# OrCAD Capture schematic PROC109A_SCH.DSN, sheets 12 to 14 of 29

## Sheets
12 12. SOC2: size C; title: SOC2
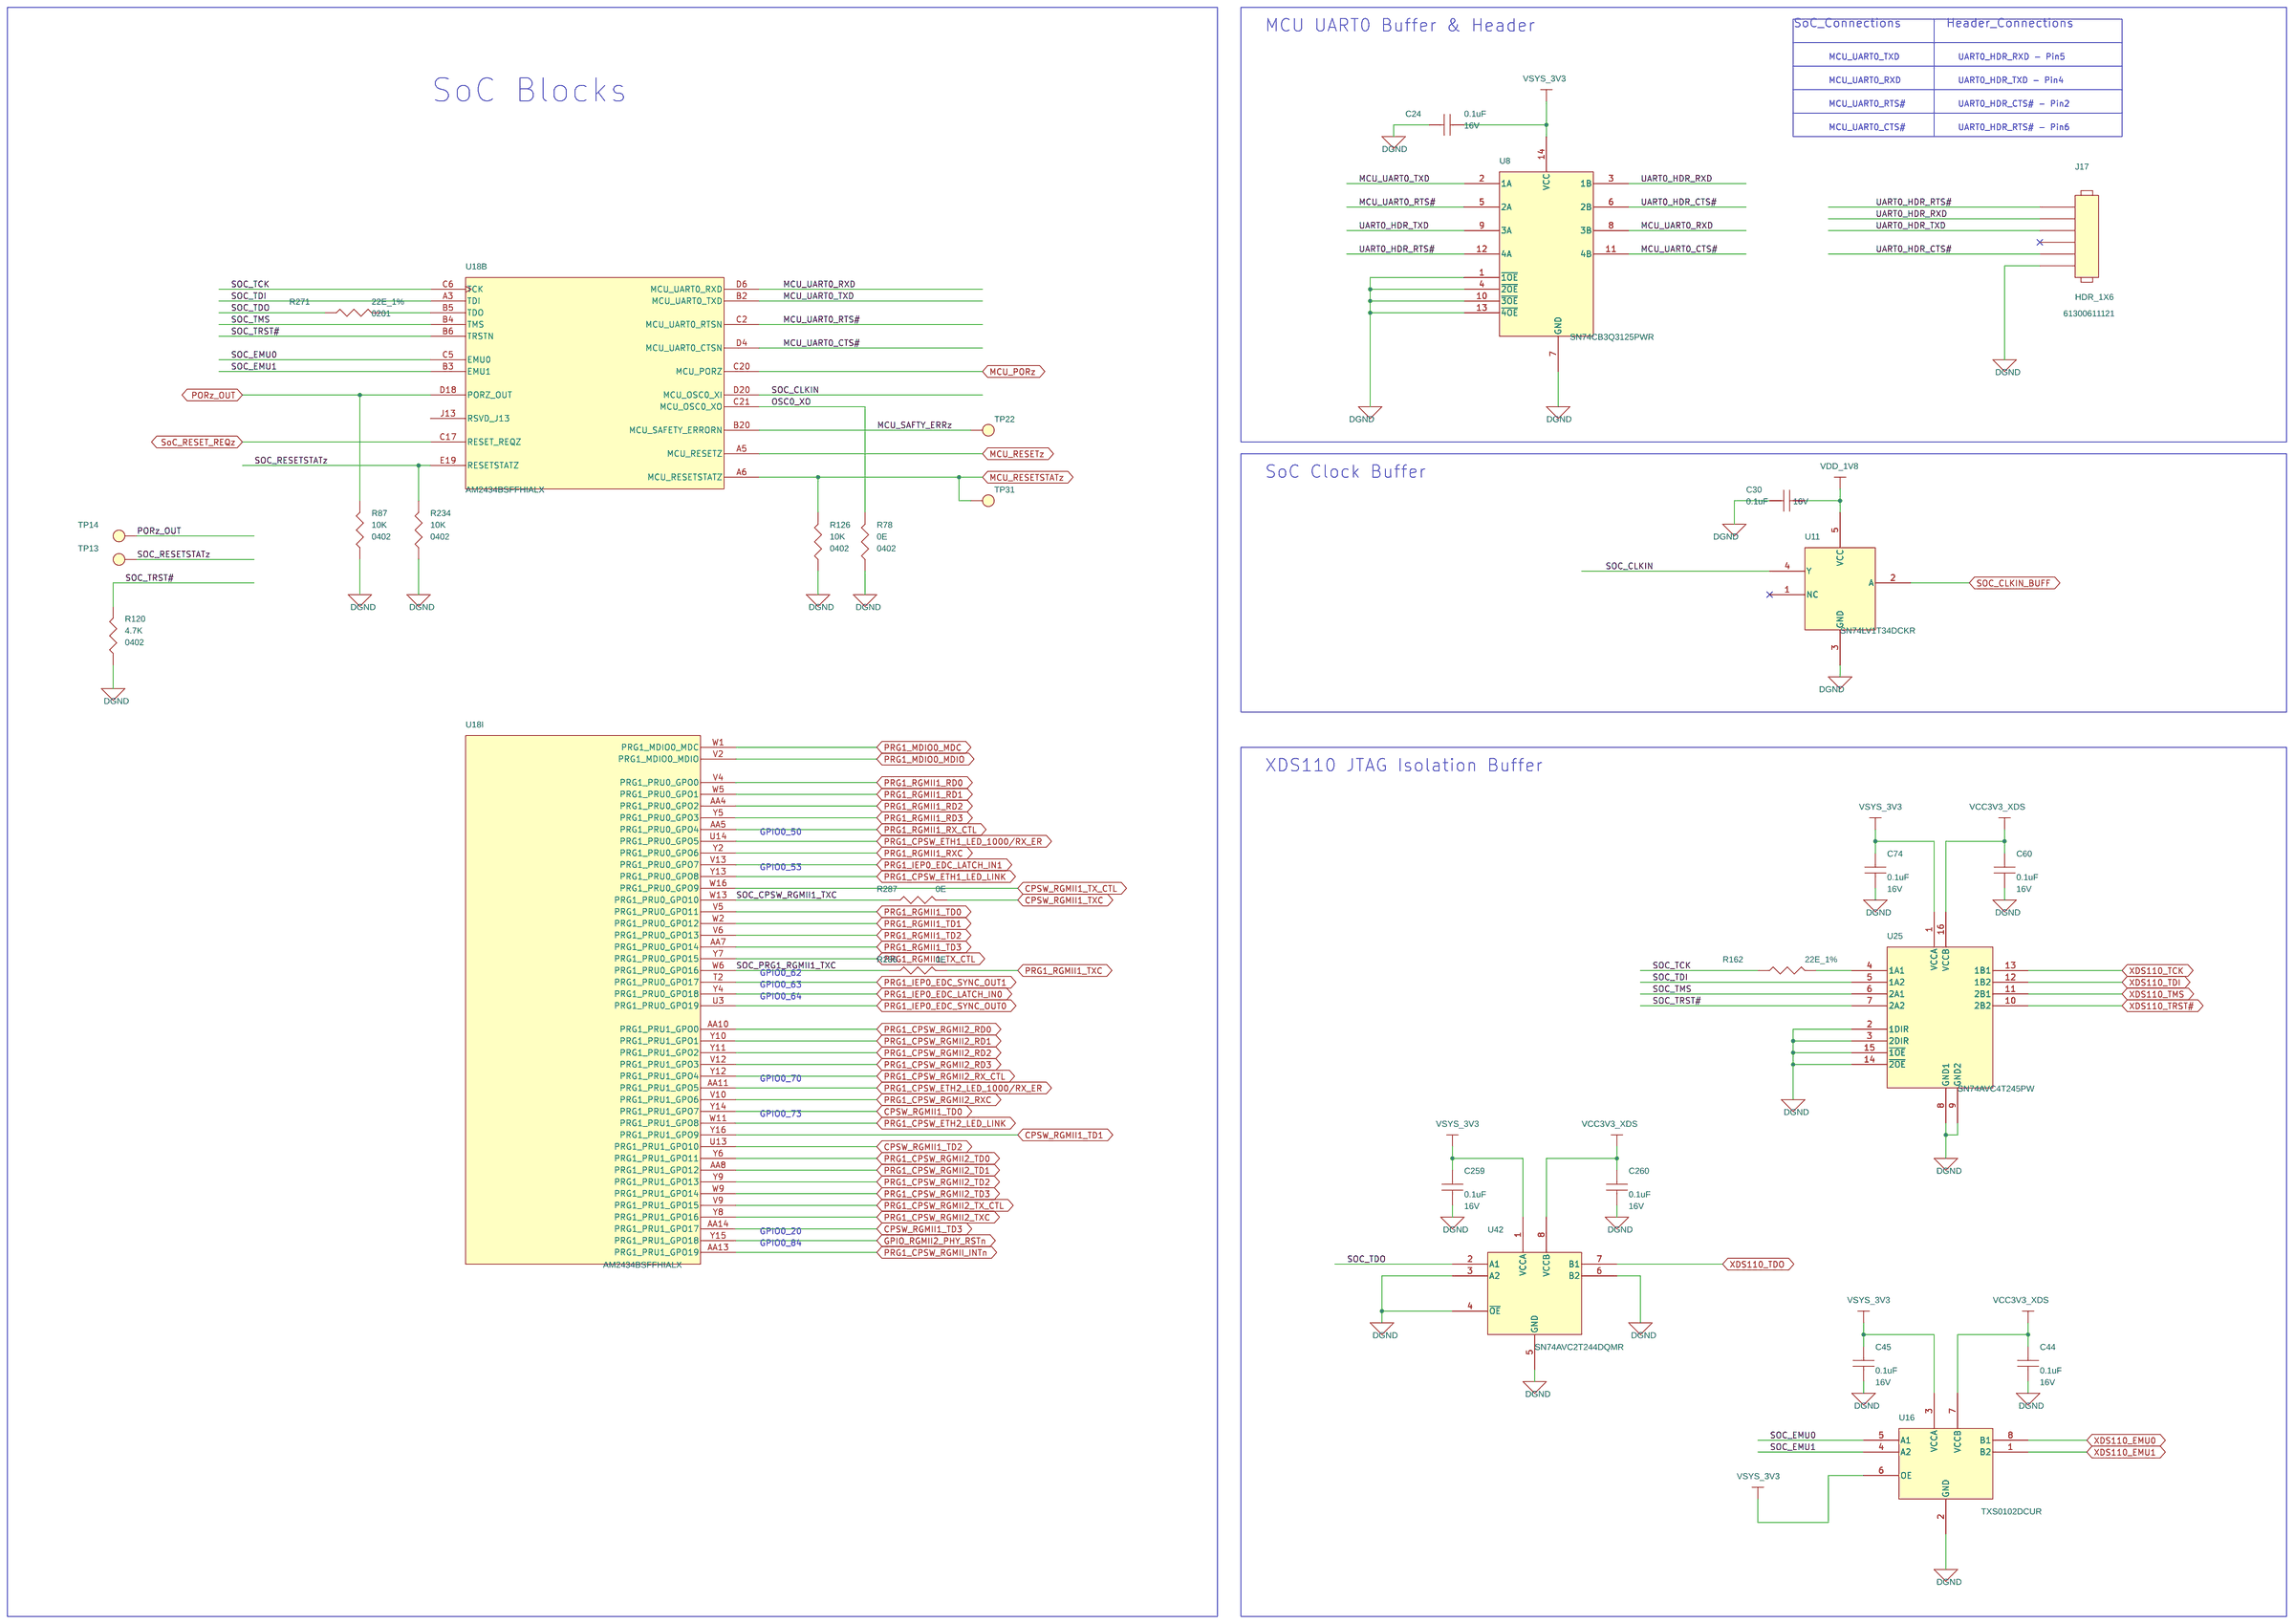
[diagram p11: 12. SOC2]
13 13. MCAN_eQEP_FSI_MUX_USR_LEDs: size C; title: MCAN_eQEP_FSI_MUX
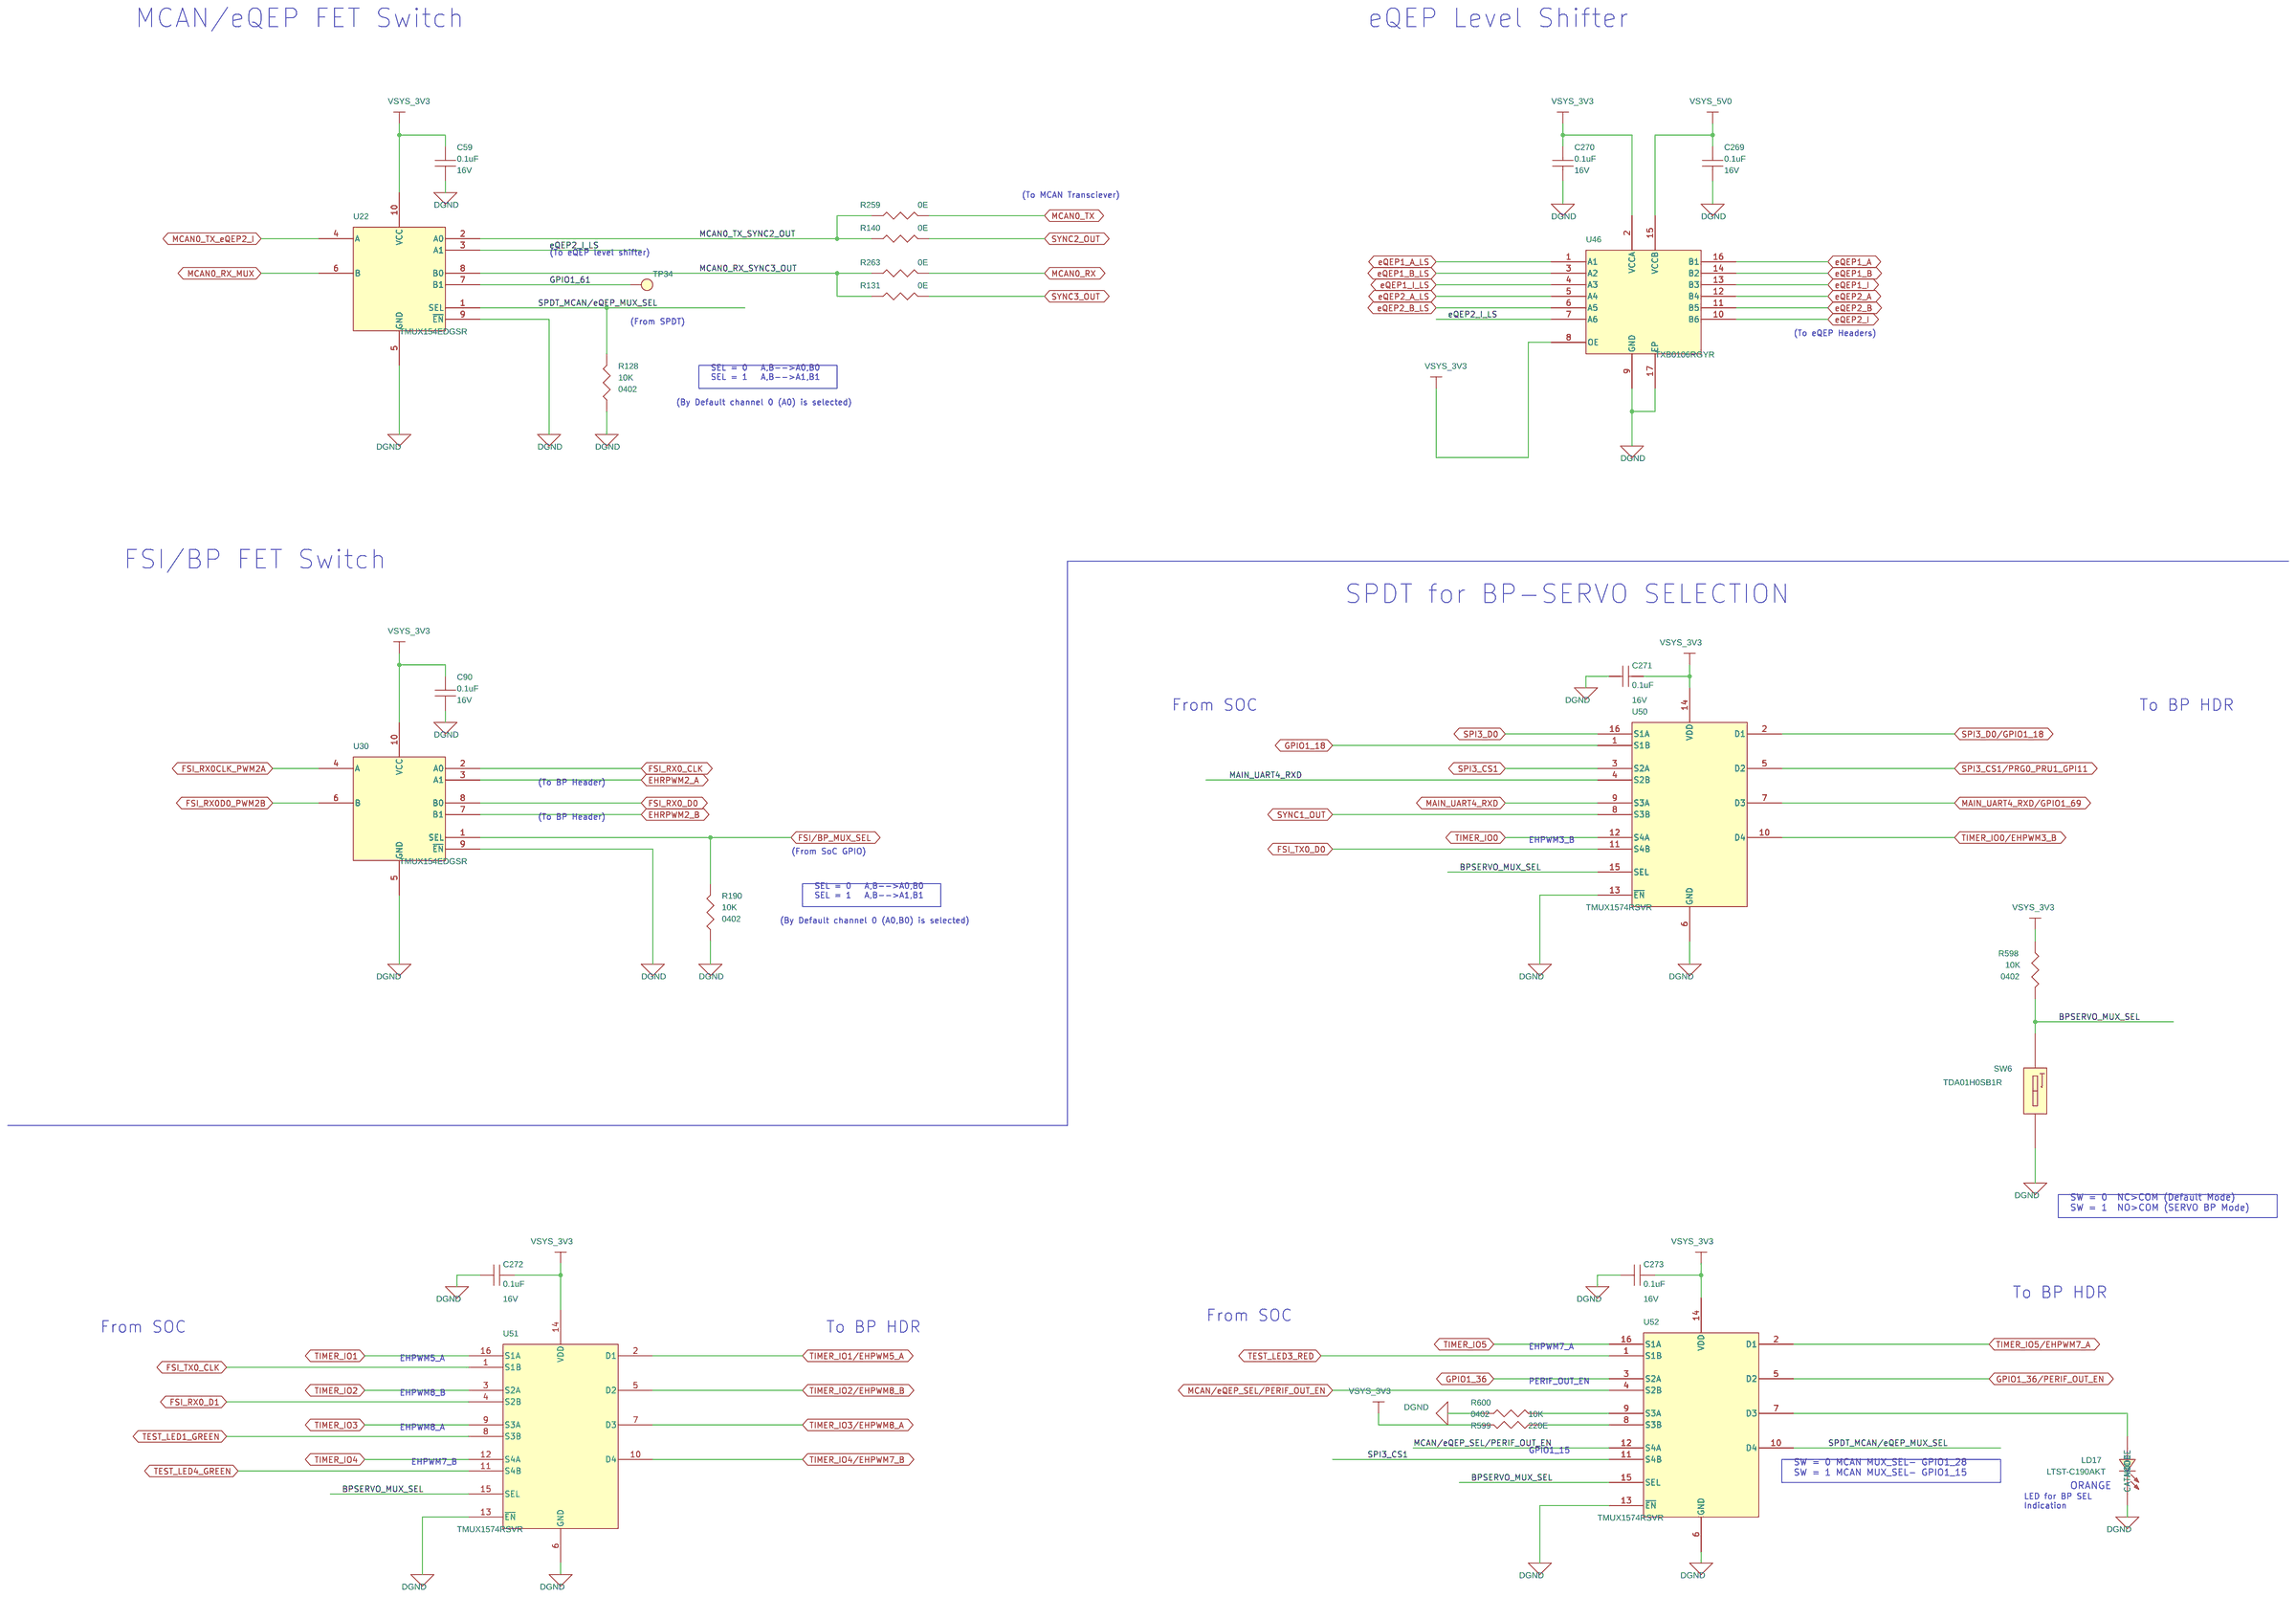
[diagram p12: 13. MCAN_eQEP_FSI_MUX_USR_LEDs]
14 14. CAN_eQEP_FSI_HDR_CLK_BUFFER: size C; title: CAN_eQEP_FSI_HEADERs & CLOCK BUFFER

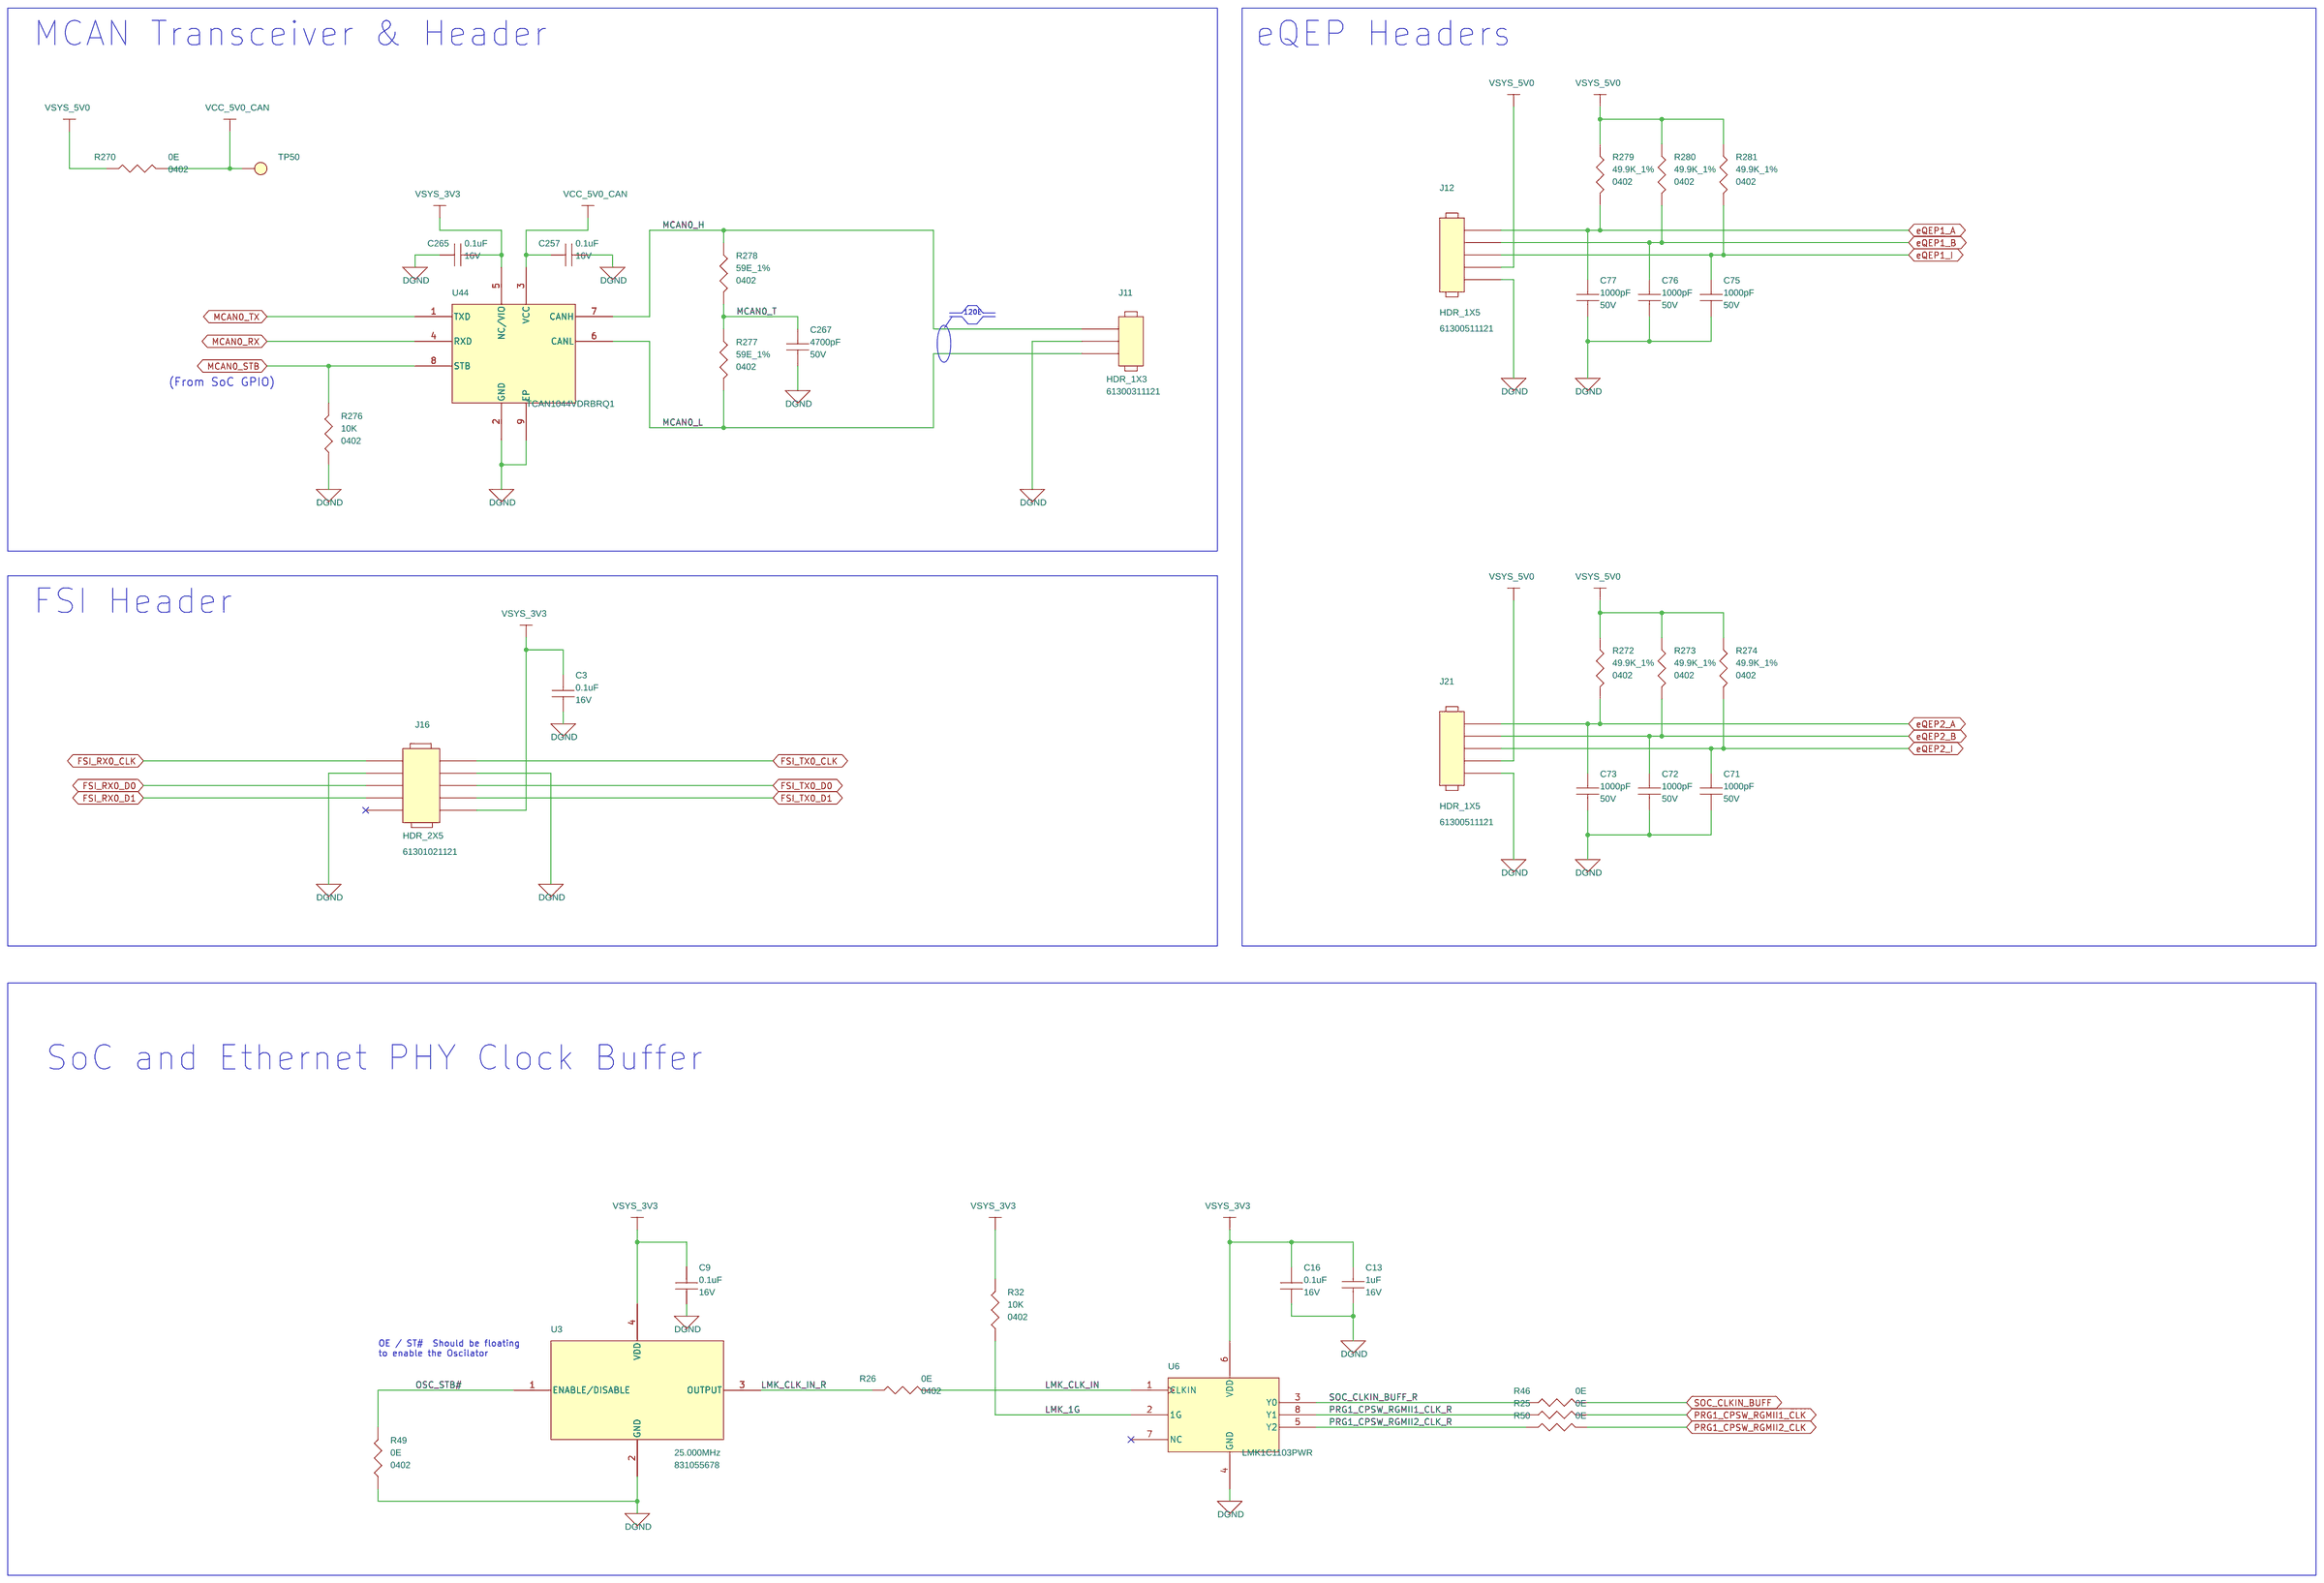
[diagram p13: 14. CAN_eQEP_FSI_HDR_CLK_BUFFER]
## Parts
sheet 12. SOC2
C24  0.1uF  [CAP0201_0-5]
C30  0.1uF  [CAP0201_0-5]
C44  0.1uF  [CAP0201_0-5]
C45  0.1uF  [CAP0201_0-5]
C60  0.1uF  [CAP0201_0-5]
C74  0.1uF  [CAP0201_0-5]
C259  0.1uF  [CAP0201_0-5]
C260  0.1uF  [CAP0201_0-5]
J17  HDR_1X6  [HDR_1X6_61300611121_S_T_8-6]
R78  0E  [RES0402_0-5]
R87  10K  [RES0402_0-5]
R120  4.7K  [RES0402_0-5]
R126  10K  [RES0402_0-5]
R162  22E_1%  [RES0201_0-5]
R234  10K  [RES0402_0-5]
R271  22E_1%  [RES0201_0-5]
R286  0E  [RES0402_0-5]
R287  0E  [RES0402_0-5]
TP13  TP20_SMD  [TP20_SMD]
TP14  TP20_SMD  [TP20_SMD]
TP22  TP20_SMD  [TP20_SMD]
TP31  TP20_SMD  [TP20_SMD]
U8  SN74CB3Q3125PWR  [TSSOP14_25-59_205X180_1-2]
U11  SN74LV1T34DCKR  [SC70-5_1-1]
U16  TXS0102DCUR  [VSSOP8_19-68_85X95_0-9]
U25  SN74AVC4T245PW  [TSSOP16_25-59_205X180]
U42  SN74AVC2T244DQMR  [X2SON8_15-74_70X50]
sheet 13. MCAN_eQEP_FSI_MUX_USR_LEDs
C59  0.1uF  [CAP0201_0-5]
C90  0.1uF  [CAP0201_0-5]
C269  0.1uF  [CAP0201_0-5]
C270  0.1uF  [CAP0201_0-5]
C271  0.1uF  [CAP0201_0-5]
C272  0.1uF  [CAP0201_0-5]
C273  0.1uF  [CAP0201_0-5]
LD17  LTST-C190AKT  [LED_0603]
R128  10K  [RES0402_0-5]
R131  0E  [RES0402_0-5]
R140  0E  [RES0402_0-5]
R190  10K  [RES0402_0-5]
R259  0E  [RES0402_0-5]
R263  0E  [RES0402_0-5]
R598  10K  [RES0402_0-5]
R599  220E  [RES0402_0-5]
R600  10K  [RES0402_0-5]
SW6  TDA01H0SB1R  [SW_TDA01H0S_240X90_SMD_2-3]
TP34  TP20_SMD  [TP20_SMD]
U22  TMUX154EDGSR  [MSOP10_19-68_120X120_1-1]
U30  TMUX154EDGSR  [MSOP10_19-68_120X120_1-1]
U46  TXB0106RGYR  [QFN16_19-68_160X140_1]
U50  TMUX1574RSVR  [UQFN16_TMUX1574_70X100_0-6]
U51  TMUX1574RSVR  [UQFN16_TMUX1574_70X100_0-6]
U52  TMUX1574RSVR  [UQFN16_TMUX1574_70X100_0-6]
sheet 14. CAN_eQEP_FSI_HDR_CLK_BUFFER
C3  0.1uF  [CAP0201_0-5]
C9  0.1uF  [CAP0201_0-5]
C13  1uF  [CAP0201_0-5]
C16  0.1uF  [CAP0201_0-5]
C71  1000pF  [CAP0402_0-75]
C72  1000pF  [CAP0402_0-75]
C73  1000pF  [CAP0402_0-75]
C75  1000pF  [CAP0402_0-75]
C76  1000pF  [CAP0402_0-75]
C77  1000pF  [CAP0402_0-75]
C257  0.1uF  [CAP0201_0-5]
C265  0.1uF  [CAP0201_0-5]
C267  4700pF  [CAP0402_0-75]
J11  HDR_1X3  [HDR_1X3_100_S_T]
J12  HDR_1X5  [HDR_1X5_61300511121_S_T_8-6]
J16  HDR_2X5  [HDR_2X5_61301021121_S_T_8-6]
J21  HDR_1X5  [HDR_1X5_61300511121_S_T_8-6]
R25  0E  [RES0402_0-5]
R26  0E  [RES0402_0-5]
R32  10K  [RES0402_0-5]
R46  0E  [RES0402_0-5]
R49  0E  [RES0402_0-5]
R50  0E  [RES0402_0-5]
R270  0E  [RES0402_0-5]
R272  49.9K_1%  [RES0402_0-5]
R273  49.9K_1%  [RES0402_0-5]
R274  49.9K_1%  [RES0402_0-5]
R276  10K  [RES0402_0-5]
R277  59E_1%  [RES0402_0-5]
R278  59E_1%  [RES0402_0-5]
R279  49.9K_1%  [RES0402_0-5]
R280  49.9K_1%  [RES0402_0-5]
R281  49.9K_1%  [RES0402_0-5]
TP50  TP20_SMD  [TP20_SMD]
U3  25.000MHz  [OSC4_ASEK_130X100_SMD_1-2]
U6  LMK1C1103PWR  [TSSOP8_25-59_125X180_1-2]
U44  TCAN1044VDRBRQ1  [SON8_25-59_130X130_1]
sheet 24. SOC_DIGITAL_POWER_DECAPs
U18  AM2434BSFFHIALX  [BGA293_19-68_440X440_1]  (sections A,B,C,D,E,F,G,H,I,J,K,L,M)

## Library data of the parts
C3 C9 C16 C24 C30 C44 C45 C60 C74 C257 C259 C260 C265 = CAP: CAP CERAMIC 0.1uF 16V 10% X5R 0201; Chkd/date: MANIRAJA/230118; Crtd /date: MANIRAJA/230118; Custom_Duty: 15%; Customs_HS_Code: 85322990; Distributor_name: DIGIKEY; Distributor_part_number: 490-14305-1-ND; Footprint Path: Y:\MIS_DATABASE\Library\ALTIUM_TOOL\PCB_FOOTPRINTS\Altium_Footprint_Lib.PcbLib; Height: 0.33MM; Library Path: Y:\MIS_DATABASE\Library\ALTIUM_TOOL\SCHEMATICS_PARTS\MS_DISCRETE_Library.schlib; Mfr_name: MURATA; Mfr_part_number: GRM033R61C104KE14D; Mistral Part No: 120009030072-R; Package: 0201; Part_type: CAPACITORS\CERAMIC; Project: TI_MAXIE_CPB; RoHS: RoHS; Temperature: -55°C+85°C; Tolerance: 10%; Voltage: 16V; Wattage: NA; Weight: 0.33mg; Datasheet: Y:\MIS_DATABASE\DATASHEETS\CAPACITORS\GRM033R61C104KE14.PDF
J17 = HEADER_6X1: CON HDR 1X6 2.54MM PITCH ST TH; Chkd/date: MANIRAJA/161219; Crtd /date: MANIRAJA/161219; Custom_Duty: 24%; Customs_HS_Code: 85369090; Distributor_name: DIGIKEY; Distributor_part_number: 732-5319-ND; Footprint Path: Y:\MIS_DATABASE\Library\ALTIUM_TOOL\PCB_FOOTPRINTS\Altium_Footprint_Lib.PcbLib; Height: 8.54MM; Library Path: Y:\MIS_DATABASE\Library\ALTIUM_TOOL\SCHEMATICS_PARTS\MS_CONNECTOR_Library.schlib; Mfr_name: WURTH ELECTRONICS; Mfr_part_number: 61300611121; Mistral Part No: 150019120017-R; Package: THRU-HOLE; Part_type: CONNECTOR\HEADERS; Project: SD820_NANOSOM_TESTJIG; RoHS: RoHS; Temperature: -40°C+105°C; Tolerance: NA; Voltage: NA; Wattage: NA; Weight: 342.4mg; Datasheet: Y:\MIS_DATABASE\DATASHEETS\CONNECTORS\6130XXX.PDF
R25 R26 R46 R49 R50 R78 R131 R140 R259 R263 R270 = RESISTOR: RES 0E 1/16W 5% 0402; Chkd/date: VASANTHA/291216; Crtd /date: CHAITHANYA/300911; Custom_Duty: 15%; Customs_HS_Code: 85332119; Distributor_name: DIGIKEY; Distributor_part_number: 311-0.0JRCT-ND; Footprint Path: Y:\MIS_DATABASE\Library\ALTIUM_TOOL\PCB_FOOTPRINTS\Altium_Footprint_Lib.PcbLib; Height: 0.40MM; Library Path: Y:\MIS_DATABASE\Library\ALTIUM_TOOL\SCHEMATICS_PARTS\MS_DISCRETE_Library.schlib; Mfr_name: YAGEO AMERICA; Mfr_part_number: RC0402JR-070RL; Mistral Part No: 110011090036-R; Package: 0402; Part_type: RESISTORS\FIXED; Project: VP-4000-PROCESSOR; RoHS: RoHS; Temperature: -55°C+155°C; Tolerance: 5%; Voltage: NA; Wattage: 1/16W; Weight: 0.65mg; Datasheet: Y:\MIS_DATABASE\DATASHEETS\RESISTORS\RCXXXXL-SER_MAR18.PDF
R32 R87 R126 R128 R190 R234 R276 R598 R600 = RESISTOR: RES 10K 1/16W 5% 0402; Chkd/date: VASANTHA/061216; Crtd /date: MAZHAR/230805; Custom_Duty: 15%; Customs_HS_Code: 85332119; Distributor_name: DIGIKEY; Distributor_part_number: 311-10KJRCT-ND; Footprint Path: Y:\MIS_DATABASE\Library\ALTIUM_TOOL\PCB_FOOTPRINTS\Altium_Footprint_Lib.PcbLib; Height: 0.40MM; Library Path: Y:\MIS_DATABASE\Library\ALTIUM_TOOL\SCHEMATICS_PARTS\MS_DISCRETE_Library.schlib; Mfr_name: YAGEO AMERICA; Mfr_part_number: RC0402JR-0710KL; Mistral Part No: 110011060021-R; Package: 0402; Part_type: RESISTORS\FIXED; Project: HSE; RoHS: RoHS; Temperature: -55°C+155°C; Tolerance: 5%; Voltage: NA; Wattage: 1/16W; Weight: 0.65mg; Datasheet: Y:\MIS_DATABASE\DATASHEETS\RESISTORS\RCXXXXL-SER_MAR18.PDF
R120 = RESISTOR: RES 4.7K 1/16W 5% 0402; Chkd/date: VASANTHA/130516; Crtd /date: VASANTHA/130516; Custom_Duty: 15%; Customs_HS_Code: 85332119; Distributor_name: DIGIKEY; Distributor_part_number: 311-4.7KJRCT-ND; Footprint Path: Y:\MIS_DATABASE\Library\ALTIUM_TOOL\PCB_FOOTPRINTS\Altium_Footprint_Lib.PcbLib; Height: 0.40MM; Library Path: Y:\MIS_DATABASE\Library\ALTIUM_TOOL\SCHEMATICS_PARTS\MS_DISCRETE_Library.schlib; Mfr_name: YAGEO AMERICA; Mfr_part_number: RC0402JR-074K7L; Mistral Part No: 110011060001-R; Package: 0402; Part_type: RESISTORS\FIXED; Project: TMDXCSK368; RoHS: RoHS; Temperature: -55°C+155°C; Tolerance: 5%; Voltage: NA; Wattage: 1/16W; Weight: 0.65mg; Datasheet: Y:\MIS_DATABASE\DATASHEETS\RESISTORS\RCXXXXL-SER_MAR18.PDF
R162 R271 = RESISTOR: RES 22E 1/20W 1% 0201; Chkd/date: MANIRAJA/080319; Crtd /date: ALVY/080319; Custom_Duty: 15%; Customs_HS_Code: 85332119; Distributor_name: DIGIKEY; Distributor_part_number: YAG2518CT-ND; Footprint Path: Y:\MIS_DATABASE\Library\ALTIUM_TOOL\PCB_FOOTPRINTS\Altium_Footprint_Lib.PcbLib; Height: 0.26MM; Library Path: Y:\MIS_DATABASE\Library\ALTIUM_TOOL\SCHEMATICS_PARTS\MS_DISCRETE_Library.schlib; Mfr_name: YAGEO AMERICA; Mfr_part_number: RC0201FR-0722RL; Mistral Part No: 110009030522-R; Package: 0201; Part_type: RESISTORS\FIXED; Project: AM654x_SOM; RoHS: RoHS; Temperature: -55°C+125°C; Tolerance: 1%; Voltage: NA; Wattage: 1/20W; Weight: 0.17mg; Datasheet: Y:\MIS_DATABASE\DATASHEETS\RESISTORS\RCXXXXL-SER_MAR18.PDF
R286 R287 = RESISTOR: RES 0E 1/16W 5% 0402; Chkd/date: VASANTHA/291216; Crtd /date: CHAITHANYA/300911; Custom_Duty: 15%; Customs_HS_Code: 85332119; Distributor_name: DIGIKEY; Distributor_part_number: 311-0.0JRCT-ND; Footprint Path: Y:\MIS_DATABASE\Library\ALTIUM_TOOL\PCB_FOOTPRINTS\Altium_Footprint_Lib.PcbLib; Height: 0.40MM; Library Path: Y:\MIS_DATABASE\Library\ALTIUM_TOOL\SCHEMATICS_PARTS\MS_DISCRETE_Library.schlib; Mfr_name: YAGEO AMERICA; Mfr_part_number: RC0402JR-070RL; Mistral Part No: 110011090036-R; Package: 0402; Part_type: RESISTORS\FIXED; Project: VP-4000-PROCESSOR; RoHS: RoHS; SIGNAL_MODEL: RESISTOR_RES0402_0-5_0E_0E; Temperature: -55°C+155°C; Tolerance: 5%; Voltage: NA; Wattage: 1/16W; Weight: 0.65mg; Datasheet: Y:\MIS_DATABASE\DATASHEETS\RESISTORS\RCXXXXL-SER_MAR18.PDF
TP13 TP14 TP22 TP31 TP34 TP50 = TESTPOINT: TESTPOINT CIR 20 SMD; Chkd/date: SHREESHAIL/171006; Crtd /date: MAZHAR/171006; Custom_Duty: NA; Customs_HS_Code: NA; Distributor_name: NA; Distributor_part_number: NA; Footprint Path: Y:\MIS_DATABASE\Library\ALTIUM_TOOL\PCB_FOOTPRINTS\Altium_Footprint_Lib.PcbLib; Height: NA; Library Path: Y:\MIS_DATABASE\Library\ALTIUM_TOOL\SCHEMATICS_PARTS\MS_DISCRETE_Library.schlib; MECHANICAL 3D STEP FILE: NA; Mfr_name: LOCAL; Mistral Part No: NA; Package: SMD; Project: BT MODULE_CSRBC04; RoHS: NA; Temperature: NA; Tolerance: NA; Voltage: NA; Wattage: NA; Weight: NA; Datasheet: NA
U8 = SN74CBTLV3125PWR_TSSOP14: IC 2.5/3.3V QUADRUPLE HIGH-BANDWIDTH FET BUS SWITCH TSSOP14; Chkd/date: MANIRAJA/241018; Crtd /date: ALVY/241018; Custom_Duty: 15%; Customs_HS_Code: 85423100; Distributor_name: DIGIKEY; Distributor_part_number: 296-16804-1-ND; Footprint Path: Y:\MIS_DATABASE\Library\ALTIUM_TOOL\PCB_FOOTPRINTS\Altium_Footprint_Lib.PcbLib; Height: 1.20MM; Library Path: Y:\MIS_DATABASE\Library\ALTIUM_TOOL\SCHEMATICS_PARTS\MS_COMBINATIONAL_Library.schlib; Mfr_name: TEXAS INSTRUMENTS; Mistral Part No: 141018100021-R; Package: TSSOP14; Part_type: ICS\DIGITAL\COMBINATIONAL; Project: TI_J7ES_EVM_CP; RoHS: RoHS; Temperature: -40°C+85°C; Tolerance: NA; Voltage: NA; Wattage: NA; Weight: 57.2mg; Datasheet: Y:\MIS_DATABASE\DATASHEETS\ICS\DIGITAL\COMBINATIONAL\SN74CB3Q3125.PDF
U11 = SN74LVC1G07DBVR_SOT23-5: IC SINGLE BUFFER GATE CMOS LOGIC LEVEL SHIFTER SC70-5; Chkd/date: MANIRAJA/130819; Crtd /date: MANIRAJA/130819; Custom_Duty: 15%; Customs_HS_Code: 85423100; Distributor_name: DIGIKEY; Distributor_part_number: 296-37177-1-ND; Footprint Path: Y:\MIS_DATABASE\Library\ALTIUM_TOOL\PCB_FOOTPRINTS\Altium_Footprint_Lib.PcbLib; Height: 1.10MM; Library Path: Y:\MIS_DATABASE\Library\ALTIUM_TOOL\SCHEMATICS_PARTS\MS_GATE_Library.schlib; Mfr_name: TEXAS INSTRUMENTS; Mistral Part No: 141019080005-R; Package: SC70-5; Part_type: ICS\DIGITAL\GATES; Project: BRUKER_SD820_COMMONDO; RoHS: RoHS; Temperature: -40°C+125°C; Tolerance: NA; Voltage: NA; Wattage: NA; Weight: 20mg; Datasheet: Y:\MIS_DATABASE\DATASHEETS\ICS\DIGITAL\GATES\SN74LV1T34.PDF
U16 = TXS0102DCUR_VSSOP8: IC 2BIT BI-DIR VOLTAGE-LEVEL TRANSLATOR US8(VSSOP8); Chkd/date: MANIRAJA/130617; Crtd /date: SHREESHAIL/190108; Custom_Duty: 15%; Customs_HS_Code: 85423100; Distributor_name: DIGIKEY; Distributor_part_number: 296-21931-1-ND; Footprint Path: Y:\MIS_DATABASE\Library\ALTIUM_TOOL\PCB_FOOTPRINTS\Altium_Footprint_Lib.PcbLib; Height: 0.90MM; Library Path: Y:\MIS_DATABASE\Library\ALTIUM_TOOL\SCHEMATICS_PARTS\MS_MISCINTERFACE_Library.schlib; Mfr_name: TEXAS INSTRUMENTS; Mistral Part No: 141009030376-R; Package: US8; Part_type: ICS\INTERFACE\LEVEL TRANSLATOR; Project: SD_WATERLOO; RoHS: RoHS; Temperature: -40°C+85°C; Tolerance: NA; Voltage: NA; Wattage: NA; Weight: 9.6mg; Datasheet: Y:\MIS_DATABASE\DATASHEETS\ICS\INTERFACE\TXS0102.PDF
U25 = SN74AVC4T245PW_TSSOP16: IC 4-BIT DUAL SUPPLY BUS TRANSCEIVER TSSOP16; Chkd/date: SHREESHAIL/030506; Crtd /date: MAZHAR/270406; Custom_Duty: 15%; Customs_HS_Code: 85423100; Distributor_name: MOUSER; Distributor_part_number: 595-SN74AVC4T245PW; Height: 1.20MM; Mfr_name: TEXAS INSTRUMENTS; Mistral Part No: 141009030111-R; Package: TSSOP16; Part_type: ICS\DIGITAL\COMBINATIONAL; Project: VOCERA; RoHS: Sb/ Br FREE; Datasheet: Y:\MIS_DATABASE\DATASHEETS\ICS\DIGITAL\BUSTRANSCEIVER\SN74AVC4T245.PDF
U42 = SN74AVC2T244DQMR_X2SON8: IC 2-BIT UNDIRECTIONAL VOLTAGE-LEVEL TRANSLATOR X2SON8; Chkd/date: VASANTHA/060516; Crtd /date: VASANTHA/030316; Customs_HS_Code: 15%; Distributor_name: DIGIKEY; Distributor_part_number: 296-29674-1-ND; Height: 0.40MM; Mfr_name: TEXAS INSTRUMENTS; Mistral Part No: 141016030002-R; Package: X2SON8; Part_type: ICS\INTERFACE\LEVEL TRANSLATOR; Pb-Free: 85423100; Project: OCTASIC_3600; RoHS: RoHS; Temperature: -40°C+85°C; Tolerance: NA; Voltage: NA; Wattage: NA; Weight: NA; Datasheet: Y:\MIS_DATABASE\DATASHEETS\ICS\INTERFACE\SN74AVC2T244.PDF
C59 C90 C269-C273 = CAP: CAP CERAMIC 0.1uF 16V 10% X5R 0201; Alt_Mfr_name: YAGEO AMERICA; Alt_Mfr_part_number: CC0402KRX5R8BB104; Chkd/date: MANIRAJA/230118; Crtd /date: MANIRAJA/230118; Custom_Duty: 15%; Customs_HS_Code: 85322990; Distributor_name: DIGIKEY; Distributor_part_number: 490-14305-1-ND; Footprint Path: Y:\MIS_DATABASE\Library\ALTIUM_TOOL\PCB_FOOTPRINTS\Altium_Footprint_Lib.PcbLib; Height: 0.33MM; Library Path: Y:\MIS_DATABASE\Library\ALTIUM_TOOL\SCHEMATICS_PARTS\MS_DISCRETE_Library.schlib; Mfr_name: MURATA; Mfr_part_number: GRM033R61C104KE14D; Mistral Part No: 120009030072-R; Package: 0201; Part_type: CAPACITORS\CERAMIC; Project: TI_MAXIE_CPB; RoHS: RoHS; Temperature: -55°C+85°C; Tolerance: 10%; Voltage: 16V; Wattage: NA; Weight: 0.33mg; Datasheet: Y:\MIS_DATABASE\DATASHEETS\CAPACITORS\GRM033R61C104KE14.PDF
LD17 = DIODE_LED: DIODE LED ORANGE 0603; Chkd/date: MAZHAR/030608; Crtd /date: USMAN/020608; Custom_Duty: 24%; Customs_HS_Code: 85439000; Distributor_name: DIGIKEY; Distributor_part_number: 160-1180-1-ND; Height: 0.80MM; Mfr_name: LITEON; Mistral Part No: 130009031017-R; Package: 0603; Part_type: OPTO\LED; Project: KMB; RoHS: RoHS; Datasheet: Y:\MIS_DATABASE\DATASHEETS\DISCRETES\LEDS\LTST-C190AKT.PDF
R599 = RESISTOR: RES 220E 1/16W 5% 0402; Chkd/date: ALVY/091220; Crtd /date: MANIRAJA/091220; Custom_Duty: 15%; Customs_HS_Code: 85332119; Distributor_name: DIGIKEY; Distributor_part_number: 311-220JRCT-ND; Footprint Path: Y:\MIS_DATABASE\Library\ALTIUM_TOOL\PCB_FOOTPRINTS\Altium_Footprint_Lib.PcbLib; Height: 0.40MM; Library Path: Y:\MIS_DATABASE\Library\ALTIUM_TOOL\SCHEMATICS_PARTS\MS_DISCRETE_Library.schlib; Mfr_name: YAGEO AMERICA; Mfr_part_number: RC0402JR-07220RL; Mistral Part No: 110020120013-R; Package: 0402; Part_type: RESISTORS\FIXED; Project: TI_AM243x LP EVM; RoHS: RoHS; Temperature: -55°C+155°C; Tolerance: 5%; Voltage: NA; Wattage: 1/16W; Weight: 0.65mg; Datasheet: Y:\MIS_DATABASE\DATASHEETS\RESISTORS\RCXXXXL-SER_MAR18.PDF
SW6 = SW2_CHS-01TA: SWITCH SLIDE 1POS SPST SMD; Chkd/date: MANIRAJA/031018; Crtd /date: MANIRAJA/031018; Custom_Duty: 24%; Customs_HS_Code: 85369090; Distributor_name: DIGIKEY; Distributor_part_number: CKN10538CT-ND; Footprint Path: Y:\MIS_DATABASE\Library\ALTIUM_TOOL\PCB_FOOTPRINTS\Altium_Footprint_Lib.PcbLib; Height: 2.30MM; Library Path: Y:\MIS_DATABASE\Library\ALTIUM_TOOL\SCHEMATICS_PARTS\MS_SWITCH_Library.schlib; Mfr_name: CK; Mistral Part No: 130018100003-R; Package: SMD; Part_type: ELECTRO-MECHANICAL\SWITCH; Project: TI_60GHz-AOP; RoHS: RoHS; Temperature: -40°C+85°C; Tolerance: NA; Voltage: NA; Wattage: NA; Weight: NA; Datasheet: Y:\MIS_DATABASE\DATASHEETS\MISC\SWITCHES\TDAXX-SER.PDF
U22 U30 = TMUX154EDGSR_VSSOP10: IC ESD PROTECTED 2-CH 2:1 SWITCH WITH POWERED-OFF PROTECTION VSSOP10; Chkd/date: MANIRAJA/040918; Crtd /date: MANIRAJA/040918; Custom_Duty: 15%; Customs_HS_Code: 85423100; Distributor_name: DIGIKEY; Distributor_part_number: 296-48347-1-ND; Footprint Path: Y:\MIS_DATABASE\Library\ALTIUM_TOOL\PCB_FOOTPRINTS\Altium_Footprint_Lib.PcbLib; Height: 1.10MM; Library Path: Y:\MIS_DATABASE\Library\ALTIUM_TOOL\SCHEMATICS_PARTS\MS_ANALOG-APPLICATION_Library.schlib; Mfr_name: TEXAS INSTRUMENTS; Mistral Part No: 140118090001-R; Package: VSSOP10; Part_type: ICS\ANALOG\SWITCH; Project: DLRL_DFP_ATRUC CARD; RoHS: RoHS; Temperature: -40°C+85°C; Tolerance: NA; Voltage: NA; Wattage: NA; Weight: NA; Datasheet: Y:\MIS_DATABASE\DATASHEETS\ICS\ANALOG\TMUX154EXXX.PDF
U46 = TXB0106RGYR_VQFN16: IC 6-BIT BIDIRECTIONAL VOLTAGE-LEVEL TRANSLATOR VQFN16; Chkd/date: MANIRAJA/010218; Crtd /date: MANIRAJA/010218; Custom_Duty: 15%; Customs_HS_Code: 85423100; Distributor_name: DIGIKEY; Distributor_part_number: 296-23868-1-ND; Height: 1.00MM; Mfr_name: TEXAS INSTRUMENTS; Mistral Part No: 141018020001-R; Package: VQFN16; Part_type: ICS\INTERFACE\LEVEL TRANSLATOR; Project: NPOL_SAR_ADC; RoHS: RoHS; Temperature: -40°C+85°C; Tolerance: NA; Voltage: NA; Wattage: NA; Weight: 37.2mg; Datasheet: Y:\MIS_DATABASE\DATASHEETS\ICS\INTERFACE\TXB0106X.PDF
U50-U52 = TMUX1574_UQFN16: IC 1.8V 2:1 SPDT 4-CH POWERED-OFF PROTECTED SWITCH UQFN16; Chkd/date: MANIRAJA/100519; Crtd /date: ALVY/090519; Custom_Duty: 15%; Customs_HS_Code: 85423100; Distributor_name: DIGIKEY; Distributor_part_number: 296-53445-1-ND; Footprint Path: Y:\MIS_DATABASE\Library\ALTIUM_TOOL\PCB_FOOTPRINTS\Altium_Footprint_Lib.PcbLib; Height: 0.55MM; Library Path: Y:\MIS_DATABASE\Library\ALTIUM_TOOL\SCHEMATICS_PARTS\MS_MISCPOWER_Library.schlib; Mfr_name: TEXAS INSTRUMENTS; Mistral Part No: 142019050004-R; Package: UQFN16; Part_type: ICS\POWER; Project: AM654x SOM_TEST_JIG; RoHS: RoHS; Temperature: -40°C+125°C; Tolerance: NA; Voltage: NA; Wattage: NA; Weight: 2.5mg; Datasheet: Y:\MIS_DATABASE\DATASHEETS\ICS\POWER\TMUX1574XXX.PDF
C13 = CAP: CAP CERAMIC 1uF 16V 20% X5R 0201; Chkd/date: MANIRAJA/300520; Crtd /date: ALVY/260520; Custom_Duty: 15%; Customs_HS_Code: 85322990; Distributor_name: DIGIKEY; Distributor_part_number: 490-18654-1-ND; Footprint Path: Y:\MIS_DATABASE\Library\ALTIUM_TOOL\PCB_FOOTPRINTS\Altium_Footprint_Lib.PcbLib; Height: 0.39MM; Library Path: Y:\MIS_DATABASE\Library\ALTIUM_TOOL\SCHEMATICS_PARTS\MS_DISCRETE_Library.schlib; Mfr_name: MURATA; Mfr_part_number: GRM033R61C105ME15D; Mistral Part No: 120018090038-R; Package: 0201; Part_type: CAPACITORS\CERAMIC; Project: QCS610_NANOSOM; RoHS: RoHS; Temperature: -55°C+85°C; Tolerance: 20%; Voltage: 16V; Wattage: NA; Weight: 0.33mg; Datasheet: Y:\MIS_DATABASE\DATASHEETS\CAPACITORS\GRM033R61C105ME15.PDF
C71-C73 C75-C77 = CAP: CAP CERAMIC 1000pF 50V 5% C0G(NP0) 0402; Chkd/date: VASANTHA/281216; Crtd /date: MAZHAR/290806; Custom_Duty: 15%; Customs_HS_Code: 85322990; Distributor_name: DIGIKEY; Distributor_part_number: 490-3244-1-ND; Footprint Path: Y:\MIS_DATABASE\Library\ALTIUM_TOOL\PCB_FOOTPRINTS\Altium_Footprint_Lib.PcbLib; Height: 0.55MM; Library Path: Y:\MIS_DATABASE\Library\ALTIUM_TOOL\SCHEMATICS_PARTS\MS_DISCRETE_Library.schlib; Mfr_name: MURATA; Mfr_part_number: GRM1555C1H102JA01D; Mistral Part No: 120016110009-R; Package: 0402; Part_type: CAPACITORS\CERAMIC; Project: SVDO_RMB_MMA; RoHS: RoHS; Temperature: -55°C+125°C; Tolerance: 5%; Voltage: 50V; Wattage: NA; Weight: 6mg; Datasheet: Y:\MIS_DATABASE\DATASHEETS\CAPACITORS\MURATA-GXX-SER_NOV17.PDF
C267 = CAP: CAP CERAMIC 4700pF 50V 10% X7R 0402; Chkd/date: MANIRAJA/170820; Crtd /date: ALVY/170820; Custom_Duty: 15%; Customs_HS_Code: 85322990; Distributor_name: DIGIKEY; Distributor_part_number: 732-7560-1-ND; Footprint Path: Y:\MIS_DATABASE\Library\ALTIUM_TOOL\PCB_FOOTPRINTS\Altium_Footprint_Lib.PcbLib; Height: 0.55MM; Library Path: Y:\MIS_DATABASE\Library\ALTIUM_TOOL\SCHEMATICS_PARTS\MS_DISCRETE_Library.schlib; Mfr_name: WURTH ELECTRONICS; Mfr_part_number: 885012205065; Mistral Part No: 120009030440-R; Package: 0402; Part_type: CAPACITORS\CERAMIC; Project: AM64x_EVM_BRD; RoHS: RoHS; Temperature: -55°C+125°C; Tolerance: 10%; Voltage: 50V; Wattage: NA; Weight: 12mg; Datasheet: Y:\MIS_DATABASE\DATASHEETS\CAPACITORS\885012205065.PDF
J11 = HEADER_3X1: CON HDR 1X3 2.54MM PITCH ST TH; Chkd/date: VASANTHA/211015; Crtd /date: VASANTHA/211015; Custom_Duty: 24%; Customs_HS_Code: 85369090; Distributor_name: DIGIKEY; Distributor_part_number: 732-5316-ND; Height: 8.54MM; Mfr_name: WURTH ELECTRONICS INC; Mfr_part_number: 61300311121; Mistral Part No: 150015100037-R; Package: THRU-HOLE; Part_type: CONNECTOR\HEADERS; Project: CYPHY_ROADKILL; RoHS: RoHS; Temperature: NA; Tolerance: NA; Voltage: NA; Wattage: NA; Weight: NA; Datasheet: Y:\MIS_DATABASE\DATASHEETS\CONNECTORS\6130XXX.PDF
J12 J21 = HEADER_5X1: CON HDR 1X5 2.54MM PITCH ST TH; Chkd/date: MANIRAJA/121120; Crtd /date: ALVY/111120; Custom_Duty: 24%; Customs_HS_Code: 85369090; Distributor_name: DIGIKEY; Distributor_part_number: 732-5318-ND; Footprint Path: Y:\MIS_DATABASE\Library\ALTIUM_TOOL\PCB_FOOTPRINTS\Altium_Footprint_Lib.PcbLib; Height: 8.54MM; Library Path: Y:\MIS_DATABASE\Library\ALTIUM_TOOL\SCHEMATICS_PARTS\MS_CONNECTOR_Library.schlib; Mfr_name: WURTH ELEKTRONIK; Mfr_part_number: 61300511121; Mistral Part No: 150020110010-R; Package: THRU-HOLE; Part_type: CONNECTOR\HEADERS; Project: TI_AM243x LP EVM; RoHS: RoHS; Temperature: -40°C+105°C; Tolerance: NA; Voltage: NA; Wattage: NA; Weight: 280mg; Datasheet: Y:\MIS_DATABASE\DATASHEETS\CONNECTORS\6130XXX.PDF
J16 = HEADER_5X2: CON HDR 2X5 2.54MM PITCH ST TH; Chkd/date: MANIRAJA/121120; Crtd /date: ALVY/111120; Custom_Duty: 24%; Customs_HS_Code: 85369090; Distributor_name: DIGIKEY; Distributor_part_number: 732-2672-ND; Footprint Path: Y:\MIS_DATABASE\Library\ALTIUM_TOOL\PCB_FOOTPRINTS\Altium_Footprint_Lib.PcbLib; Height: 8.54MM; Library Path: Y:\MIS_DATABASE\Library\ALTIUM_TOOL\SCHEMATICS_PARTS\MS_CONNECTOR_Library.schlib; Mfr_name: WURTH ELEKTRONIK; Mfr_part_number: 61301021121; Mistral Part No: 150020110011-R; Package: THRU-HOLE; Part_type: CONNECTOR\HEADERS; Project: TI_AM243x LP EVM; RoHS: RoHS; Temperature: -40°C+105°C; Tolerance: NA; Voltage: NA; Wattage: NA; Weight: 550mg; Datasheet: Y:\MIS_DATABASE\DATASHEETS\CONNECTORS\6130XX21121.PDF
R272-R274 R279-R281 = RESISTOR: RES 49.9K 1/10W 1% 0402; Chkd/date: MANIRAJA/130617; Crtd /date: BAVISH/020611; Custom_Duty: 15%; Customs_HS_Code: 85332119; Distributor_name: DIGIKEY; Distributor_part_number: P49.9KLCT-ND; Footprint Path: Y:\MIS_DATABASE\Library\ALTIUM_TOOL\PCB_FOOTPRINTS\Altium_Footprint_Lib.PcbLib; Height: 0.40MM; Library Path: Y:\MIS_DATABASE\Library\ALTIUM_TOOL\SCHEMATICS_PARTS\MS_DISCRETE_Library.schlib; Mfr_name: PANASONIC-ECG; Mfr_part_number: ERJ-2RKF4992X; Mistral Part No: 110011060018-R; Package: 0402; Part_type: RESISTORS\FIXED; Project: AM4515_EVM_LCD; RoHS: RoHS; Temperature: -55°C+155°C; Tolerance: 1%; Voltage: NA; Wattage: 1/10W; Weight: 0.8mg; Datasheet: Y:\MIS_DATABASE\DATASHEETS\RESISTORS\PAN-ERJSER_NOV17.PDF
R277 R278 = RESISTOR: RES 59E 1/16W 1% 0402; Chkd/date: ALVY/091220; Crtd /date: MANIRAJA/091220; Custom_Duty: 15%; Customs_HS_Code: 85332119; Distributor_name: DIGIKEY; Distributor_part_number: YAG3194CT-ND; Footprint Path: Y:\MIS_DATABASE\Library\ALTIUM_TOOL\PCB_FOOTPRINTS\Altium_Footprint_Lib.PcbLib; Height: 0.40MM; Library Path: Y:\MIS_DATABASE\Library\ALTIUM_TOOL\SCHEMATICS_PARTS\MS_DISCRETE_Library.schlib; Mfr_name: YAGEO AMERICA; Mfr_part_number: RC0402FR-0759RL; Mistral Part No: 110020120010-R; Package: 0402; Part_type: RESISTORS\FIXED; Project: TI_AM243x LP EVM; RoHS: RoHS; Temperature: -55°C+155°C; Tolerance: 1%; Voltage: NA; Wattage: 1/16W; Weight: 0.65mg; Datasheet: Y:\MIS_DATABASE\DATASHEETS\RESISTORS\RCXXXXL-SER_MAR18.PDF
U3 = OSC4_EQXP-HC33: OSC 25.000MHz 3.3V CMOS SMD; Chkd/date: MANIRAJA/070121; Crtd /date: ALVY/060121; Custom_Duty: 24%; Customs_HS_Code: 85437099; Distributor_name: NA; Distributor_part_number: NA; Footprint Path: Y:\MIS_DATABASE\Library\ALTIUM_TOOL\PCB_FOOTPRINTS\Altium_Footprint_Lib.PcbLib; Height: 1.20MM; Library Path: Y:\MIS_DATABASE\Library\ALTIUM_TOOL\SCHEMATICS_PARTS\MS_DISCRETE_Library.schlib; Mfr_name: WURTH ELEKTRONIK; Mfr_part_number: 831055678; Mistral Part No: 130021010008-R; Package: SMD; Part_type: OSCILLATORS; Project: TI_AM243x LP EVM; RoHS: RoHS; Temperature: -40°C+85°C; Tolerance: NA; Voltage: 3.3V; Wattage: NA; Weight: NA; Datasheet: Y:\MIS_DATABASE\DATASHEETS\MISC\CRY_OSC\831055678.PDF
U6 = LMK1C1103_TSSOP8: IC 3-CHANNEL LVCMOS CLOCK BUFFER TSSOP8; Chkd/date: MANIRAJA/080920; Crtd /date: ALVY/070920; Custom_Duty: 15%; Customs_HS_Code: 85423100; Distributor_name: DIGIKEY; Distributor_part_number: 296-LMK1C1103PWRCT-ND; Footprint Path: Y:\MIS_DATABASE\Library\ALTIUM_TOOL\PCB_FOOTPRINTS\Altium_Footprint_Lib.PcbLib; Height: 1.20MM; Library Path: Y:\MIS_DATABASE\Library\ALTIUM_TOOL\SCHEMATICS_PARTS\MS_COMBINATIONAL_Library.schlib; Mfr_name: TEXAS INSTRUMENTS; Mistral Part No: 141020090002-R; Package: TSSOP8; Part_type: ICS\DIGITAL\COMBINATIONAL; Project: AM64X_SKEVM; RoHS: RoHS; Temperature: -40°C+125°C; Tolerance: NA; Voltage: NA; Wattage: NA; Weight: 34.1mg; Datasheet: Y:\MIS_DATABASE\DATASHEETS\ICS\DIGITAL\COMBINATIONAL\LMK1C110X.PDF
U44 = TCAN1044V-Q1_SON8: IC AUTO FAULT-PROTECTED CAN FD TRANSCEIVER SON8; Chkd/date: MANIRAJA/241220; Crtd /date: ALVY/231220; Custom_Duty: 15%; Customs_HS_Code: 85423100; Distributor_name: DIGIKEY; Distributor_part_number: 296-TCAN1044VDRBRQ1CT-ND; Footprint Path: Y:\MIS_DATABASE\Library\ALTIUM_TOOL\PCB_FOOTPRINTS\Altium_Footprint_Lib.PcbLib; Height: 1.00MM; Library Path: Y:\MIS_DATABASE\Library\ALTIUM_TOOL\SCHEMATICS_PARTS\MS_TELECOM_Library.schlib; Mfr_name: TEXAS INSTRUMENTS; Mistral Part No: 143020120003-R; Package: SON8; Part_type: ICS\TELECOM\TRANSCEIVER; Project: TI_AM243x LP EVM; RoHS: RoHS; Temperature: -40°C+125°C; Tolerance: NA; Voltage: NA; Wattage: NA; Weight: NA; Datasheet: Y:\MIS_DATABASE\DATASHEETS\ICS\TELECOM\TCAN1044-Q1.PDF
U18 = AM243X_SOC_LP_EVM_BGA293: IC QUAD CORE R5F- MCU, FCCSP-293; Chkd/date: PRADEEP/130923; Crtd /date: PRADEEP/130923; Custom_Duty: 15%; Customs_HS_Code: 85423100; Distributor_name: NA; Distributor_part_number: NA; Footprint Path: Y:\MIS_DATABASE\Library\ALTIUM_TOOL\PCB_FOOTPRINTS\Altium_Footprint_Lib.PcbLib; Height: 1.00MM; Library Path: Y:\MIS_DATABASE\Library\ALTIUM_TOOL\SCHEMATICS_PARTS\MS_MICROPROCESSOR_Library.schlib; Library Ref: AM243x SoC_LP_EVM_BGA293; Mfr_name: TEXAS INSTRUMENTS; Mistral Part No: 141223090001; Package: BGA293; Part_type: ICS\DIGITAL\MICROPROCESSOR; Project: AM243_LP; RoHS: NA; Temperature: NA; Tolerance: NA; Voltage: NA; Wattage: NA; Weight: NA; Datasheet: Y:\MIS_DATABASE\DATASHEETS\ICS\DIGITAL\MICROCONTROLLER\AM2434.PDF

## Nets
DGND: C3.1 C9.1 C13.2 C16.1 C24.2 C30.1 C44.2 C45.2 C59.2 C60.2 C71.2 C72.2 C73.2 C74.2 C75.2 C76.2 C77.2 C90.2 C257.2 C259.2 C260.2 C265.1 C267.2 C269.2 C270.2 C271.1 C272.1 C273.1 J11.2 J12.5 J16.3 J16.4 J17.1 J21.5 LD17.1(CATHODE) R49.1 R78.1 R87.1 R120.1 R126.1 R128.1 R190.1 R234.1 R276.1 R600.2 SW6.1 U3.2(GND) U6.4(GND) U8.1(~{1OE}) U8.4(~{2OE}) U8.7(GND) U8.10(~{3OE}) U8.13(~{4OE}) U11.3(GND) U16.2(GND) U22.5(GND) U22.9(~{EN}) U25.2(1DIR) U25.3(2DIR) U25.8(GND1) U25.9(GND2) U25.14(~{2OE}) U25.15(~{1OE}) U30.5(GND) U30.9(~{EN}) U42.3(A2) U42.4(~{OE}) U42.5(GND) U42.6(B2) U44.2(GND) U44.9(EP) U46.9(GND) U46.17(EP) U50.6(GND) U50.13(~{EN}) U51.6(GND) U51.13(~{EN}) U52.6(GND) U52.13(~{EN}) ; also on sheet 10 11 15 16 17 18 19 20 21 22 23 24 25 26 27 28
VCC3V3_XDS: C44.1 C60.1 C260.1 U16.7(VCCB) U25.16(VCCB) U42.8(VCCB) ; also on sheet 22
VCC_5V0_CAN: C257.1 R270.2 TP50.1(TP) U44.3(VCC)
VDD_1V8: C30.2 U11.5(VCC) ; also on sheet 10 25 28
BPSERVO_MUX_SEL: R598.1 SW6.2 U50.15(SEL) U51.15(SEL) U52.15(SEL)
CPSW_RGMII1_TD0: U18.Y14(PRG1_PRU1_GPO7) ; also on sheet 16
CPSW_RGMII1_TD1: U18.Y16(PRG1_PRU1_GPO9) ; also on sheet 16
CPSW_RGMII1_TD2: U18.U13(PRG1_PRU1_GPO10) ; also on sheet 16
CPSW_RGMII1_TD3: U18.AA14(PRG1_PRU1_GPO17) ; also on sheet 16
CPSW_RGMII1_TX_CTL: U18.W16(PRG1_PRU0_GPO9) ; also on sheet 16
CPSW_RGMII1_TXC: R287.2 ; also on sheet 16
EHRPWM2_A: U30.3(A1) ; also on sheet 19
EHRPWM2_B: U30.7(B1) ; also on sheet 19
eQEP1_A: C77.1 J12.1 R279.2 U46.16(B1)
eQEP1_A_LS: U46.1(A1) ; also on sheet 11
eQEP1_B: C76.1 J12.2 R280.2 U46.14(B2)
eQEP1_B_LS: U46.3(A2) ; also on sheet 11
eQEP1_I: C75.1 J12.3 R281.2 U46.13(B3)
eQEP1_I_LS: U46.4(A3) ; also on sheet 11
eQEP2_A: C73.1 J21.1 R272.2 U46.12(B4)
eQEP2_A_LS: U46.5(A4) ; also on sheet 11
eQEP2_B: C72.1 J21.2 R273.2 U46.11(B5)
eQEP2_B_LS: U46.6(A5) ; also on sheet 11
eQEP2_I: C71.1 J21.3 R274.2 U46.10(B6)
eQEP2_I_LS: U22.3(A1) U46.7(A6)
FSI/BP_MUX_SEL: R190.2 U30.1(SEL) ; also on sheet 11
FSI_RX0_CLK: J16.1 U30.2(A0)
FSI_RX0_D0: J16.5 U30.8(B0)
FSI_RX0_D1: J16.7 U51.4(S2B) ; also on sheet 11
FSI_RX0CLK_PWM2A: U30.4(A) ; also on sheet 11
FSI_RX0D0_PWM2B: U30.6(B) ; also on sheet 11
FSI_TX0_CLK: J16.2 U51.1(S1B) ; also on sheet 11
FSI_TX0_D0: J16.6 U50.11(S4B) ; also on sheet 11
FSI_TX0_D1: J16.8 ; also on sheet 11
GPIO1_18: U50.1(S1B) ; also on sheet 11 19
GPIO1_36: U52.3(S2A) ; also on sheet 11
GPIO1_36/PERIF_OUT_EN: U52.5(D2) ; also on sheet 19
GPIO1_61: TP34.1(TP) U22.7(B1)
GPIO_RGMII2_PHY_RSTn: U18.Y15(PRG1_PRU1_GPO18) ; also on sheet 18
LMK_1G: R32.1 U6.2(1G)
LMK_CLK_IN: R26.2 U6.1(CLKIN)
LMK_CLK_IN_R: R26.1 U3.3(OUTPUT)
MAIN_UART4_RXD: U50.4(S2B) U50.9(S3A) ; also on sheet 11
MAIN_UART4_RXD/GPIO1_69: U50.7(D3) ; also on sheet 19
MCAN0_H: J11.1 R278.1 U44.7(CANH)
MCAN0_L: J11.3 R277.2 U44.6(CANL)
MCAN0_RX: R263.2 U44.4(RXD)
MCAN0_RX_MUX: U22.6(B) ; also on sheet 11
MCAN0_RX_SYNC3_OUT: R131.1 R263.1 U22.8(B0)
MCAN0_STB: R276.2 U44.8(STB) ; also on sheet 11
MCAN0_T: C267.1 R277.1 R278.2
MCAN0_TX: R259.2 U44.1(TXD)
MCAN0_TX_eQEP2_I: U22.4(A) ; also on sheet 11
MCAN0_TX_SYNC2_OUT: R140.1 R259.1 U22.2(A0)
MCAN/eQEP_SEL/PERIF_OUT_EN: U52.4(S2B) U52.12(S4A) ; also on sheet 11
MCU_PORz: U18.C20(MCU_PORZ) ; also on sheet 10
MCU_RESETSTATz: R126.2 TP31.1(TP) U18.A6(MCU_RESETSTATZ) ; also on sheet 15
MCU_RESETz: U18.A5(MCU_RESETZ) ; also on sheet 10
MCU_SAFTY_ERRz: TP22.1(TP) U18.B20(MCU_SAFETY_ERRORN)
MCU_UART0_CTS#: U8.11(4B) U18.D4(MCU_UART0_CTSN)
MCU_UART0_RTS#: U8.5(2A) U18.C2(MCU_UART0_RTSN)
MCU_UART0_RXD: U8.8(3B) U18.D6(MCU_UART0_RXD)
MCU_UART0_TXD: U8.2(1A) U18.B2(MCU_UART0_TXD)
OSC0_XO: R78.2 U18.C21(MCU_OSC0_XO)
OSC_STB#: R49.2 U3.1(ENABLE/DISABLE)
PORZ_OUT: R87.2 TP14.1(TP) U18.D18(PORZ_OUT) ; also on sheet 11 15 17 18 21
PRG1_CPSW_ETH1_LED_1000/RX_ER: U18.U14(PRG1_PRU0_GPO5) ; also on sheet 17
PRG1_CPSW_ETH1_LED_LINK: U18.Y13(PRG1_PRU0_GPO8) ; also on sheet 17
PRG1_CPSW_ETH2_LED_1000/RX_ER: U18.AA11(PRG1_PRU1_GPO5) ; also on sheet 18
PRG1_CPSW_ETH2_LED_LINK: U18.W11(PRG1_PRU1_GPO8) ; also on sheet 18
PRG1_CPSW_RGMII1_CLK: R25.2 ; also on sheet 17
PRG1_CPSW_RGMII1_CLK_R: R25.1 U6.8(Y1)
PRG1_CPSW_RGMII2_CLK: R50.2 ; also on sheet 18
PRG1_CPSW_RGMII2_CLK_R: R50.1 U6.5(Y2)
PRG1_CPSW_RGMII2_RD0: U18.AA10(PRG1_PRU1_GPO0) ; also on sheet 18
PRG1_CPSW_RGMII2_RD1: U18.Y10(PRG1_PRU1_GPO1) ; also on sheet 18
PRG1_CPSW_RGMII2_RD2: U18.Y11(PRG1_PRU1_GPO2) ; also on sheet 18
PRG1_CPSW_RGMII2_RD3: U18.V12(PRG1_PRU1_GPO3) ; also on sheet 18
PRG1_CPSW_RGMII2_RX_CTL: U18.Y12(PRG1_PRU1_GPO4) ; also on sheet 18
PRG1_CPSW_RGMII2_RXC: U18.V10(PRG1_PRU1_GPO6) ; also on sheet 18
PRG1_CPSW_RGMII2_TD0: U18.Y6(PRG1_PRU1_GPO11) ; also on sheet 18
PRG1_CPSW_RGMII2_TD1: U18.AA8(PRG1_PRU1_GPO12) ; also on sheet 18
PRG1_CPSW_RGMII2_TD2: U18.Y9(PRG1_PRU1_GPO13) ; also on sheet 18
PRG1_CPSW_RGMII2_TD3: U18.W9(PRG1_PRU1_GPO14) ; also on sheet 18
PRG1_CPSW_RGMII2_TX_CTL: U18.V9(PRG1_PRU1_GPO15) ; also on sheet 18
PRG1_CPSW_RGMII2_TXC: U18.Y8(PRG1_PRU1_GPO16) ; also on sheet 18
PRG1_CPSW_RGMII_INTn: U18.AA13(PRG1_PRU1_GPO19) ; also on sheet 17 18
PRG1_IEP0_EDC_LATCH_IN0: U18.Y4(PRG1_PRU0_GPO18) ; also on sheet 19
PRG1_IEP0_EDC_LATCH_IN1: U18.V13(PRG1_PRU0_GPO7) ; also on sheet 19
PRG1_IEP0_EDC_SYNC_OUT0: U18.U3(PRG1_PRU0_GPO19) ; also on sheet 19
PRG1_IEP0_EDC_SYNC_OUT1: U18.T2(PRG1_PRU0_GPO17) ; also on sheet 19
PRG1_MDIO0_MDC: U18.W1(PRG1_MDIO0_MDC) ; also on sheet 17 18
PRG1_MDIO0_MDIO: U18.V2(PRG1_MDIO0_MDIO) ; also on sheet 17 18
PRG1_RGMII1_RD0: U18.V4(PRG1_PRU0_GPO0) ; also on sheet 16
PRG1_RGMII1_RD1: U18.W5(PRG1_PRU0_GPO1) ; also on sheet 16
PRG1_RGMII1_RD2: U18.AA4(PRG1_PRU0_GPO2) ; also on sheet 16
PRG1_RGMII1_RD3: U18.Y5(PRG1_PRU0_GPO3) ; also on sheet 16
PRG1_RGMII1_RX_CTL: U18.AA5(PRG1_PRU0_GPO4) ; also on sheet 16
PRG1_RGMII1_RXC: U18.Y2(PRG1_PRU0_GPO6) ; also on sheet 16
PRG1_RGMII1_TD0: U18.V5(PRG1_PRU0_GPO11) ; also on sheet 16
PRG1_RGMII1_TD1: U18.W2(PRG1_PRU0_GPO12) ; also on sheet 16
PRG1_RGMII1_TD2: U18.V6(PRG1_PRU0_GPO13) ; also on sheet 16
PRG1_RGMII1_TD3: U18.AA7(PRG1_PRU0_GPO14) ; also on sheet 16
PRG1_RGMII1_TX_CTL: U18.Y7(PRG1_PRU0_GPO15) ; also on sheet 16
PRG1_RGMII1_TXC: R286.2 ; also on sheet 16
SOC_CLKIN: U11.4(Y) U18.D20(MCU_OSC0_XI)
SOC_CLKIN_BUFF: R46.2 U11.2(A)
SOC_CLKIN_BUFF_R: R46.1 U6.3(Y0)
SOC_CPSW_RGMII1_TXC: R287.1 U18.W13(PRG1_PRU0_GPO10)
SOC_EMU0: U16.5(A1) U18.C5(EMU0)
SOC_EMU1: U16.4(A2) U18.B3(EMU1)
SOC_PRG1_RGMII1_TXC: R286.1 U18.W6(PRG1_PRU0_GPO16)
SoC_RESET_REQz: U18.C17(RESET_REQZ) ; also on sheet 10
SOC_RESETSTATz: R234.2 TP13.1(TP) U18.E19(RESETSTATZ)
SOC_TCK: R162.1 U18.C6(TCK)
SOC_TDI: U18.A3(TDI) U25.5(1A2)
SOC_TDO: R271.1 U42.2(A1)
SOC_TMS: U18.B4(TMS) U25.6(2A1)
SOC_TRST#: R120.2 U18.B6(TRSTN) U25.7(2A2)
SPDT_MCAN/eQEP_MUX_SEL: R128.2 U22.1(SEL) U52.10(D4)
SPI3_CS1: U50.3(S2A) U52.11(S4B) ; also on sheet 11
SPI3_CS1/PRG0_PRU1_GPI11: U50.5(D2) ; also on sheet 19
SPI3_D0: U50.16(S1A) ; also on sheet 11
SPI3_D0/GPIO1_18: U50.2(D1) ; also on sheet 19
SYNC1_OUT: U50.8(S3B) ; also on sheet 11 19
SYNC2_OUT: R140.2 ; also on sheet 19
SYNC3_OUT: R131.2 ; also on sheet 19
TEST_LED1_GREEN: U51.8(S3B) ; also on sheet 11 23
TEST_LED3_RED: U52.1(S1B) ; also on sheet 11 23
TEST_LED4_GREEN: U51.11(S4B) ; also on sheet 11 23
TIMER_IO0: U50.12(S4A) ; also on sheet 19
TIMER_IO0/EHPWM3_B: U50.10(D4) ; also on sheet 19
TIMER_IO1: U51.16(S1A) ; also on sheet 19
TIMER_IO1/EHPWM5_A: U51.2(D1) ; also on sheet 19
TIMER_IO2: U51.3(S2A) ; also on sheet 19
TIMER_IO2/EHPWM8_B: U51.5(D2) ; also on sheet 19
TIMER_IO3: U51.9(S3A) ; also on sheet 19
TIMER_IO3/EHPWM8_A: U51.7(D3) ; also on sheet 19
TIMER_IO4: U51.12(S4A) ; also on sheet 19
TIMER_IO4/EHPWM7_B: U51.10(D4) ; also on sheet 19
TIMER_IO5: U52.16(S1A) ; also on sheet 19
TIMER_IO5/EHPWM7_A: U52.2(D1) ; also on sheet 19
UART0_HDR_CTS#: J17.2 U8.6(2B)
UART0_HDR_RTS#: J17.6 U8.12(4A)
UART0_HDR_RXD: J17.5 U8.3(1B)
UART0_HDR_TXD: J17.4 U8.9(3A)
VSYS_3V3: C3.2 C9.2 C13.1 C16.2 C24.1 C45.1 C59.1 C74.1 C90.1 C259.1 C265.2 C270.1 C271.2 C272.2 C273.2 J16.10 R32.2 R598.2 R599.2 U3.4(VDD) U6.6(VDD) U8.14(VCC) U16.3(VCCA) U16.6(OE) U22.10(VCC) U25.1(VCCA) U30.10(VCC) U42.1(VCCA) U44.5(NC/VIO) U46.2(VCCA) U46.8(OE) U50.14(VDD) U51.14(VDD) U52.14(VDD) ; also on sheet 10 11 15 16 17 18 19 20 21 22 23 24 25 27 28
VSYS_5V0: C269.1 J12.4 J21.4 R270.1 R272.1 R273.1 R274.1 R279.1 R280.1 R281.1 U46.15(VCCB) ; also on sheet 10 19 20 25 26 27 28
XDS110_EMU0: U16.8(B1) ; also on sheet 22
XDS110_EMU1: U16.1(B2) ; also on sheet 22
XDS110_TCK: U25.13(1B1) ; also on sheet 22
XDS110_TDI: U25.12(1B2) ; also on sheet 22
XDS110_TDO: U42.7(B1) ; also on sheet 22
XDS110_TMS: U25.11(2B1) ; also on sheet 22
XDS110_TRST#: U25.10(2B2) ; also on sheet 22
N30625746: R271.2 U18.B5(TDO)
N30979572: R162.2 U25.4(1A1)
N32341452: LD17.2(ANODE) U52.7(D3)
N32341704: R599.1 U52.8(S3B)
N32341897: R600.1 U52.9(S3A)

Not connected (* = marked no-connect by the designer): J16 9*; J17 3*; U6 7(NC)*; U11 1(NC)*; U18 J13(RSVD)

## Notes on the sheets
sheet 12
- MCU UART0 Buffer & Header
- SoC_Connections
- Header_Connections
- MCU_UART0_TXD
- UART0_HDR_RXD - Pin5
- SoC Blocks
- MCU_UART0_RXD
- UART0_HDR_TXD - Pin4
- MCU_UART0_RTS#
- UART0_HDR_CTS# - Pin2
- MCU_UART0_CTS#
- UART0_HDR_RTS# - Pin6
- SoC Clock Buffer
- XDS110 JTAG Isolation Buffer
- GPIO0_50
- GPIO0_53
- GPIO0_62
- GPIO0_63
- GPIO0_64
- GPIO0_70
- GPIO0_73
- GPIO0_20
- GPIO0_84
sheet 13
- MCAN/eQEP FET Switch
- eQEP Level Shifter
- (To MCAN Transciever)
- (To eQEP level shifter)
- (From SPDT)
- (To eQEP Headers)
- SEL = 0   A,B-->A0,B0
  SEL = 1   A,B-->A1,B1
- (By Default channel 0 (A0) is selected)
- FSI/BP FET Switch
- SPDT for BP-SERVO SELECTION
- From SOC
- To BP HDR
- (To BP Header)
- (To BP Header)
- (From SoC GPIO)
- EHPWM3_B
- SEL = 0   A,B-->A0,B0
  SEL = 1   A,B-->A1,B1
- (By Default channel 0 (A0,B0) is selected)
- SW = 0  NC>COM (Default Mode)
  SW = 1  NO>COM (SERVO BP Mode)
- To BP HDR
- From SOC
- From SOC
- To BP HDR
- EHPWM7_A
- EHPWM5_A
- PERIF_OUT_EN
- EHPWM8_B
- EHPWM8_A
- GPIO1_15
- EHPWM7_B
- SW = 0 MCAN MUX_SEL- GPIO1_28
  SW = 1 MCAN MUX_SEL- GPIO1_15
- ORANGE
- LED for BP SEL
  Indication
sheet 14
- MCAN Transceiver & Header
- eQEP Headers
- 120E
- (From SoC GPIO)
- FSI Header
- SoC and Ethernet PHY Clock Buffer
- OE / ST#  Should be floating
  to enable the Oscilator
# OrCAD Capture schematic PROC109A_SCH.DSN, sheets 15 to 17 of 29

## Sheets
15 15. SOC_QSPI_BOARD_ID_EEPROM: size C; title: QSPI_BOARD_ID_EEPROM
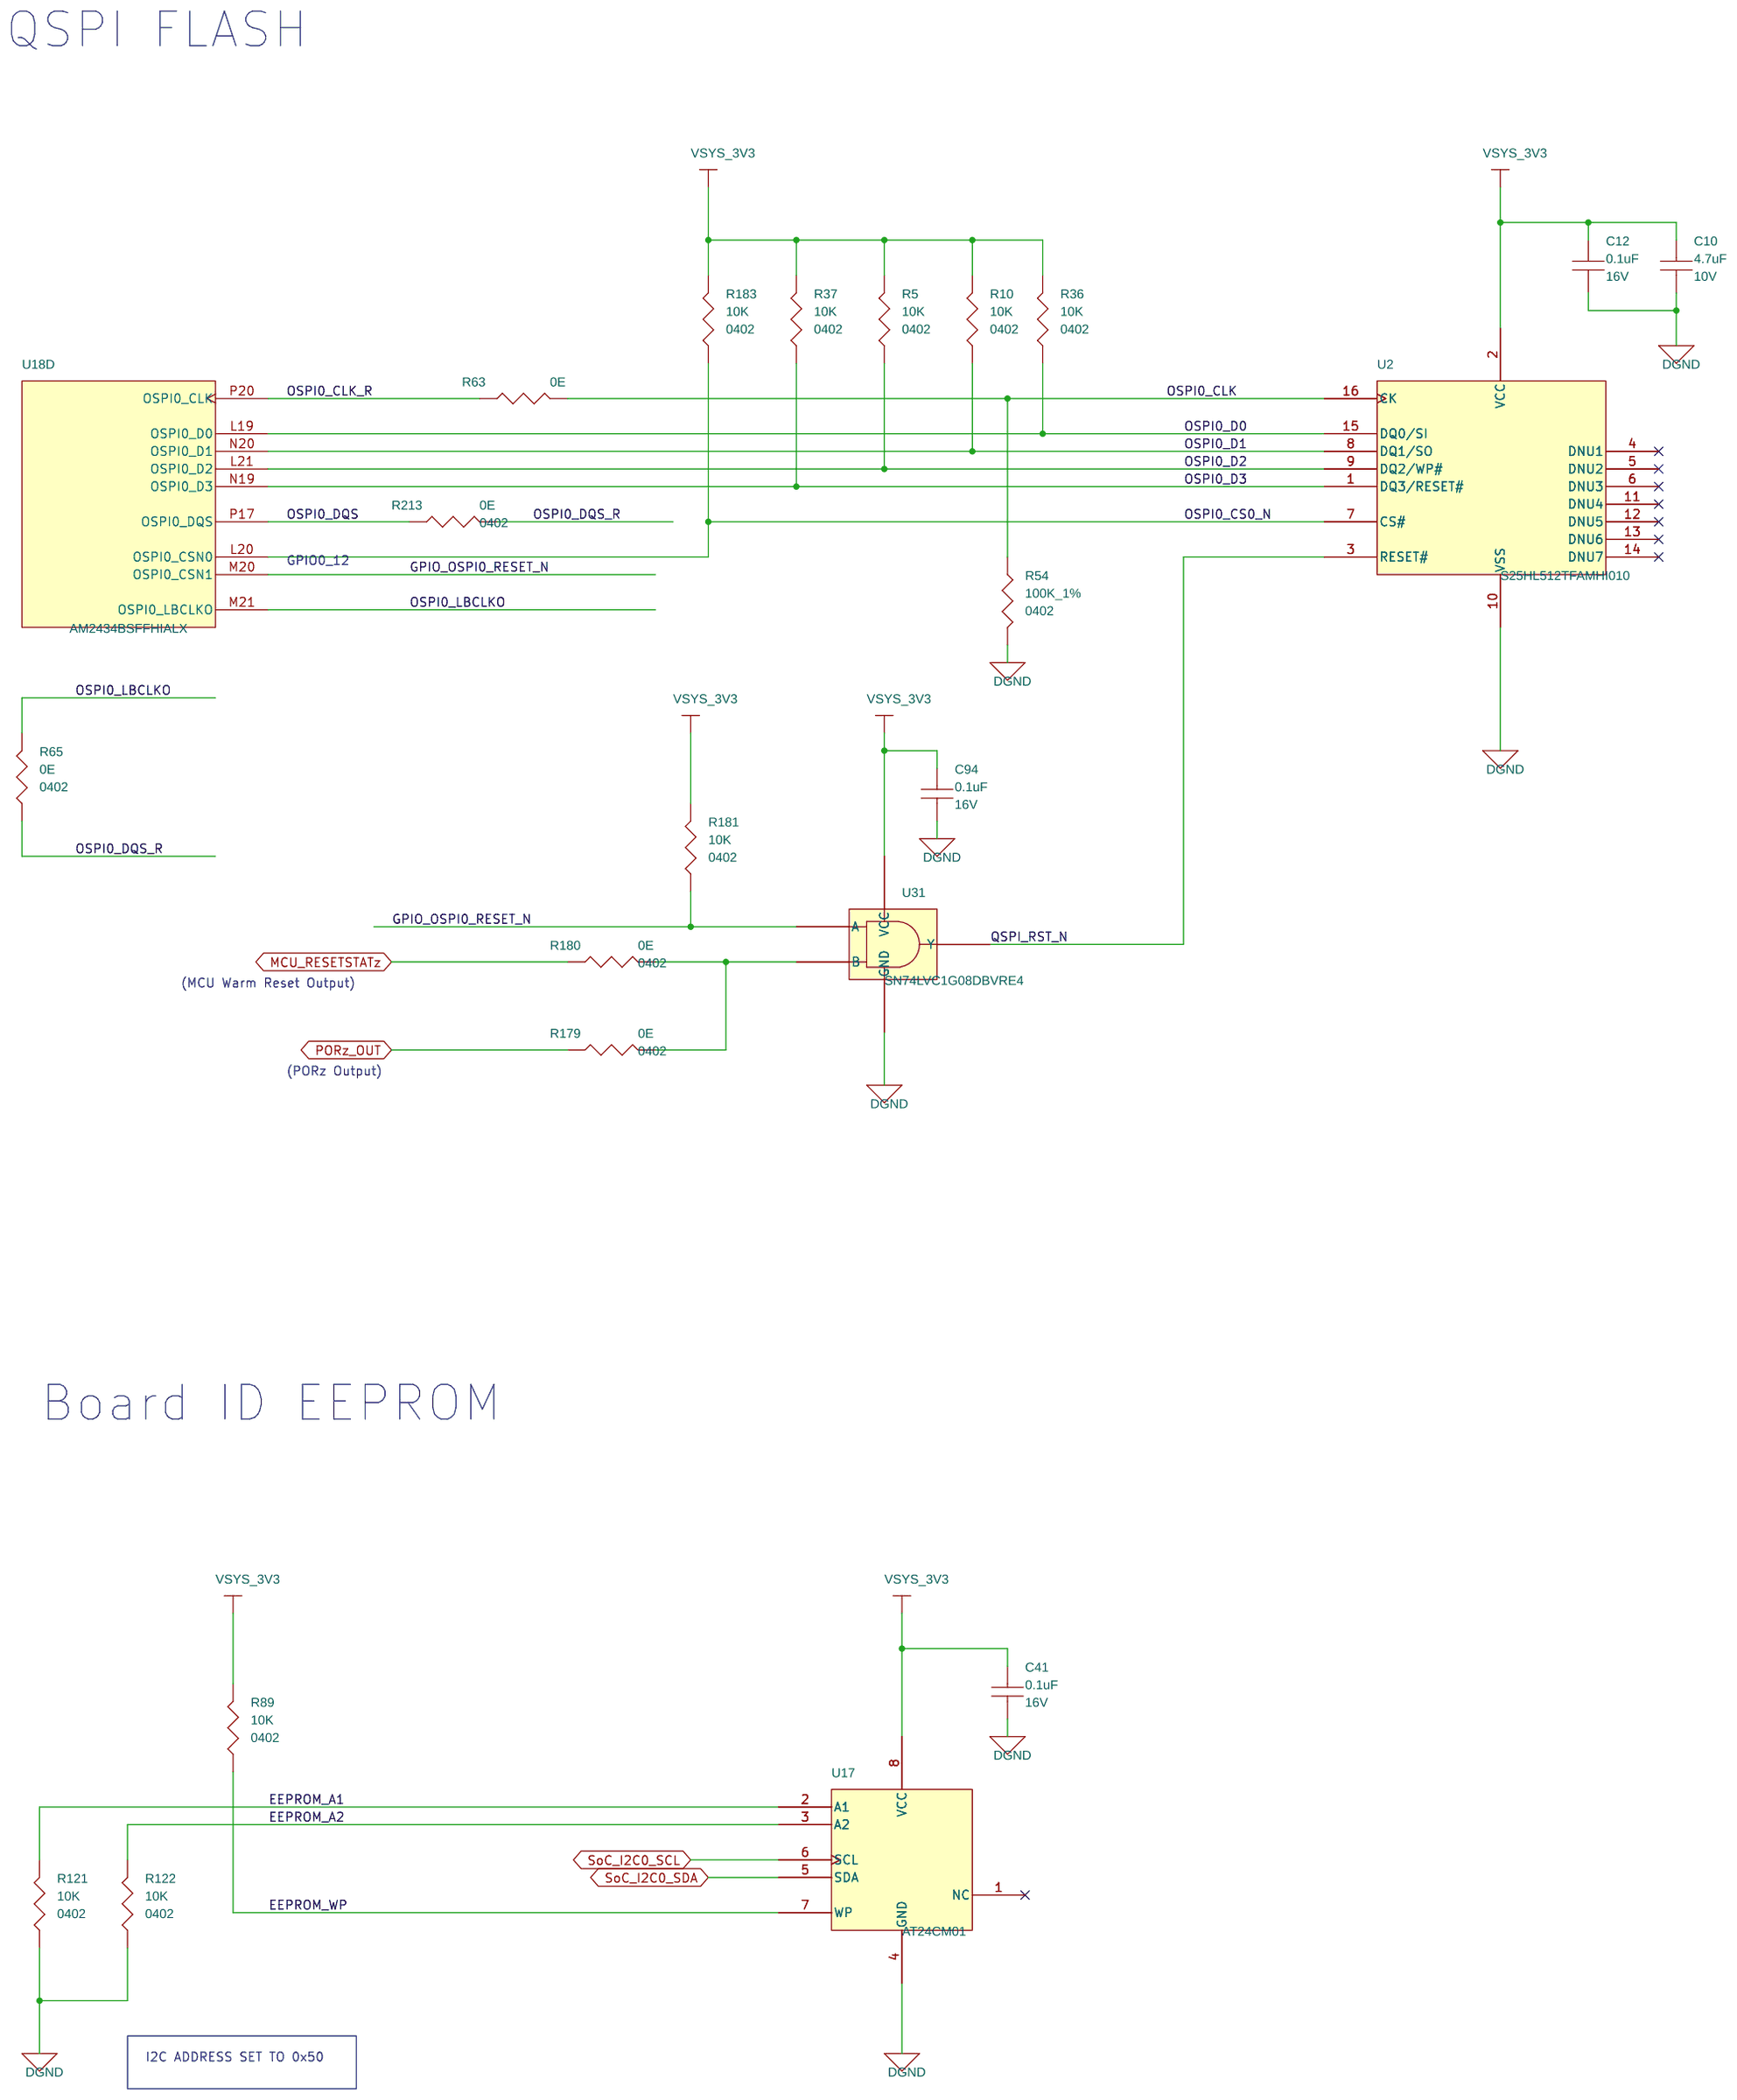
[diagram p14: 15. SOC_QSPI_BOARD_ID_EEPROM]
16 16. ETHERNET_MUX_SoC_ADC_IN: size C; title: ETHERNET DATA MUX & ADC INPUTS
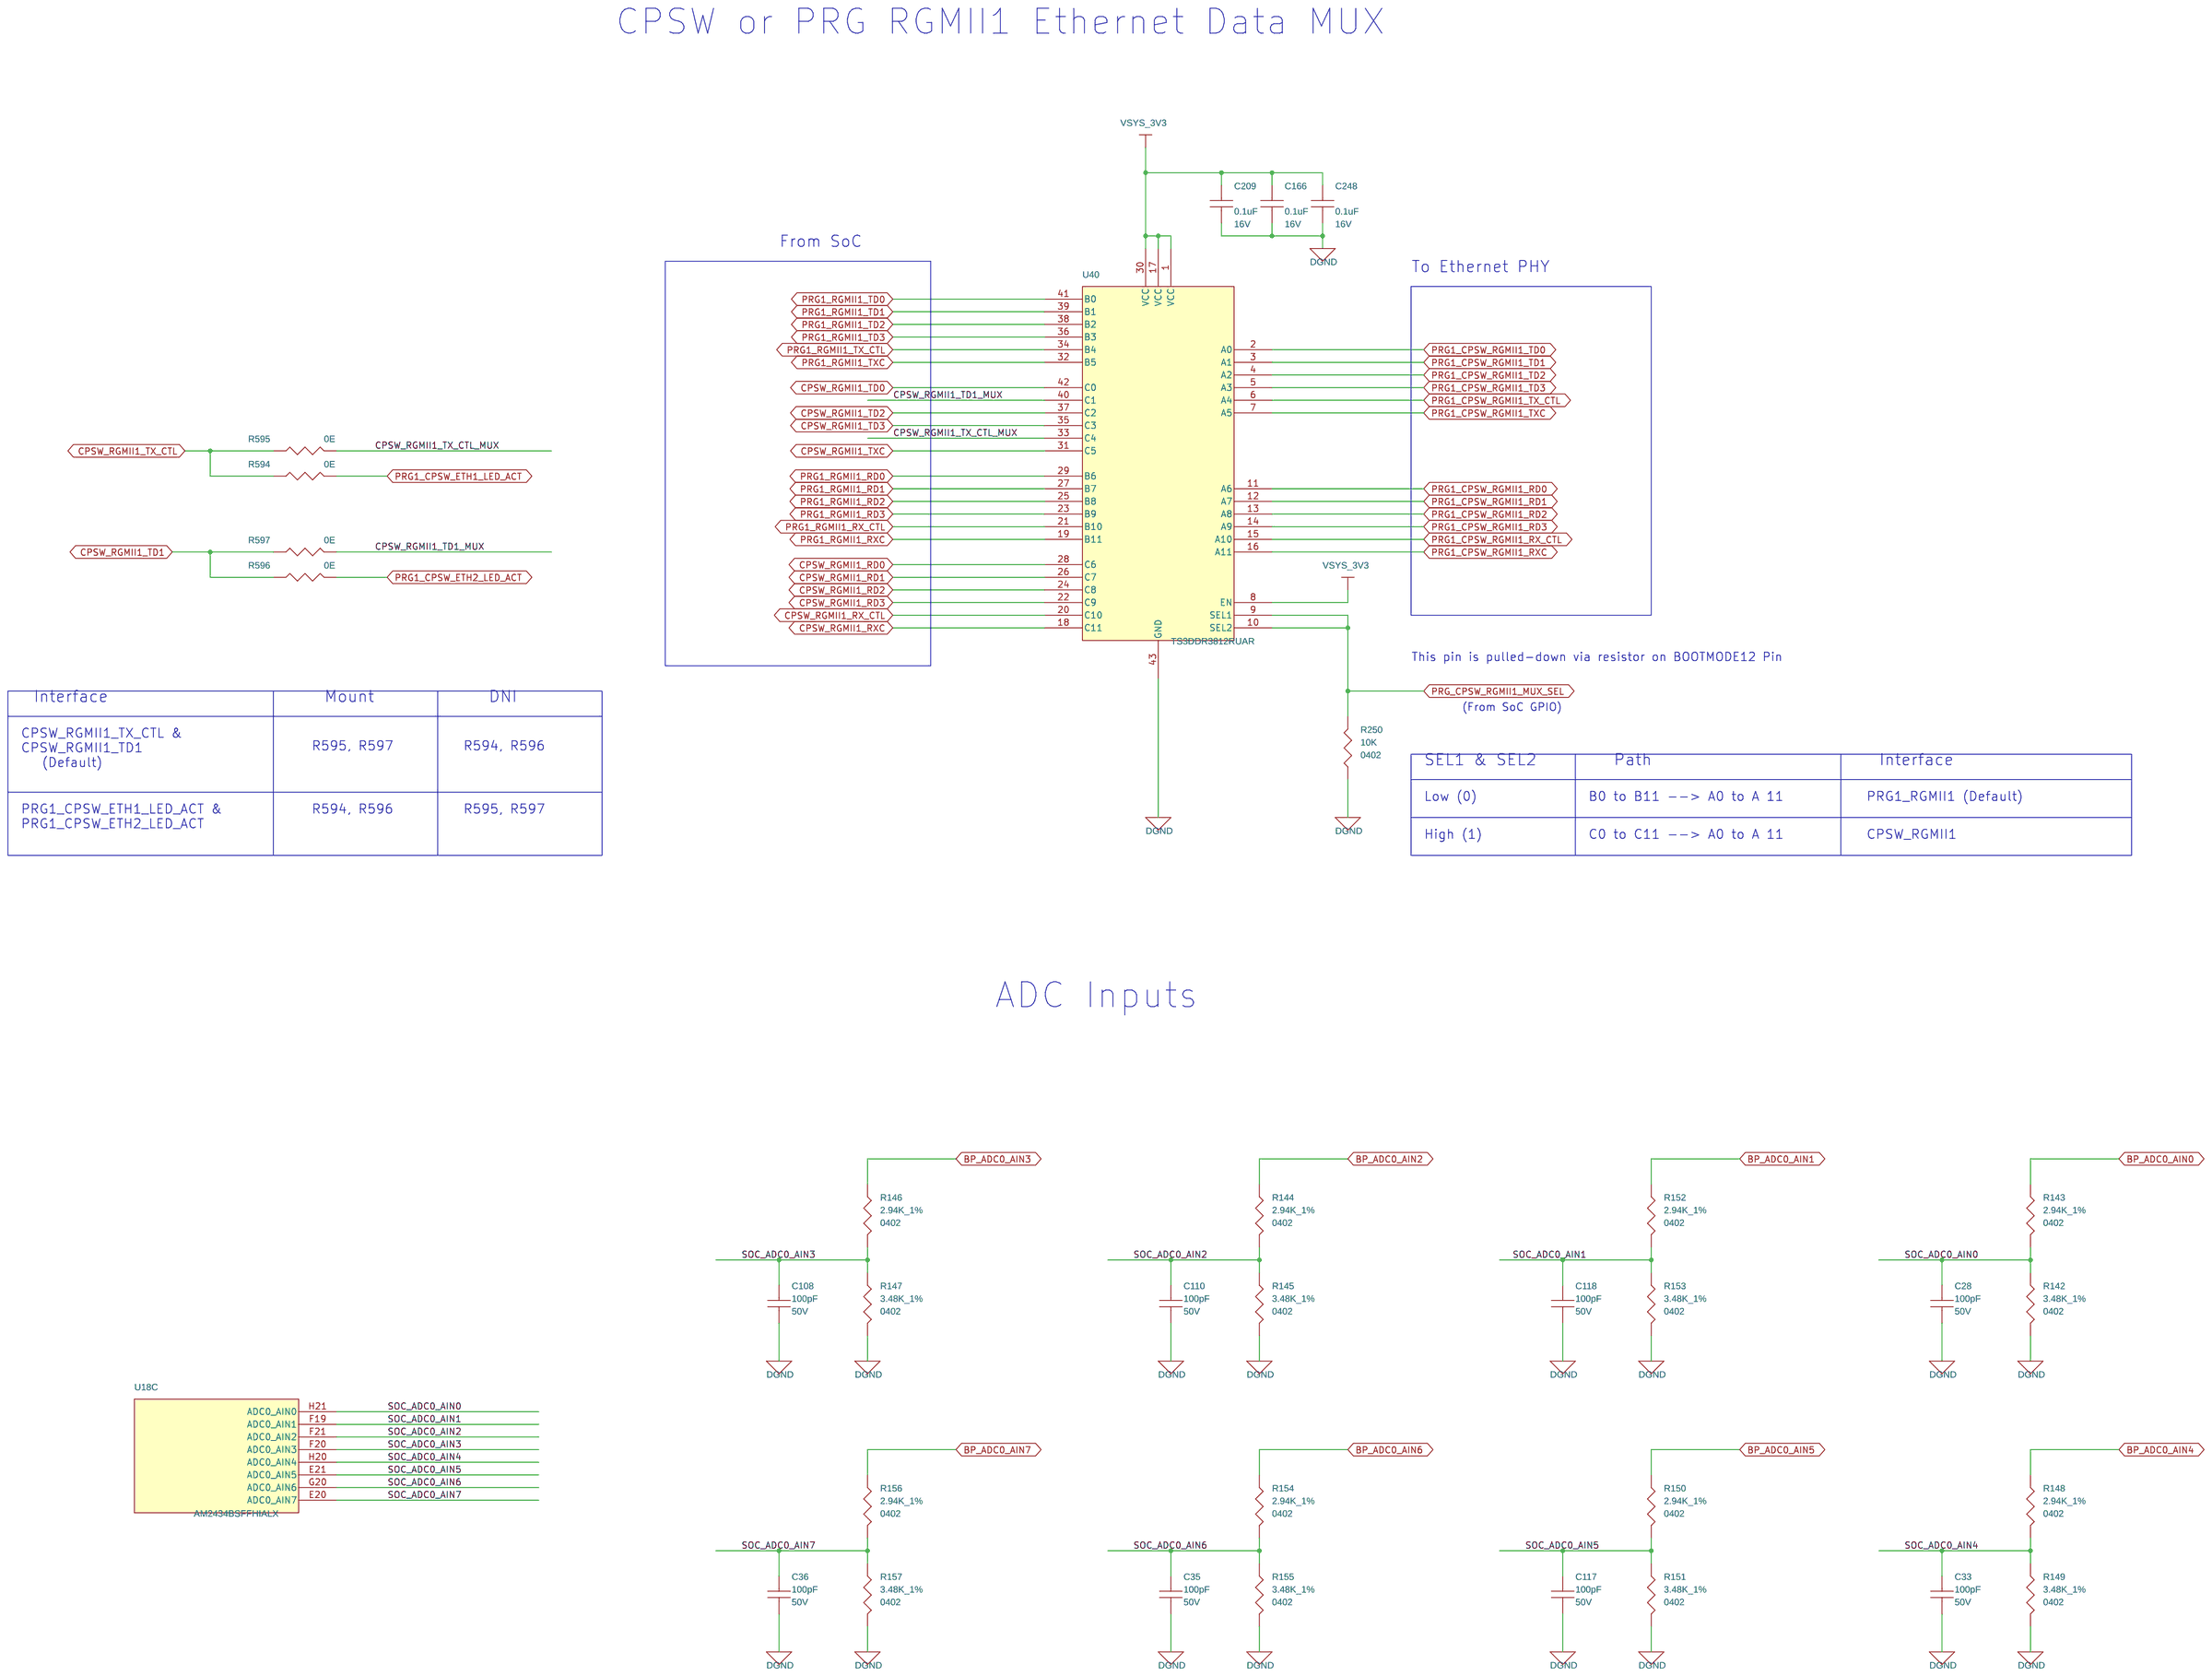
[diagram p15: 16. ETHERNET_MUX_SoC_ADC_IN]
17 17. CPSW_PRG_RGMII_1_EPHY: size C; title: PRG/CPSW RGMII1 ETHERNET PHY

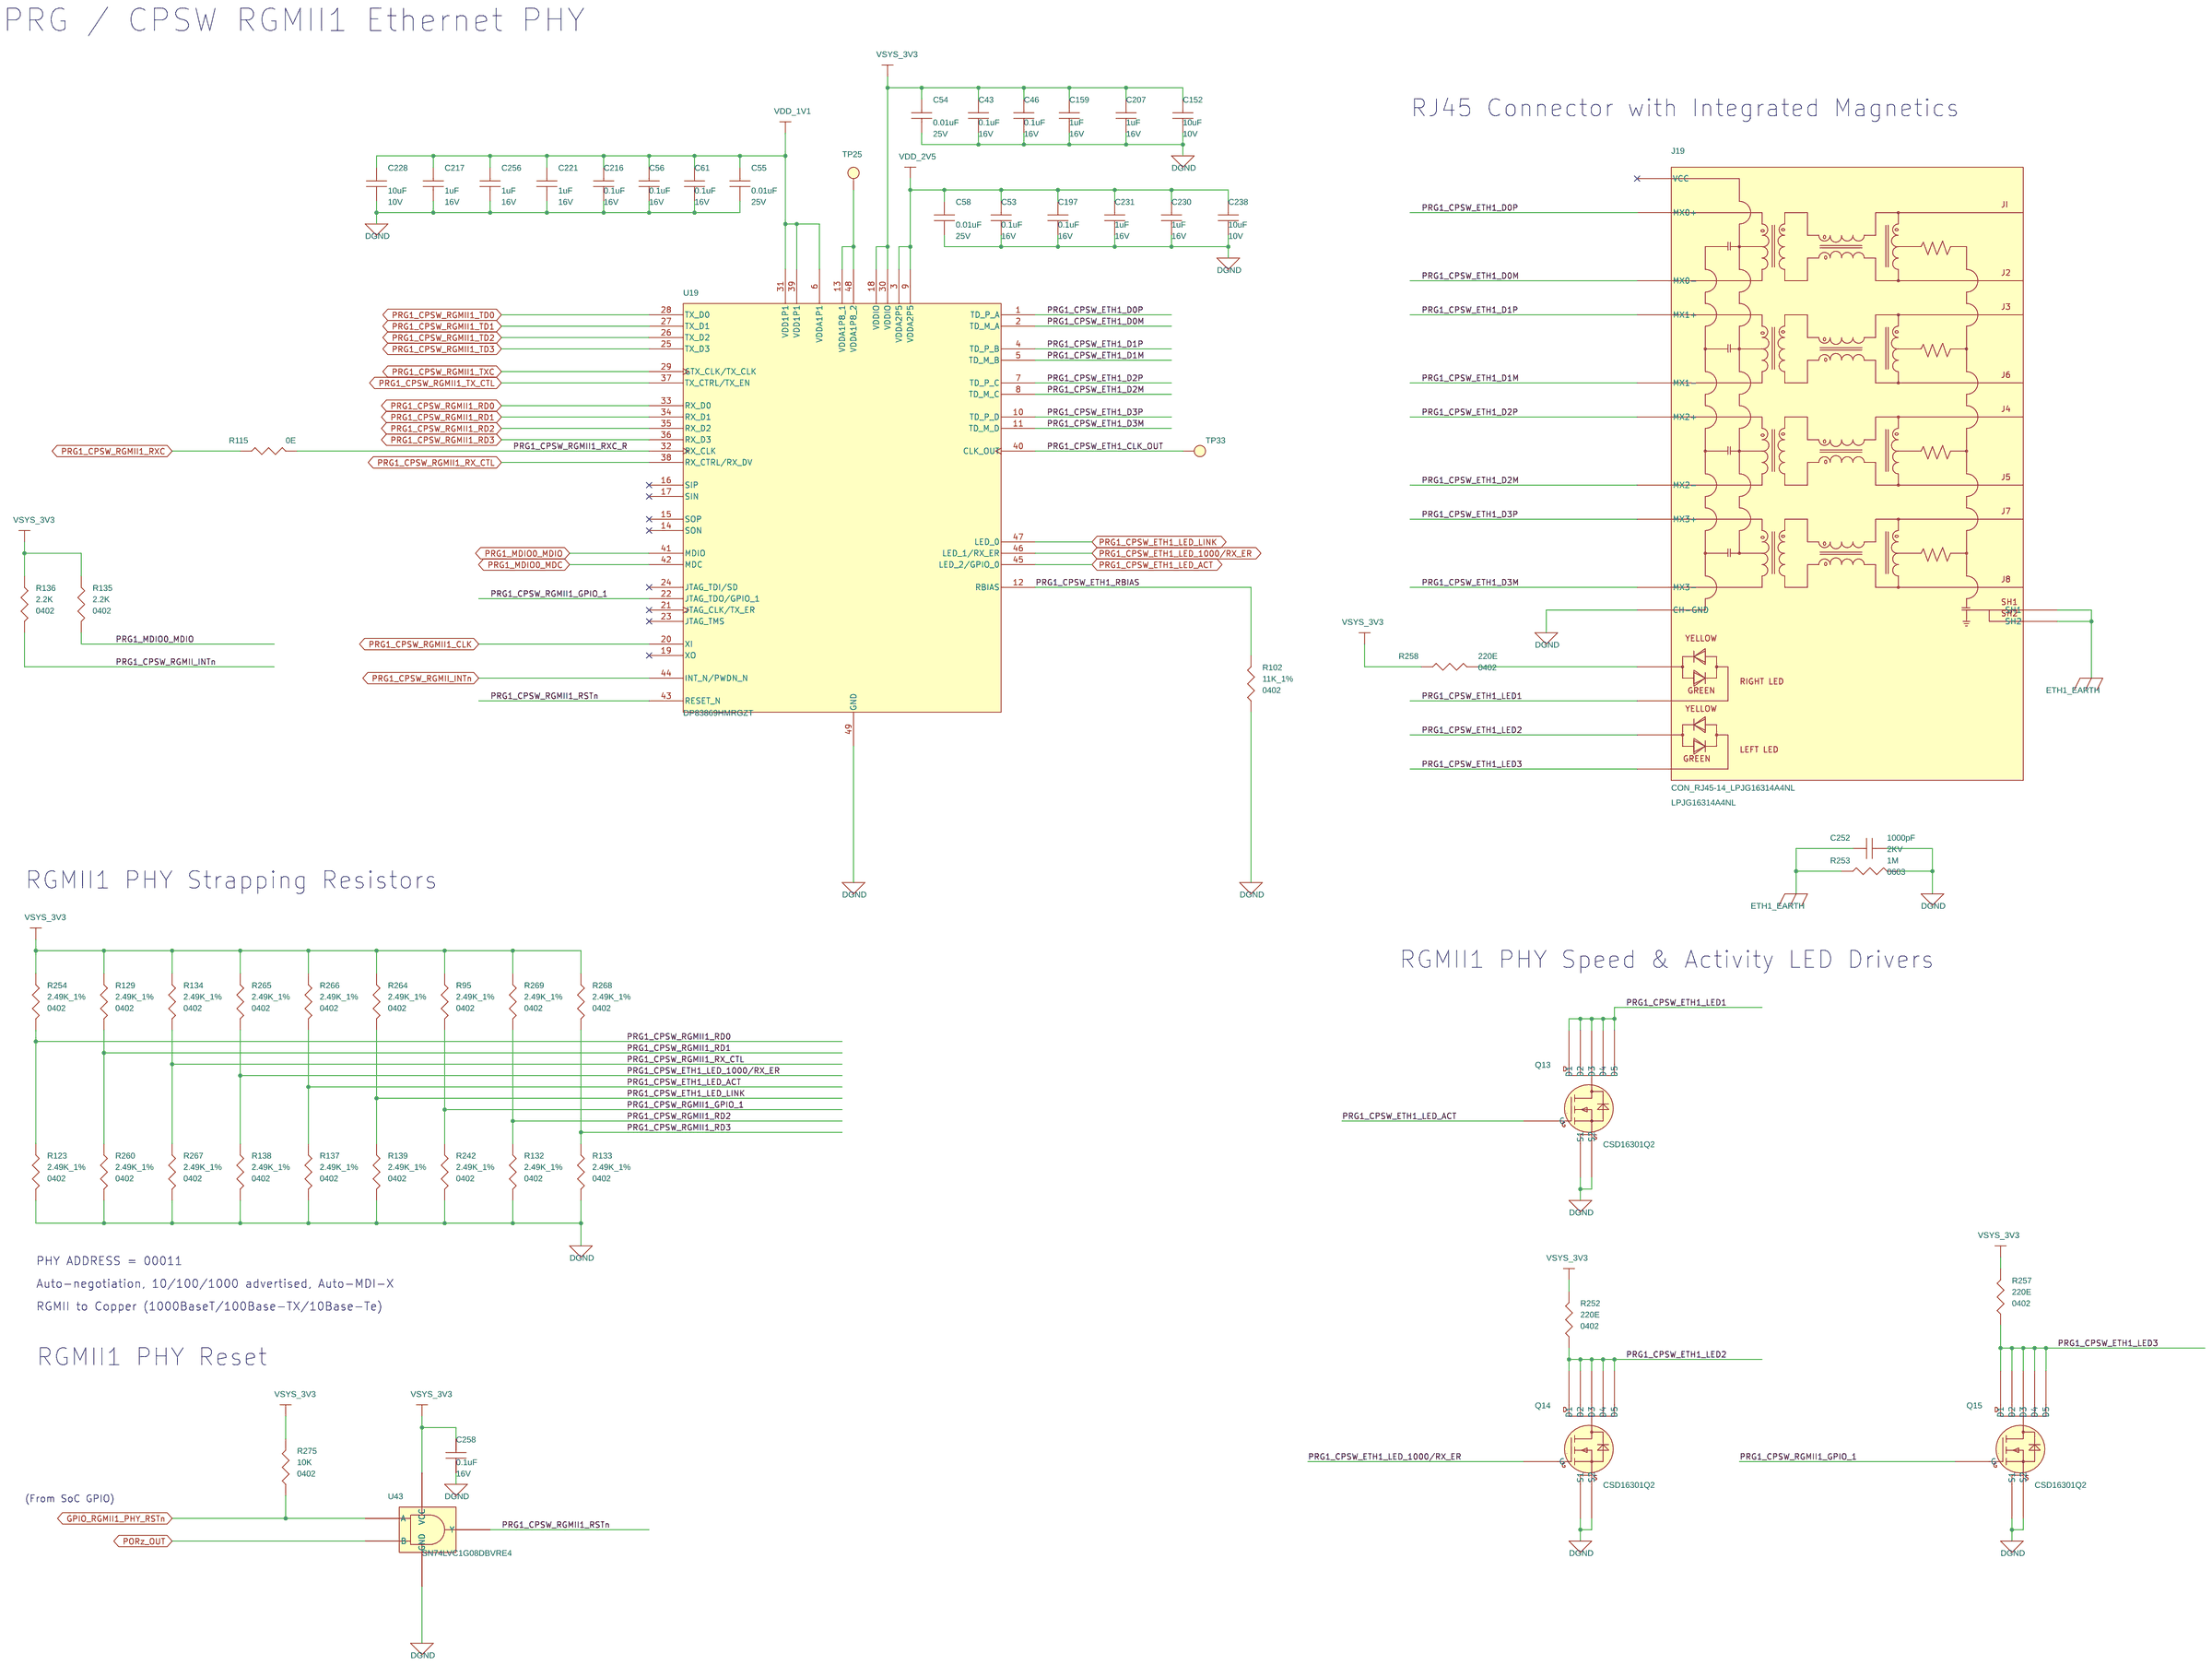
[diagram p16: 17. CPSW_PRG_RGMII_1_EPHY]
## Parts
sheet 15. SOC_QSPI_BOARD_ID_EEPROM
C10  4.7uF  [CAP0402_0-75]
C12  0.1uF  [CAP0201_0-5]
C41  0.1uF  [CAP0201_0-5]
C94  0.1uF  [CAP0201_0-5]
R5  10K  [RES0402_0-5]
R10  10K  [RES0402_0-5]
R36  10K  [RES0402_0-5]
R37  10K  [RES0402_0-5]
R54  100K_1%  [RES0402_0-5]
R63  0E  [RES0402_0-5]
R65  0E  [RES0402_0-5]
R89  10K  [RES0402_0-5]
R121  10K  [RES0402_0-5]
R122  10K  [RES0402_0-5]
R179  0E  [RES0402_0-5]
R180  0E  [RES0402_0-5]
R181  10K  [RES0402_0-5]
R183  10K  [RES0402_0-5]
R213  0E  [RES0402_0-5]
U2  S25HL512TFAMHI010  [SOIC16_W_2-7]
U17  AT24CM01  [TSSOP8_25-59_125X180_1-2]
U31  SN74LVC1G08DBVRE4  [SOT23-5]
sheet 16. ETHERNET_MUX_SoC_ADC_IN
C28  100pF  [CAP0402_0-75]
C33  100pF  [CAP0402_0-75]
C35  100pF  [CAP0402_0-75]
C36  100pF  [CAP0402_0-75]
C108  100pF  [CAP0402_0-75]
C110  100pF  [CAP0402_0-75]
C117  100pF  [CAP0402_0-75]
C118  100pF  [CAP0402_0-75]
C166  0.1uF  [CAP0201_0-5]
C209  0.1uF  [CAP0201_0-5]
C248  0.1uF  [CAP0201_0-5]
R142  3.48K_1%  [RES0402_0-5]
R143  2.94K_1%  [RES0402_0-5]
R144  2.94K_1%  [RES0402_0-5]
R145  3.48K_1%  [RES0402_0-5]
R146  2.94K_1%  [RES0402_0-5]
R147  3.48K_1%  [RES0402_0-5]
R148  2.94K_1%  [RES0402_0-5]
R149  3.48K_1%  [RES0402_0-5]
R150  2.94K_1%  [RES0402_0-5]
R151  3.48K_1%  [RES0402_0-5]
R152  2.94K_1%  [RES0402_0-5]
R153  3.48K_1%  [RES0402_0-5]
R154  2.94K_1%  [RES0402_0-5]
R155  3.48K_1%  [RES0402_0-5]
R156  2.94K_1%  [RES0402_0-5]
R157  3.48K_1%  [RES0402_0-5]
R250  10K  [RES0402_0-5]
R594  0E  [RES0402_0-5]
R595  0E  [RES0402_0-5]
R596  0E  [RES0402_0-5]
R597  0E  [RES0402_0-5]
U40  TS3DDR3812RUAR  [TQFN42_19-68_140X360_0-8]
sheet 17. CPSW_PRG_RGMII_1_EPHY
C43  0.1uF  [CAP0201_0-5]
C46  0.1uF  [CAP0201_0-5]
C53  0.1uF  [CAP0201_0-5]
C54  0.01uF  [CAP0201_0-5]
C55  0.01uF  [CAP0201_0-5]
C56  0.1uF  [CAP0201_0-5]
C58  0.01uF  [CAP0201_0-5]
C61  0.1uF  [CAP0201_0-5]
C152  10uF  [CAP0402_0-75]
C159  1uF  [CAP0201_0-5]
C197  0.1uF  [CAP0201_0-5]
C207  1uF  [CAP0201_0-5]
C216  0.1uF  [CAP0201_0-5]
C217  1uF  [CAP0201_0-5]
C221  1uF  [CAP0201_0-5]
C228  10uF  [CAP0402_0-75]
C230  1uF  [CAP0201_0-5]
C231  1uF  [CAP0201_0-5]
C238  10uF  [CAP0402_0-75]
C252  1000pF  [CAP1210_1-5]
C256  1uF  [CAP0201_0-5]
C258  0.1uF  [CAP0201_0-5]
J19  CON_RJ45-14_LPJG16314A4NL  [CON_RJ45-14_LPJG16314A4NL_S_R_T_13-6]
Q13  CSD16301Q2  [WSON6_CSD13202Q2_80X80_0-8]
Q14  CSD16301Q2  [WSON6_CSD13202Q2_80X80_0-8]
Q15  CSD16301Q2  [WSON6_CSD13202Q2_80X80_0-8]
R95  2.49K_1%  [RES0402_0-5]
R102  11K_1%  [RES0402_0-5]
R115  0E  [RES0402_0-5]
R123  2.49K_1%  [RES0402_0-5]
R129  2.49K_1%  [RES0402_0-5]
R132  2.49K_1%  [RES0402_0-5]
R133  2.49K_1%  [RES0402_0-5]
R134  2.49K_1%  [RES0402_0-5]
R135  2.2K  [RES0402_0-5]
R136  2.2K  [RES0402_0-5]
R137  2.49K_1%  [RES0402_0-5]
R138  2.49K_1%  [RES0402_0-5]
R139  2.49K_1%  [RES0402_0-5]
R242  2.49K_1%  [RES0402_0-5]
R252  220E  [RES0402_0-5]
R253  1M  [RES0603_0-75]
R254  2.49K_1%  [RES0402_0-5]
R257  220E  [RES0402_0-5]
R258  220E  [RES0402_0-5]
R260  2.49K_1%  [RES0402_0-5]
R264  2.49K_1%  [RES0402_0-5]
R265  2.49K_1%  [RES0402_0-5]
R266  2.49K_1%  [RES0402_0-5]
R267  2.49K_1%  [RES0402_0-5]
R268  2.49K_1%  [RES0402_0-5]
R269  2.49K_1%  [RES0402_0-5]
R275  10K  [RES0402_0-5]
TP25  TP20_SMD  [TP20_SMD]
TP33  TP20_SMD  [TP20_SMD]
U19  DP83869HMRGZT  [QFN48_19-68_280X280_1_EP4-2]
U43  SN74LVC1G08DBVRE4  [SOT23-5]
sheet 24. SOC_DIGITAL_POWER_DECAPs
U18  AM2434BSFFHIALX  [BGA293_19-68_440X440_1]  (sections A,B,C,D,E,F,G,H,I,J,K,L,M)

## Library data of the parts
C10 = CAP: CAP CERAMIC 4.7uF 10V 20% X5R 0402; Chkd/date: MANIRAJA/110718; Crtd /date: ALVY/110718; Custom_Duty: 15%; Customs_HS_Code: 85322990; Distributor_name: DIGIKEY; Distributor_part_number: 490-14306-1-ND; Footprint Path: Y:\MIS_DATABASE\Library\ALTIUM_TOOL\PCB_FOOTPRINTS\Altium_Footprint_Lib.PcbLib; Height: 0.65MM; Library Path: Y:\MIS_DATABASE\Library\ALTIUM_TOOL\SCHEMATICS_PARTS\MS_DISCRETE_Library.schlib; Mfr_name: MURATA; Mfr_part_number: GRM155R61A475MEAAD; Mistral Part No: 120012060002-R; Package: 0402; Part_type: CAPACITORS\CERAMIC; Project: TI_J7SVB_PCIE_ADD-ON-CARD; RoHS: RoHS; Temperature: -55°C+85°C; Tolerance: 20%; Voltage: 10V; Wattage: NA; Weight: 14mg; Datasheet: Y:\MIS_DATABASE\DATASHEETS\CAPACITORS\GRM155R61A475MEAAD.PDF
C12 C41 C94 C166 C209 C248 = CAP: CAP CERAMIC 0.1uF 16V 10% X5R 0201; Chkd/date: MANIRAJA/230118; Crtd /date: MANIRAJA/230118; Custom_Duty: 15%; Customs_HS_Code: 85322990; Distributor_name: DIGIKEY; Distributor_part_number: 490-14305-1-ND; Footprint Path: Y:\MIS_DATABASE\Library\ALTIUM_TOOL\PCB_FOOTPRINTS\Altium_Footprint_Lib.PcbLib; Height: 0.33MM; Library Path: Y:\MIS_DATABASE\Library\ALTIUM_TOOL\SCHEMATICS_PARTS\MS_DISCRETE_Library.schlib; Mfr_name: MURATA; Mfr_part_number: GRM033R61C104KE14D; Mistral Part No: 120009030072-R; Package: 0201; Part_type: CAPACITORS\CERAMIC; Project: TI_MAXIE_CPB; RoHS: RoHS; Temperature: -55°C+85°C; Tolerance: 10%; Voltage: 16V; Wattage: NA; Weight: 0.33mg; Datasheet: Y:\MIS_DATABASE\DATASHEETS\CAPACITORS\GRM033R61C104KE14.PDF
R5 R10 R36 R37 R89 R121 R122 R181 R183 R250 R275 = RESISTOR: RES 10K 1/16W 5% 0402; Chkd/date: VASANTHA/061216; Crtd /date: MAZHAR/230805; Custom_Duty: 15%; Customs_HS_Code: 85332119; Distributor_name: DIGIKEY; Distributor_part_number: 311-10KJRCT-ND; Footprint Path: Y:\MIS_DATABASE\Library\ALTIUM_TOOL\PCB_FOOTPRINTS\Altium_Footprint_Lib.PcbLib; Height: 0.40MM; Library Path: Y:\MIS_DATABASE\Library\ALTIUM_TOOL\SCHEMATICS_PARTS\MS_DISCRETE_Library.schlib; Mfr_name: YAGEO AMERICA; Mfr_part_number: RC0402JR-0710KL; Mistral Part No: 110011060021-R; Package: 0402; Part_type: RESISTORS\FIXED; Project: HSE; RoHS: RoHS; Temperature: -55°C+155°C; Tolerance: 5%; Voltage: NA; Wattage: 1/16W; Weight: 0.65mg; Datasheet: Y:\MIS_DATABASE\DATASHEETS\RESISTORS\RCXXXXL-SER_MAR18.PDF
R54 = RESISTOR: RES 100K 1/16W 1% 0402; Chkd/date: MANIRAJA/110917; Crtd /date: MANIRAJA/110917; Custom_Duty: 15%; Customs_HS_Code: 85332119; Distributor_name: DIGIKEY; Distributor_part_number: 311-100KLRCT-ND; Footprint Path: Y:\MIS_DATABASE\Library\ALTIUM_TOOL\PCB_FOOTPRINTS\Altium_Footprint_Lib.PcbLib; Height: 0.40MM; Library Path: Y:\MIS_DATABASE\Library\ALTIUM_TOOL\SCHEMATICS_PARTS\MS_DISCRETE_Library.schlib; Mfr_name: YAGEO AMERICA; Mfr_part_number: RC0402FR-07100KL; Mistral Part No: 110014060043-R; Package: 0402; Part_type: RESISTORS\FIXED; Project: CRADE RF CARD; RoHS: RoHS; Temperature: -55°C+155°C; Tolerance: 1%; Voltage: NA; Wattage: 1/16W; Weight: 0.65mg; Datasheet: Y:\MIS_DATABASE\DATASHEETS\RESISTORS\RCXXXXL-SER_MAR18.PDF
R63 R115 = RESISTOR: RES 0E 1/16W 5% 0402; Chkd/date: VASANTHA/291216; Crtd /date: CHAITHANYA/300911; Custom_Duty: 15%; Customs_HS_Code: 85332119; Distributor_name: DIGIKEY; Distributor_part_number: 311-0.0JRCT-ND; Footprint Path: Y:\MIS_DATABASE\Library\ALTIUM_TOOL\PCB_FOOTPRINTS\Altium_Footprint_Lib.PcbLib; Height: 0.40MM; Library Path: Y:\MIS_DATABASE\Library\ALTIUM_TOOL\SCHEMATICS_PARTS\MS_DISCRETE_Library.schlib; Mfr_name: YAGEO AMERICA; Mfr_part_number: RC0402JR-070RL; Mistral Part No: 110011090036-R; Package: 0402; Part_type: RESISTORS\FIXED; Project: VP-4000-PROCESSOR; RoHS: RoHS; SIGNAL_MODEL: RESISTOR_RES0402_0-5_0E_0E; Temperature: -55°C+155°C; Tolerance: 5%; Voltage: NA; Wattage: 1/16W; Weight: 0.65mg; Datasheet: Y:\MIS_DATABASE\DATASHEETS\RESISTORS\RCXXXXL-SER_MAR18.PDF
R65 R179 R180 R213 R594-R597 = RESISTOR: RES 0E 1/16W 5% 0402; Chkd/date: VASANTHA/291216; Crtd /date: CHAITHANYA/300911; Custom_Duty: 15%; Customs_HS_Code: 85332119; Distributor_name: DIGIKEY; Distributor_part_number: 311-0.0JRCT-ND; Footprint Path: Y:\MIS_DATABASE\Library\ALTIUM_TOOL\PCB_FOOTPRINTS\Altium_Footprint_Lib.PcbLib; Height: 0.40MM; Library Path: Y:\MIS_DATABASE\Library\ALTIUM_TOOL\SCHEMATICS_PARTS\MS_DISCRETE_Library.schlib; Mfr_name: YAGEO AMERICA; Mfr_part_number: RC0402JR-070RL; Mistral Part No: 110011090036-R; Package: 0402; Part_type: RESISTORS\FIXED; Project: VP-4000-PROCESSOR; RoHS: RoHS; Temperature: -55°C+155°C; Tolerance: 5%; Voltage: NA; Wattage: 1/16W; Weight: 0.65mg; Datasheet: Y:\MIS_DATABASE\DATASHEETS\RESISTORS\RCXXXXL-SER_MAR18.PDF
U2 = S25HL512TFAMHI01_SOIC16: IC 3V 512MB QUAD SPI SEMPER FLASH MEMORY SOIC16; Chkd/date: MANIRAJA/231120; Crtd /date: ALVY/201120; Custom_Duty: 15%; Customs_HS_Code: 85423100; Distributor_name: DIGIKEY; Distributor_part_number: 428-S25HL512TFAMHI010-ND; Footprint Path: Y:\MIS_DATABASE\Library\ALTIUM_TOOL\PCB_FOOTPRINTS\Altium_Footprint_Lib.PcbLib; Height: 2.65MM; Library Path: Y:\MIS_DATABASE\Library\ALTIUM_TOOL\SCHEMATICS_PARTS\MS_MISCMEMORY_Library.schlib; Mfr_name: CYPRESS; Mistral Part No: 141120110006-R; Package: SOIC16; Part_type: ICS\DIGITAL\MEMORY; Project: TI_AM243x LP EVM; RoHS: RoHS; Temperature: -40°C+85°C; Tolerance: NA; Voltage: NA; Wattage: NA; Weight: NA; Datasheet: Y:\MIS_DATABASE\DATASHEETS\ICS\MEMORY\S25HXXXXT.PDF
U17 = AT24HC04B-TH-B_TSSOP8: IC 1MBIT I2C SERIAL EEPROM TSSOP8; Chkd/date: NAVEED/241114; Crtd /date: VASANTHA/230914; Custom_Duty: 15%; Customs_HS_Code: 85423100; Distributor_name: DIGIKEY; Distributor_part_number: AT24CM01-XHD-TCT-ND; Height: 1.20MM; Mfr_name: ATMEL; Mfr_part_number: AT24CM01-XHD-T; Mistral Part No: 141114090006-R; Package: TSSOP8; Part_type: ICS\DIGITAL\MEMORY; Project: GALILEO_EVM; RoHS: RoHS; Temperature: -40°C+85°C; Tolerance: NA; Voltage: NA; Wattage: NA; Weight: 158mg; Datasheet: Y:\MIS_DATABASE\DATASHEETS\ICS\MEMORY\AT24CM01.PDF
U31 = SN74LVC1G08DBVRE4_SOT23-5: IC SINGLE 2-INPUT POSITIVE AND GATE SOT23-5; Automotive Alternate_mfr_name: TEXAS INSTRUMENTS; Automotive Alternate_mfr_part_number: SN74LVC1G08QDBVRQ1; Chkd/date: SUHAS/221010; Crtd /date: USMAN/151008; Custom_Duty: 15%; Customs_HS_Code: 85423100; Distributor_name: DIGIKEY; Distributor_part_number: SN74LVC1G08DBVRE4-ND; Height: 1.45MM; Mfr_name: TEXAS INSTRUMENTS; Mistral Part No: 141009060026-R; Part_type: ICS\DIGITAL\GATES; Project: KHAN_MAIN; RoHS: Sb/ Br FREE; Temperature: -40°C+85°C; Datasheet: Y:\MIS_DATABASE\DATASHEETS\ICS\DIGITAL\GATES\SN74LVC1G08.PDF
C28 C33 C35 C36 C108 C110 C117 C118 = CAP: CAP CERAMIC 100pF 50V 1% C0G(NP0) AUTO 0402; Chkd/date: MANIRAJA/240521; Crtd /date: ALVY/210521; Custom_Duty: 15%; Customs_HS_Code: 85322990; Distributor_name: MOUSER; Distributor_part_number: 81-GRT1555C1H101FA2D; Footprint Path: Y:\MIS_DATABASE\Library\ALTIUM_TOOL\PCB_FOOTPRINTS\Altium_Footprint_Lib.PcbLib; Height: 0.55MM; Library Path: Y:\MIS_DATABASE\Library\ALTIUM_TOOL\SCHEMATICS_PARTS\MS_DISCRETE_Library.schlib; Mfr_name: MURATA; Mfr_part_number: GRT1555C1H101FA02D; Mistral Part No: 120019080008-R; Package: 0402; Part_type: CAPACITORS\CERAMIC; Project: AM243x_LP_BRD; RoHS: RoHS; Temperature: -55°C+125°C; Tolerance: 1%; Voltage: 50V; Wattage: NA; Weight: 1.6mg; Datasheet: Y:\MIS_DATABASE\DATASHEETS\CAPACITORS\GRT1555C1H101FA02.PDF
R142 R145 R147 R149 R151 R153 R155 R157 = RESISTOR: RES 3.48K 1/16W 1% 0402; Chkd/date: ALVY/091220; Crtd /date: MANIRAJA/091220; Custom_Duty: 15%; Customs_HS_Code: 85332119; Distributor_name: DIGIKEY; Distributor_part_number: YAG3148CT-ND; Footprint Path: Y:\MIS_DATABASE\Library\ALTIUM_TOOL\PCB_FOOTPRINTS\Altium_Footprint_Lib.PcbLib; Height: 0.40MM; Library Path: Y:\MIS_DATABASE\Library\ALTIUM_TOOL\SCHEMATICS_PARTS\MS_DISCRETE_Library.schlib; Mfr_name: YAGEO AMERICA; Mfr_part_number: RC0402FR-073K48L; Mistral Part No: 110019120035-R; Package: 0402; Part_type: RESISTORS\FIXED; Project: TI_AM243x LP EVM; RoHS: RoHS; Temperature: -55°C+155°C; Tolerance: 1%; Voltage: NA; Wattage: 1/16W; Weight: 0.65mg; Datasheet: Y:\MIS_DATABASE\DATASHEETS\RESISTORS\RCXXXXL-SER_MAR18.PDF
R143 R144 R146 R148 R150 R152 R154 R156 = RESISTOR: RES 2.94K 1/10W 1% 0402; Chkd/date: MANIRAJA/080319; Crtd /date: MANIRAJA/080319; Custom_Duty: 15%; Customs_HS_Code: 85332119; Distributor_name: DIGIKEY; Distributor_part_number: P2.94KLCT-ND; Footprint Path: Y:\MIS_DATABASE\Library\ALTIUM_TOOL\PCB_FOOTPRINTS\Altium_Footprint_Lib.PcbLib; Height: 0.40MM; Library Path: Y:\MIS_DATABASE\Library\ALTIUM_TOOL\SCHEMATICS_PARTS\MS_DISCRETE_Library.schlib; Mfr_name: PANASONIC-ECG; Mfr_part_number: ERJ-2RKF2941X; Mistral Part No: 110009030460-R; Package: 0402; Part_type: RESISTORS\FIXED; Project: TELEMETRY ENCODER; RoHS: RoHS; Temperature: -55°C+155°C; Tolerance: 1%; Voltage: NA; Wattage: 1/10W; Weight: 0.8mg; Datasheet: Y:\MIS_DATABASE\DATASHEETS\RESISTORS\PAN-ERJSER_NOV17.PDF
U40 = TS3DDR3812RUAR_WQFN42: IC 12-CH 1:2 MUX/DEMUX SWITCH FOR DDR3 APPLICATION WQFN42; Chkd/date: MANIRAJA/250918; Crtd /date: ALVY/250918; Custom_Duty: 15%; Customs_HS_Code: 85423100; Distributor_name: DIGIKEY; Distributor_part_number: 296-28307-1-ND; Footprint Path: Y:\MIS_DATABASE\Library\ALTIUM_TOOL\PCB_FOOTPRINTS\Altium_Footprint_Lib.PcbLib; Height: 0.80MM; Library Path: Y:\MIS_DATABASE\Library\ALTIUM_TOOL\SCHEMATICS_PARTS\MS_COMBINATIONAL_Library.schlib; Mfr_name: TEXAS INSTRUMENTS; Mistral Part No: 141018090023-R; Package: WQFN42; Part_type: ICS\DIGITAL\COMBINATIONAL; Project: TI_J7ES_EVM_CP; RoHS: RoHS; Temperature: -40°C+85°C; Tolerance: NA; Voltage: NA; Wattage: NA; Weight: 54.8mg; Datasheet: Y:\MIS_DATABASE\DATASHEETS\ICS\DIGITAL\COMBINATIONAL\TS3DDR3812.PDF
C43 C46 C53 C56 C61 C197 C216 C258 = CAP: CAP CERAMIC 0.1uF 16V 10% X5R 0201; Alt_Mfr_name: YAGEO AMERICA; Alt_Mfr_part_number: CC0402KRX5R8BB104; Chkd/date: MANIRAJA/230118; Crtd /date: MANIRAJA/230118; Custom_Duty: 15%; Customs_HS_Code: 85322990; Distributor_name: DIGIKEY; Distributor_part_number: 490-14305-1-ND; Footprint Path: Y:\MIS_DATABASE\Library\ALTIUM_TOOL\PCB_FOOTPRINTS\Altium_Footprint_Lib.PcbLib; Height: 0.33MM; Library Path: Y:\MIS_DATABASE\Library\ALTIUM_TOOL\SCHEMATICS_PARTS\MS_DISCRETE_Library.schlib; Mfr_name: MURATA; Mfr_part_number: GRM033R61C104KE14D; Mistral Part No: 120009030072-R; Package: 0201; Part_type: CAPACITORS\CERAMIC; Project: TI_MAXIE_CPB; RoHS: RoHS; Temperature: -55°C+85°C; Tolerance: 10%; Voltage: 16V; Wattage: NA; Weight: 0.33mg; Datasheet: Y:\MIS_DATABASE\DATASHEETS\CAPACITORS\GRM033R61C104KE14.PDF
C54 C55 C58 = CAP: CAP CERAMIC 0.01uF 25V 10% X7R 0201; Chkd/date: MANIRAJA/080519; Crtd /date: ALVY/080519; Custom_Duty: 15%; Customs_HS_Code: 85322990; Distributor_name: DIGIKEY; Distributor_part_number: 490-14454-1-ND; Footprint Path: Y:\MIS_DATABASE\Library\ALTIUM_TOOL\PCB_FOOTPRINTS\Altium_Footprint_Lib.PcbLib; Height: 0.33MM; Library Path: Y:\MIS_DATABASE\Library\ALTIUM_TOOL\SCHEMATICS_PARTS\MS_DISCRETE_Library.schlib; Mfr_name: MURATA; Mfr_part_number: GRM033R71E103KE14D; Mistral Part No: 120019050002-R; Package: 0201; Part_type: CAPACITORS\CERAMIC; Project: BRUKER_SD820_COMMONDO; RoHS: RoHS; Temperature: -55°C+125°C; Tolerance: 10%; Voltage: 25V; Wattage: NA; Weight: 0.33mg; Datasheet: Y:\MIS_DATABASE\DATASHEETS\CAPACITORS\GRM033R71E103KE14.PDF
C152 C228 C238 = CAP: CAP CERAMIC 10uF 10V 20% X5R 0402; Chkd/date: MANIRAJA/300520; Crtd /date: ALVY/260520; Custom_Duty: 15%; Customs_HS_Code: 85322990; Distributor_name: DIGIKEY; Distributor_part_number: 490-GRM155R61A106ME11DTR-ND; Footprint Path: Y:\MIS_DATABASE\Library\ALTIUM_TOOL\PCB_FOOTPRINTS\Altium_Footprint_Lib.PcbLib; Height: 0.55MM; Library Path: Y:\MIS_DATABASE\Library\ALTIUM_TOOL\SCHEMATICS_PARTS\MS_DISCRETE_Library.schlib; Mfr_name: MURATA; Mfr_part_number: GRM155R61A106ME11D; Mistral Part No: 120013110019-R; Package: 0402; Part_type: CAPACITORS\CERAMIC; Project: QCS610_NANOSOM; RoHS: RoHS; Temperature: -55°C+85°C; Tolerance: 20%; Voltage: 10V; Wattage: NA; Weight: 3.1mg; Datasheet: Y:\MIS_DATABASE\DATASHEETS\CAPACITORS\MURATA-GXX-SER_NOV17.PDF
C159 C207 C217 C221 C230 C231 C256 = CAP: CAP CERAMIC 1uF 16V 20% X5R 0201; Chkd/date: MANIRAJA/300520; Crtd /date: ALVY/260520; Custom_Duty: 15%; Customs_HS_Code: 85322990; Distributor_name: DIGIKEY; Distributor_part_number: 490-18654-1-ND; Footprint Path: Y:\MIS_DATABASE\Library\ALTIUM_TOOL\PCB_FOOTPRINTS\Altium_Footprint_Lib.PcbLib; Height: 0.39MM; Library Path: Y:\MIS_DATABASE\Library\ALTIUM_TOOL\SCHEMATICS_PARTS\MS_DISCRETE_Library.schlib; Mfr_name: MURATA; Mfr_part_number: GRM033R61C105ME15D; Mistral Part No: 120018090038-R; Package: 0201; Part_type: CAPACITORS\CERAMIC; Project: QCS610_NANOSOM; RoHS: RoHS; Temperature: -55°C+85°C; Tolerance: 20%; Voltage: 16V; Wattage: NA; Weight: 0.33mg; Datasheet: Y:\MIS_DATABASE\DATASHEETS\CAPACITORS\GRM033R61C105ME15.PDF
C252 = CAP: CAP CERAMIC 1000pF 2KV 10% X7R 1210; Chkd/date: ALVY/071220; Crtd /date: MANIRAJA/071220; Custom_Duty: 15%; Customs_HS_Code: 85322990; Distributor_name: DIGIKEY; Distributor_part_number: 732-12130-1-ND; Footprint Path: Y:\MIS_DATABASE\Library\ALTIUM_TOOL\PCB_FOOTPRINTS\Altium_Footprint_Lib.PcbLib; Height: 1.35MM; Library Path: Y:\MIS_DATABASE\Library\ALTIUM_TOOL\SCHEMATICS_PARTS\MS_DISCRETE_Library.schlib; Mfr_name: WURTH ELEKTRONIK; Mfr_part_number: 885342209009; Mistral Part No: 120020120008-R; Package: 1210; Part_type: CAPACITORS\CERAMIC; Project: TI_AM243x LP EVM; RoHS: RoHS; Temperature: -55°C+125°C; Tolerance: 10%; Voltage: 2KV; Wattage: NA; Weight: 19.234mg; Datasheet: Y:\MIS_DATABASE\DATASHEETS\CAPACITORS\885342209009.PDF
J19 = CON_RJ45-14_LPJG16314A4NL: CON RJ-45 FEMALE 14POS RT TH; Chkd/date: VASANTHA/150714; Crtd /date: BALACHANDAR/120614; Custom_Duty: 24%; Customs_HS_Code: 85369090; Distributor_name: NA; Distributor_part_number: NA; Footprint Path: Y:\MIS_DATABASE\Library\ALTIUM_TOOL\PCB_FOOTPRINTS\Altium_Footprint_Lib.PcbLib; Height: 13.60MM; Library Path: Y:\MIS_DATABASE\Library\ALTIUM_TOOL\SCHEMATICS_PARTS\MS_CONNECTOR_Library.schlib; Mfr_name: LINK-PP; Mfr_part_number: LPJG16314A4NL; Mistral Part No: 150014060029-R; Package: THRU-HOLE; Part_type: CONNECTOR\JACK; Project: AEGIS; RoHS: RoHS; Temperature: -0°C+70°C; Tolerance: NA; Voltage: NA; Wattage: NA; Weight: NA; Datasheet: Y:\MIS_DATABASE\DATASHEETS\CONNECTORS\LPJG16314A4NL.PDF
Q13-Q15 = MOSFET_CSD17313Q2: IC MOSFET N-CHANNEL NEXFET 25V WSON6; Chkd/date: ALVY/071220; Crtd /date: MANIRAJA/071220; Custom_Duty: 15%; Customs_HS_Code: 85423100; Distributor_name: DIGIKEY; Distributor_part_number: 296-25260-1-ND; Footprint Path: Y:\MIS_DATABASE\Library\ALTIUM_TOOL\PCB_FOOTPRINTS\Altium_Footprint_Lib.PcbLib; Height: 0.80MM; Library Path: Y:\MIS_DATABASE\Library\ALTIUM_TOOL\SCHEMATICS_PARTS\MS_MOSFET_Library.schlib; Mfr_name: TEXAS INSTRUMENTS; Mistral Part No: 142020120008-R; Package: WSON6; Part_type: ICS\POWER\MOSFET; Project: TI_AM243x LP EVM; RoHS: RoHS; Temperature: -55°C+150°C; Tolerance: NA; Voltage: NA; Wattage: NA; Weight: 8.7mg; Datasheet: Y:\MIS_DATABASE\DATASHEETS\ICS\POWER\CSD16301Q2.PDF
R95 R123 R129 R132-R134 R137-R139 R242 R254 R260 R264-R269 = RESISTOR: RES 2.49K 1/16W 1% 0402; Chkd/date: VASANTHA/270516; Crtd /date: VASANTHA/270516; Custom_Duty: 15%; Customs_HS_Code: 85332119; Distributor_name: DIGIKEY; Distributor_part_number: 311-2.49KLRCT-ND; Footprint Path: Y:\MIS_DATABASE\Library\ALTIUM_TOOL\PCB_FOOTPRINTS\Altium_Footprint_Lib.PcbLib; Height: 0.40MM; Library Path: Y:\MIS_DATABASE\Library\ALTIUM_TOOL\SCHEMATICS_PARTS\MS_DISCRETE_Library.schlib; Mfr_name: YAGEO AMERICA; Mfr_part_number: RC0402FR-072K49L; Mistral Part No: 110016050020-R; Package: 0402; Part_type: RESISTORS\FIXED; Project: TMDXCSKCC; RoHS: RoHS; Temperature: -55°C+155°C; Tolerance: 1%; Voltage: NA; Wattage: 1/16W; Weight: 0.65mg; Datasheet: Y:\MIS_DATABASE\DATASHEETS\RESISTORS\RCXXXXL-SER_MAR18.PDF
R102 = RESISTOR: RES 11K 1/16W 1% 0402; Chkd/date: VASANTHA/251115; Crtd /date: VASANTHA/251115; Custom_Duty: 15%; Customs_HS_Code: 85332119; Distributor_name: DIGIKEY; Distributor_part_number: 311-11.0KLRCT-ND; Footprint Path: Y:\MIS_DATABASE\Library\ALTIUM_TOOL\PCB_FOOTPRINTS\Altium_Footprint_Lib.PcbLib; Height: 0.40MM; Library Path: Y:\MIS_DATABASE\Library\ALTIUM_TOOL\SCHEMATICS_PARTS\MS_DISCRETE_Library.schlib; Mfr_name: YAGEO AMERICA; Mfr_part_number: RC0402FR-0711KL; Mistral Part No: 110015110012-R; Package: 0402; Part_type: RESISTORS\FIXED; Project: TI_VLAN_SWITCH; RoHS: RoHS; Temperature: -55°C+155°C; Tolerance: 1%; Voltage: NA; Wattage: 1/16W; Weight: 0.65mg; Datasheet: Y:\MIS_DATABASE\DATASHEETS\RESISTORS\RCXXXXL-SER_MAR18.PDF
R135 R136 = RESISTOR: RES 2.2K 1/16W 5% 0402; Chkd/date: VASANTHA/061216; Crtd /date: BAVISH/021210; Custom_Duty: 15%; Customs_HS_Code: 85332119; Distributor_name: DIGIKEY; Distributor_part_number: 311-2.2KJRCT-ND; Footprint Path: Y:\MIS_DATABASE\Library\ALTIUM_TOOL\PCB_FOOTPRINTS\Altium_Footprint_Lib.PcbLib; Height: 0.40MM; Library Path: Y:\MIS_DATABASE\Library\ALTIUM_TOOL\SCHEMATICS_PARTS\MS_DISCRETE_Library.schlib; Mfr_name: YAGEO AMERICA; Mfr_part_number: RC0402JR-072K2L; Mistral Part No: 110010120018-R; Package: 0402; Part_type: RESISTORS\FIXED; Project: TE4; RoHS: RoHS; Temperature: -55°C+155°C; Tolerance: 5%; Voltage: NA; Wattage: 1/16W; Weight: 0.65mg; Datasheet: Y:\MIS_DATABASE\DATASHEETS\RESISTORS\RCXXXXL-SER_MAR18.PDF
R252 R257 R258 = RESISTOR: RES 220E 1/16W 5% 0402; Chkd/date: ALVY/091220; Crtd /date: MANIRAJA/091220; Custom_Duty: 15%; Customs_HS_Code: 85332119; Distributor_name: DIGIKEY; Distributor_part_number: 311-220JRCT-ND; Footprint Path: Y:\MIS_DATABASE\Library\ALTIUM_TOOL\PCB_FOOTPRINTS\Altium_Footprint_Lib.PcbLib; Height: 0.40MM; Library Path: Y:\MIS_DATABASE\Library\ALTIUM_TOOL\SCHEMATICS_PARTS\MS_DISCRETE_Library.schlib; Mfr_name: YAGEO AMERICA; Mfr_part_number: RC0402JR-07220RL; Mistral Part No: 110020120013-R; Package: 0402; Part_type: RESISTORS\FIXED; Project: TI_AM243x LP EVM; RoHS: RoHS; Temperature: -55°C+155°C; Tolerance: 5%; Voltage: NA; Wattage: 1/16W; Weight: 0.65mg; Datasheet: Y:\MIS_DATABASE\DATASHEETS\RESISTORS\RCXXXXL-SER_MAR18.PDF
R253 = RESISTOR: RES 1M 1/10W 5% 0603; Chkd/date: ALVY/091220; Crtd /date: MANIRAJA/091220; Custom_Duty: 15%; Customs_HS_Code: 85332119; Distributor_name: DIGIKEY; Distributor_part_number: 311-1.0MGRCT-ND; Footprint Path: Y:\MIS_DATABASE\Library\ALTIUM_TOOL\PCB_FOOTPRINTS\Altium_Footprint_Lib.PcbLib; Height: 0.55MM; Library Path: Y:\MIS_DATABASE\Library\ALTIUM_TOOL\SCHEMATICS_PARTS\MS_DISCRETE_Library.schlib; Mfr_name: YAGEO AMERICA; Mfr_part_number: RC0603JR-071ML; Mistral Part No: 110009030413-R; Package: 0603; Part_type: RESISTORS\FIXED; Project: TI_AM243x LP EVM; RoHS: RoHS; Temperature: -55°C+155°C; Tolerance: 5%; Voltage: NA; Wattage: 1/10W; Weight: 2mg; Datasheet: Y:\MIS_DATABASE\DATASHEETS\RESISTORS\RCXXXXL-SER_MAR18.PDF
TP25 TP33 = TESTPOINT: TESTPOINT CIR 20 SMD; Chkd/date: SHREESHAIL/171006; Crtd /date: MAZHAR/171006; Custom_Duty: NA; Customs_HS_Code: NA; Distributor_name: NA; Distributor_part_number: NA; Footprint Path: Y:\MIS_DATABASE\Library\ALTIUM_TOOL\PCB_FOOTPRINTS\Altium_Footprint_Lib.PcbLib; Height: NA; Library Path: Y:\MIS_DATABASE\Library\ALTIUM_TOOL\SCHEMATICS_PARTS\MS_DISCRETE_Library.schlib; MECHANICAL 3D STEP FILE: NA; Mfr_name: LOCAL; Mistral Part No: NA; Package: SMD; Project: BT MODULE_CSRBC04; RoHS: NA; Temperature: NA; Tolerance: NA; Voltage: NA; Wattage: NA; Weight: NA; Datasheet: NA
U19 = DP83869HM_VQFN48: IC ETHERNET TRANSCEIVER 10/100/1000 WITH COPPER AND FIBRE INTERFACE VQFN48; Chkd/date: MANIRAJA/060519; Crtd /date: ALVY/060519; Custom_Duty: 15%; Customs_HS_Code: 85423100; Distributor_name: DIGIKEY; Distributor_part_number: 296-53377-1-ND; Footprint Path: Y:\MIS_DATABASE\Library\ALTIUM_TOOL\PCB_FOOTPRINTS\Altium_Footprint_Lib.PcbLib; Height: 1.00MM; Library Path: Y:\MIS_DATABASE\Library\ALTIUM_TOOL\SCHEMATICS_PARTS\MS_TELECOM_Library.schlib; Mfr_name: TEXAS INSTRUMENTS; Mistral Part No: 143019050002-R; Package: VQFN48; Part_type: ICS\TELECOM\TRANSCEIVER; Project: J7ES_ENET_DP83869HM_EXP; RoHS: RoHS; Temperature: -40°C+125°C; Tolerance: NA; Voltage: NA; Wattage: NA; Weight: NA; Datasheet: Y:\MIS_DATABASE\DATASHEETS\ICS\TELECOM\DP83869HM.PDF
U43 = SN74LVC1G08DBVRE4_SOT23-5: IC SINGLE 2-INPUT POSITIVE AND GATE SOT23-5; Chkd/date: SUHAS/221010; Crtd /date: USMAN/151008; Custom_Duty: 15%; Customs_HS_Code: 85423100; Distributor_name: DIGIKEY; Distributor_part_number: SN74LVC1G08DBVRE4-ND; Height: 1.45MM; Mfr_name: TEXAS INSTRUMENTS; Mistral Part No: 141009060026-R; Part_type: ICS\DIGITAL\GATES; Project: KHAN_MAIN; RoHS: Sb/ Br FREE; Temperature: -40°C+85°C; Datasheet: Y:\MIS_DATABASE\DATASHEETS\ICS\DIGITAL\GATES\SN74LVC1G08.PDF
U18 = AM243X_SOC_LP_EVM_BGA293: IC QUAD CORE R5F- MCU, FCCSP-293; Chkd/date: PRADEEP/130923; Crtd /date: PRADEEP/130923; Custom_Duty: 15%; Customs_HS_Code: 85423100; Distributor_name: NA; Distributor_part_number: NA; Footprint Path: Y:\MIS_DATABASE\Library\ALTIUM_TOOL\PCB_FOOTPRINTS\Altium_Footprint_Lib.PcbLib; Height: 1.00MM; Library Path: Y:\MIS_DATABASE\Library\ALTIUM_TOOL\SCHEMATICS_PARTS\MS_MICROPROCESSOR_Library.schlib; Library Ref: AM243x SoC_LP_EVM_BGA293; Mfr_name: TEXAS INSTRUMENTS; Mistral Part No: 141223090001; Package: BGA293; Part_type: ICS\DIGITAL\MICROPROCESSOR; Project: AM243_LP; RoHS: NA; Temperature: NA; Tolerance: NA; Voltage: NA; Wattage: NA; Weight: NA; Datasheet: Y:\MIS_DATABASE\DATASHEETS\ICS\DIGITAL\MICROCONTROLLER\AM2434.PDF

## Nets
DGND: C10.2 C12.2 C28.2 C33.2 C35.2 C36.2 C41.2 C43.2 C46.2 C53.2 C54.2 C55.2 C56.2 C58.2 C61.2 C94.2 C108.2 C110.2 C117.2 C118.2 C152.2 C159.2 C166.2 C197.2 C207.2 C209.2 C216.2 C217.2 C221.2 C228.2 C230.2 C231.2 C238.2 C248.2 C252.2 C256.2 C258.2 J19.1(CH-GND) Q13.4(S1) Q13.7(S2) Q14.4(S1) Q14.7(S2) Q15.4(S1) Q15.7(S2) R54.2 R102.2 R121.1 R122.1 R123.2 R132.2 R133.2 R137.2 R138.2 R139.2 R142.2 R145.2 R147.2 R149.2 R151.2 R153.2 R155.2 R157.2 R242.2 R250.1 R253.2 R260.2 R267.2 U2.10(VSS) U17.4(GND) U19.49(GND) U31.3(GND) U40.43(GND) U43.3(GND) ; also on sheet 10 11 12 13 14 18 19 20 21 22 23 24 25 26 27 28
VDD_1V1: C55.1 C56.1 C61.1 C216.1 C217.1 C221.1 C228.1 C256.1 U19.6(VDDA1P1) U19.31(VDD1P1) U19.39(VDD1P1) ; also on sheet 18 28
VDD_2V5: C53.1 C58.1 C197.1 C230.1 C231.1 C238.1 U19.3(VDDA2P5) U19.9(VDDA2P5) ; also on sheet 18 28
BP_ADC0_AIN0: R143.1 ; also on sheet 19
BP_ADC0_AIN1: R152.1 ; also on sheet 19
BP_ADC0_AIN2: R144.1 ; also on sheet 19
BP_ADC0_AIN3: R146.1 ; also on sheet 19
BP_ADC0_AIN4: R148.1 ; also on sheet 19
BP_ADC0_AIN5: R150.1 ; also on sheet 19
BP_ADC0_AIN6: R154.1 ; also on sheet 19
BP_ADC0_AIN7: R156.1 ; also on sheet 19
CPSW_RGMII1_RD0: U40.28(C6) ; also on sheet 11
CPSW_RGMII1_RD1: U40.26(C7) ; also on sheet 11
CPSW_RGMII1_RD2: U40.24(C8) ; also on sheet 11
CPSW_RGMII1_RD3: U40.22(C9) ; also on sheet 11
CPSW_RGMII1_RX_CTL: U40.20(C10) ; also on sheet 11
CPSW_RGMII1_RXC: U40.18(C11) ; also on sheet 11
CPSW_RGMII1_TD0: U40.42(C0) ; also on sheet 12
CPSW_RGMII1_TD1: R596.1 R597.1 ; also on sheet 12
CPSW_RGMII1_TD1_MUX: R597.2 U40.40(C1)
CPSW_RGMII1_TD2: U40.37(C2) ; also on sheet 12
CPSW_RGMII1_TD3: U40.35(C3) ; also on sheet 12
CPSW_RGMII1_TX_CTL: R594.1 R595.1 ; also on sheet 12
CPSW_RGMII1_TX_CTL_MUX: R595.2 U40.33(C4)
CPSW_RGMII1_TXC: U40.31(C5) ; also on sheet 12
EEPROM_A1: R121.2 U17.2(A1)
EEPROM_A2: R122.2 U17.3(A2)
EEPROM_WP: R89.1 U17.7(WP)
ETH1_EARTH: C252.1 J19.15(SH1) J19.16(SH2) R253.1
GPIO_OSPI0_RESET_N: R181.1 U18.M20(OSPI0_CSN1) U31.1(A)
GPIO_RGMII1_PHY_RSTn: R275.1 U43.1(A) ; also on sheet 11
MCU_RESETSTATz: R180.1 ; also on sheet 12
OSPI0_CLK: R54.1 R63.2 U2.16(CK)
OSPI0_CLK_R: R63.1 U18.P20(OSPI0_CLK)
OSPI0_CS0_N: R183.1 U2.7(CS#) U18.L20(OSPI0_CSN0)
OSPI0_D0: R36.1 U2.15(DQ0/SI) U18.L19(OSPI0_D0)
OSPI0_D1: R10.1 U2.8(DQ1/SO) U18.N20(OSPI0_D1)
OSPI0_D2: R5.1 U2.9(DQ2/WP#) U18.L21(OSPI0_D2)
OSPI0_D3: R37.1 U2.1(DQ3/RESET#) U18.N19(OSPI0_D3)
OSPI0_DQS: R213.1 U18.P17(OSPI0_DQS)
OSPI0_DQS_R: R65.1 R213.2
OSPI0_LBCLKO: R65.2 U18.M21(OSPI0_LBCLKO)
PORZ_OUT: R179.1 U43.2(B) ; also on sheet 11 12 18 21
PRG1_CPSW_ETH1_CLK_OUT: TP33.1(TP) U19.40(CLK_OUT)
PRG1_CPSW_ETH1_D0M: J19.10(MX0-) U19.2(TD_M_A)
PRG1_CPSW_ETH1_D0P: J19.9(MX0+) U19.1(TD_P_A)
PRG1_CPSW_ETH1_D1M: J19.8(MX1-) U19.5(TD_M_B)
PRG1_CPSW_ETH1_D1P: J19.7(MX1+) U19.4(TD_P_B)
PRG1_CPSW_ETH1_D2M: J19.6(MX2-) U19.8(TD_M_C)
PRG1_CPSW_ETH1_D2P: J19.5(MX2+) U19.7(TD_P_C)
PRG1_CPSW_ETH1_D3M: J19.4(MX3-) U19.11(TD_M_D)
PRG1_CPSW_ETH1_D3P: J19.3(MX3+) U19.10(TD_P_D)
PRG1_CPSW_ETH1_LED1: J19.12 Q13.1(D1) Q13.2(D2) Q13.5(D3) Q13.6(D4) Q13.8(D5)
PRG1_CPSW_ETH1_LED2: J19.13 Q14.1(D1) Q14.2(D2) Q14.5(D3) Q14.6(D4) Q14.8(D5) R252.1
PRG1_CPSW_ETH1_LED3: J19.14 Q15.1(D1) Q15.2(D2) Q15.5(D3) Q15.6(D4) Q15.8(D5) R257.1
PRG1_CPSW_ETH1_LED_1000/RX_ER: Q14.3(G) R138.1 R265.2 U19.46(LED_1/RX_ER) ; also on sheet 12
PRG1_CPSW_ETH1_LED_ACT: Q13.3(G) R137.1 R266.2 R594.2 U19.45(LED_2/GPIO_0)
PRG1_CPSW_ETH1_LED_LINK: R139.1 R264.2 U19.47(LED_0) ; also on sheet 12
PRG1_CPSW_ETH1_RBIAS: R102.1 U19.12(RBIAS)
PRG1_CPSW_ETH2_LED_ACT: R596.2 ; also on sheet 18
PRG1_CPSW_RGMII1_CLK: U19.20(XI) ; also on sheet 14
PRG1_CPSW_RGMII1_GPIO_1: Q15.3(G) R95.2 R242.1 U19.22(JTAG_TDO/GPIO_1)
PRG1_CPSW_RGMII1_RD0: R123.1 R254.2 U19.33(RX_D0) U40.11(A6)
PRG1_CPSW_RGMII1_RD1: R129.2 R260.1 U19.34(RX_D1) U40.12(A7)
PRG1_CPSW_RGMII1_RD2: R132.1 R269.2 U19.35(RX_D2) U40.13(A8)
PRG1_CPSW_RGMII1_RD3: R133.1 R268.2 U19.36(RX_D3) U40.14(A9)
PRG1_CPSW_RGMII1_RSTn: U19.43(RESET_N) U43.4(Y)
PRG1_CPSW_RGMII1_RX_CTL: R134.2 R267.1 U19.38(RX_CTRL/RX_DV) U40.15(A10)
PRG1_CPSW_RGMII1_RXC: R115.1 U40.16(A11)
PRG1_CPSW_RGMII1_RXC_R: R115.2 U19.32(RX_CLK)
PRG1_CPSW_RGMII1_TD0: U19.28(TX_D0) U40.2(A0)
PRG1_CPSW_RGMII1_TD1: U19.27(TX_D1) U40.3(A1)
PRG1_CPSW_RGMII1_TD2: U19.26(TX_D2) U40.4(A2)
PRG1_CPSW_RGMII1_TD3: U19.25(TX_D3) U40.5(A3)
PRG1_CPSW_RGMII1_TX_CTL: U19.37(TX_CTRL/TX_EN) U40.6(A4)
PRG1_CPSW_RGMII1_TXC: U19.29(GTX_CLK/TX_CLK) U40.7(A5)
PRG1_CPSW_RGMII_INTn: R136.2 U19.44(INT_N/PWDN_N) ; also on sheet 12 18
PRG1_MDIO0_MDC: U19.42(MDC) ; also on sheet 12 18
PRG1_MDIO0_MDIO: R135.2 U19.41(MDIO) ; also on sheet 12 18
PRG1_RGMII1_RD0: U40.29(B6) ; also on sheet 12
PRG1_RGMII1_RD1: U40.27(B7) ; also on sheet 12
PRG1_RGMII1_RD2: U40.25(B8) ; also on sheet 12
PRG1_RGMII1_RD3: U40.23(B9) ; also on sheet 12
PRG1_RGMII1_RX_CTL: U40.21(B10) ; also on sheet 12
PRG1_RGMII1_RXC: U40.19(B11) ; also on sheet 12
PRG1_RGMII1_TD0: U40.41(B0) ; also on sheet 12
PRG1_RGMII1_TD1: U40.39(B1) ; also on sheet 12
PRG1_RGMII1_TD2: U40.38(B2) ; also on sheet 12
PRG1_RGMII1_TD3: U40.36(B3) ; also on sheet 12
PRG1_RGMII1_TX_CTL: U40.34(B4) ; also on sheet 12
PRG1_RGMII1_TXC: U40.32(B5) ; also on sheet 12
PRG_CPSW_RGMII1_MUX_SEL: R250.2 U40.9(SEL1) U40.10(SEL2) ; also on sheet 11
QSPI_RST_N: U2.3(RESET#) U31.4(Y)
SOC_ADC0_AIN0: C28.1 R142.1 R143.2 U18.H21(ADC0_AIN0)
SOC_ADC0_AIN1: C118.1 R152.2 R153.1 U18.F19(ADC0_AIN1)
SOC_ADC0_AIN2: C110.1 R144.2 R145.1 U18.F21(ADC0_AIN2)
SOC_ADC0_AIN3: C108.1 R146.2 R147.1 U18.F20(ADC0_AIN3)
SOC_ADC0_AIN4: C33.1 R148.2 R149.1 U18.H20(ADC0_AIN4)
SOC_ADC0_AIN5: C117.1 R150.2 R151.1 U18.E21(ADC0_AIN5)
SOC_ADC0_AIN6: C35.1 R154.2 R155.1 U18.G20(ADC0_AIN6)
SOC_ADC0_AIN7: C36.1 R156.2 R157.1 U18.E20(ADC0_AIN7)
SoC_I2C0_SCL: U17.6(SCL) ; also on sheet 11 19 23
SoC_I2C0_SDA: U17.5(SDA) ; also on sheet 11 19 23
VSYS_3V3: C10.1 C12.1 C41.1 C43.1 C46.1 C54.1 C94.1 C152.1 C159.1 C166.1 C207.1 C209.1 C248.1 C258.1 R5.2 R10.2 R36.2 R37.2 R89.2 R95.1 R129.1 R134.1 R135.1 R136.1 R181.2 R183.2 R252.2 R254.1 R257.2 R258.1 R264.1 R265.1 R266.1 R268.1 R269.1 R275.2 U2.2(VCC) U17.8(VCC) U19.18(VDDIO) U19.30(VDDIO) U31.5(VCC) U40.1(VCC) U40.8(EN) U40.17(VCC) U40.30(VCC) U43.5(VCC) ; also on sheet 10 11 12 13 14 18 19 20 21 22 23 24 25 27 28
N30174920: R179.2 R180.2 U31.2(B)
N30360253: TP25.1(TP) U19.13(VDDA1P8_1) U19.48(VDDA1P8_2)
N30371240: J19.11 R258.2

Not connected (* = marked no-connect by the designer): J19 2(VCC)*; U2 4(DNU1)* 5(DNU2)* 6(DNU3)* 11(DNU4)* 12(DNU5)* 13(DNU6)* 14(DNU7)*; U17 1(NC)*; U19 14(SON)* 15(SOP)* 16(SIP)* 17(SIN)* 19(XO)* 21(JTAG_CLK/TX_ER)* 23(JTAG_TMS)* 24(JTAG_TDI/SD)*

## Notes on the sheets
sheet 15
- QSPI FLASH
- GPIO0_12
- (MCU Warm Reset Output)
- (PORz Output)
- Board ID EEPROM
- I2C ADDRESS SET TO 0x50
sheet 16
- CPSW or PRG RGMII1 Ethernet Data MUX
- From SoC
- To Ethernet PHY
- This pin is pulled-down via resistor on BOOTMODE12 Pin
- Interface
- Mount
- DNI
- (From SoC GPIO)
- CPSW_RGMII1_TX_CTL &
  CPSW_RGMII1_TD1
     (Default)
- R595, R597
- R594, R596
- SEL1 & SEL2
- Path
- Interface
- Low (0)
- B0 to B11 --> A0 to A 11
- PRG1_RGMII1 (Default)
- PRG1_CPSW_ETH1_LED_ACT &
  PRG1_CPSW_ETH2_LED_ACT
- R594, R596
- R595, R597
- High (1)
- C0 to C11 --> A0 to A 11
- CPSW_RGMII1
- ADC Inputs
sheet 17
- PRG / CPSW RGMII1 Ethernet PHY
- RJ45 Connector with Integrated Magnetics
- RGMII1 PHY Strapping Resistors
- RGMII1 PHY Speed & Activity LED Drivers
- PHY ADDRESS = 00011
- Auto-negotiation, 10/100/1000 advertised, Auto-MDI-X
- RGMII to Copper (1000BaseT/100Base-TX/10Base-Te)
- RGMII1 PHY Reset
- (From SoC GPIO)
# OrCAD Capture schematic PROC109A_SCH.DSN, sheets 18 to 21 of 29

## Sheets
18 18. CPSW_PRG_RGMII_2_EPHY: size C; title: PRG/CPSW RGMII2 ETHERNET PHY
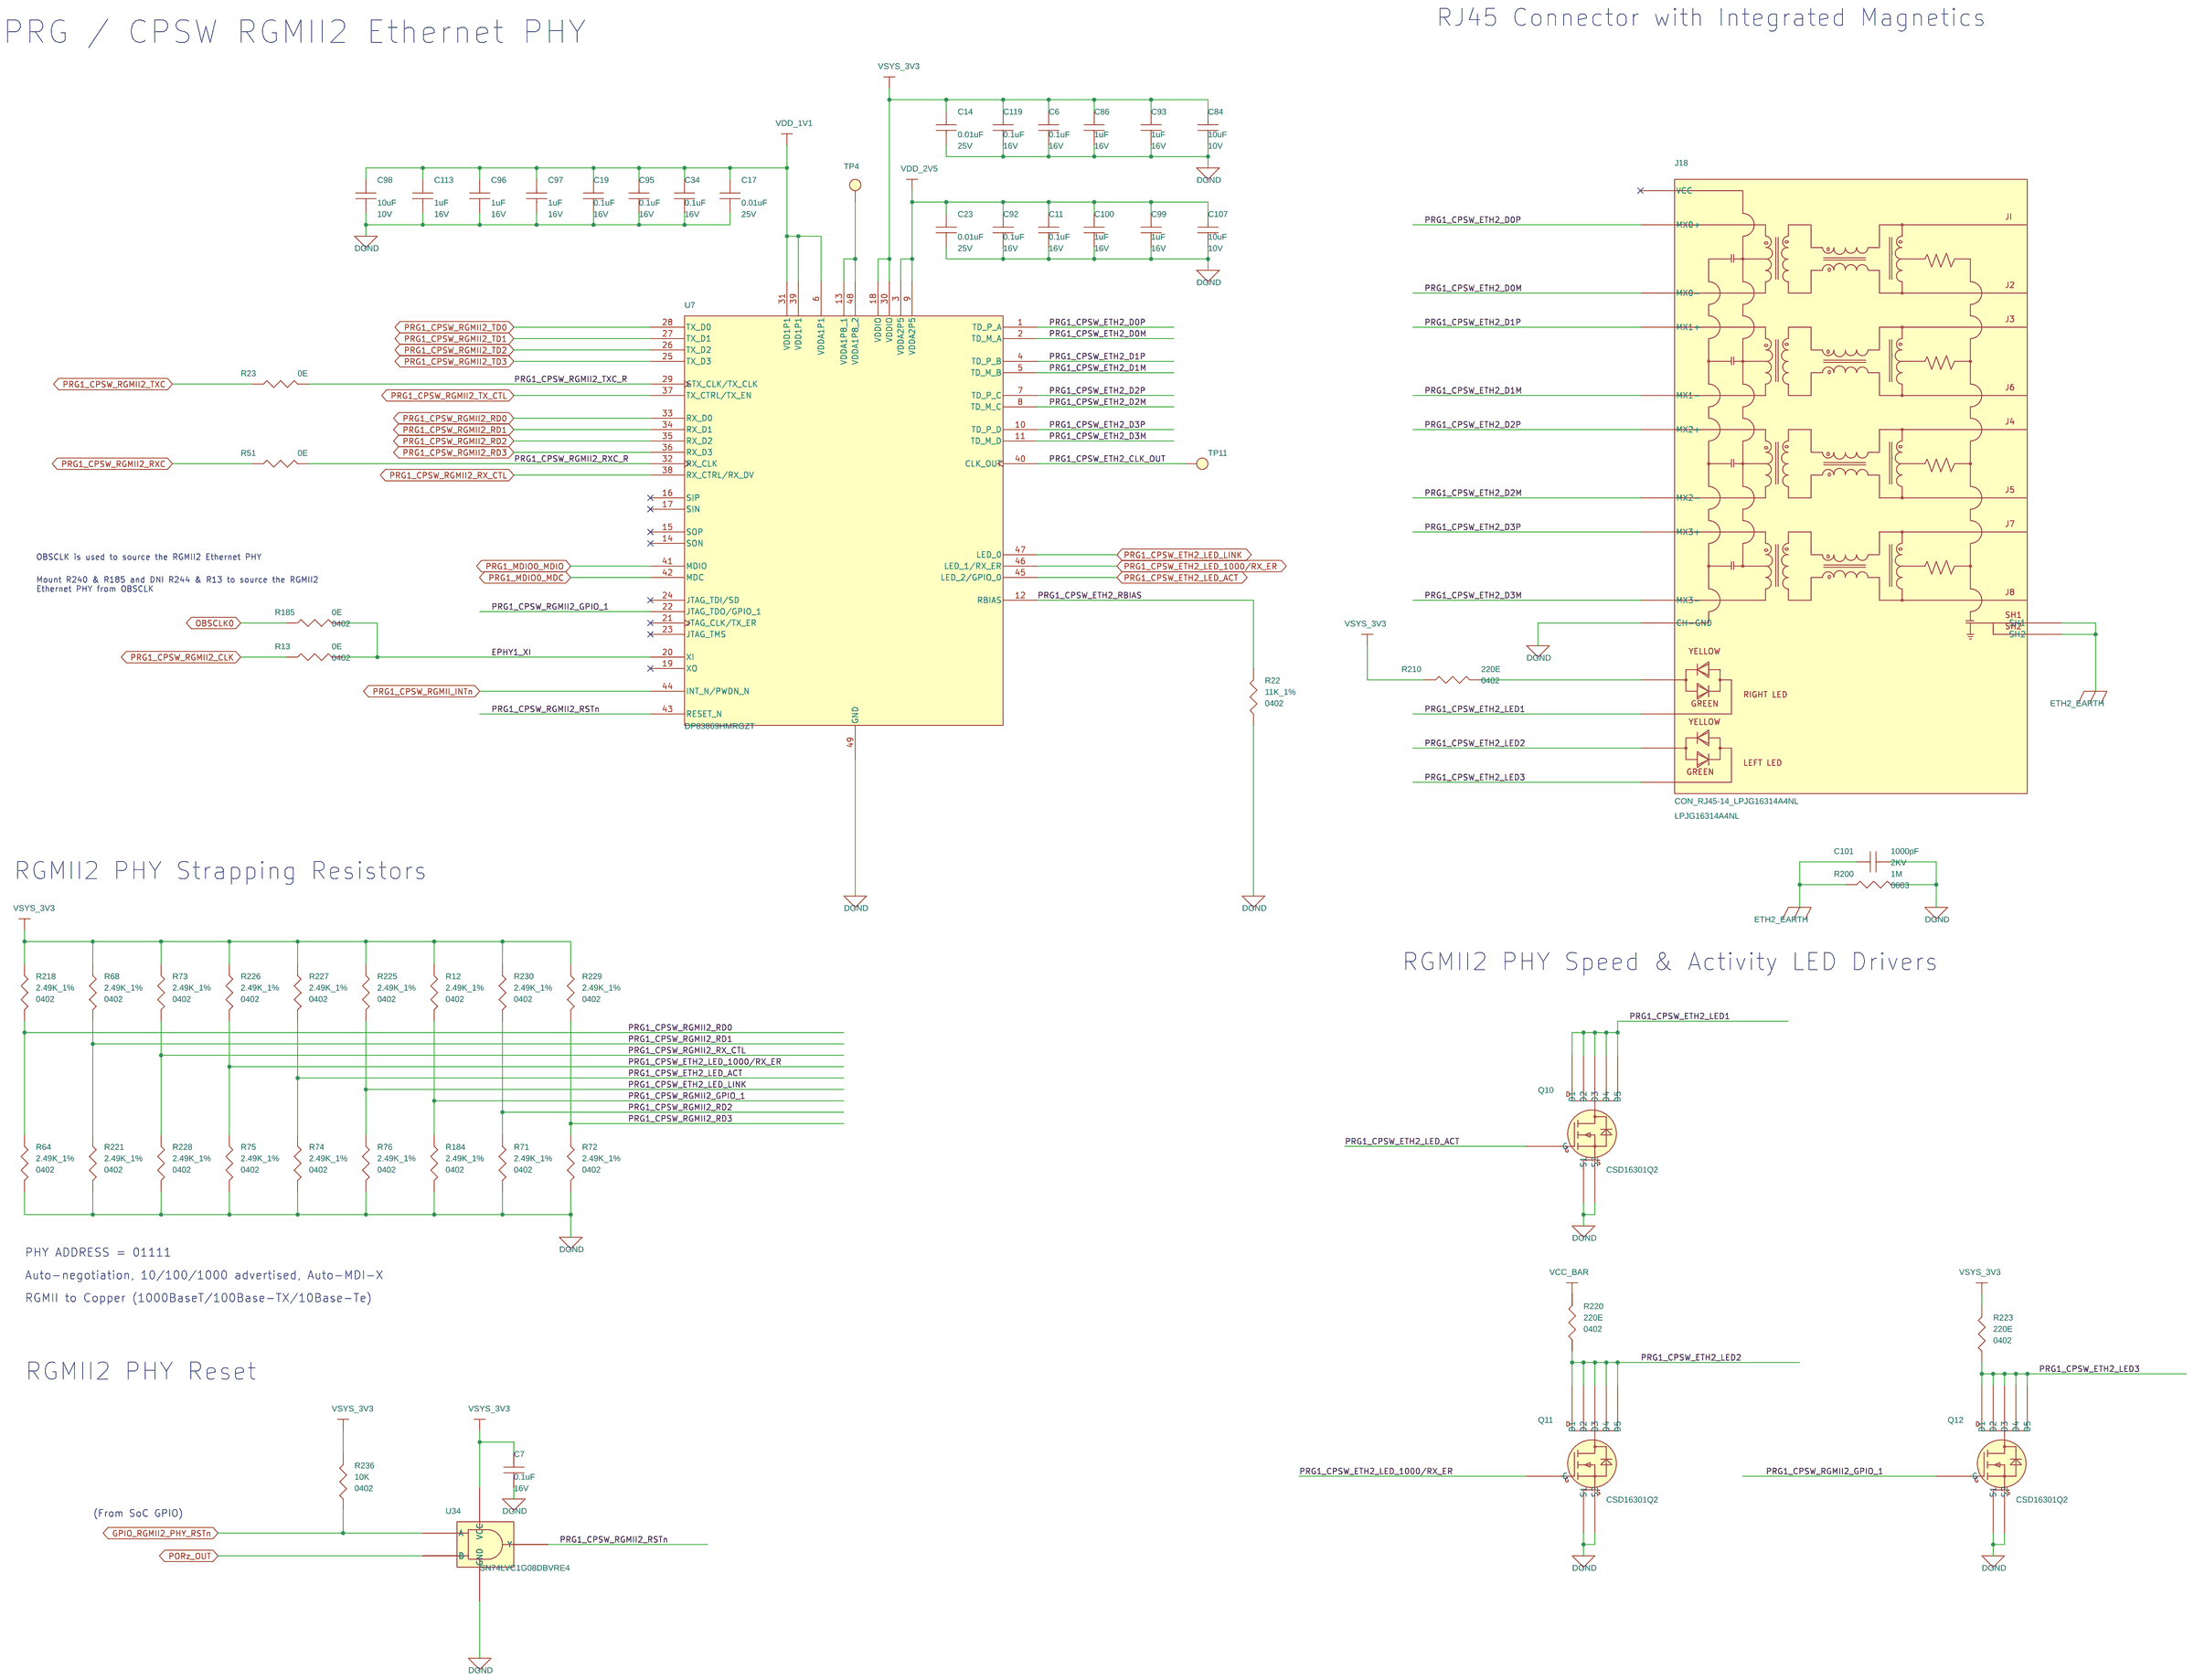
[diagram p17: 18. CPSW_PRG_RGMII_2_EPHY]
19 19. BOOSTERPACK_CONNECTOR: size C; title: BOOSTERPACK CONNECTOR
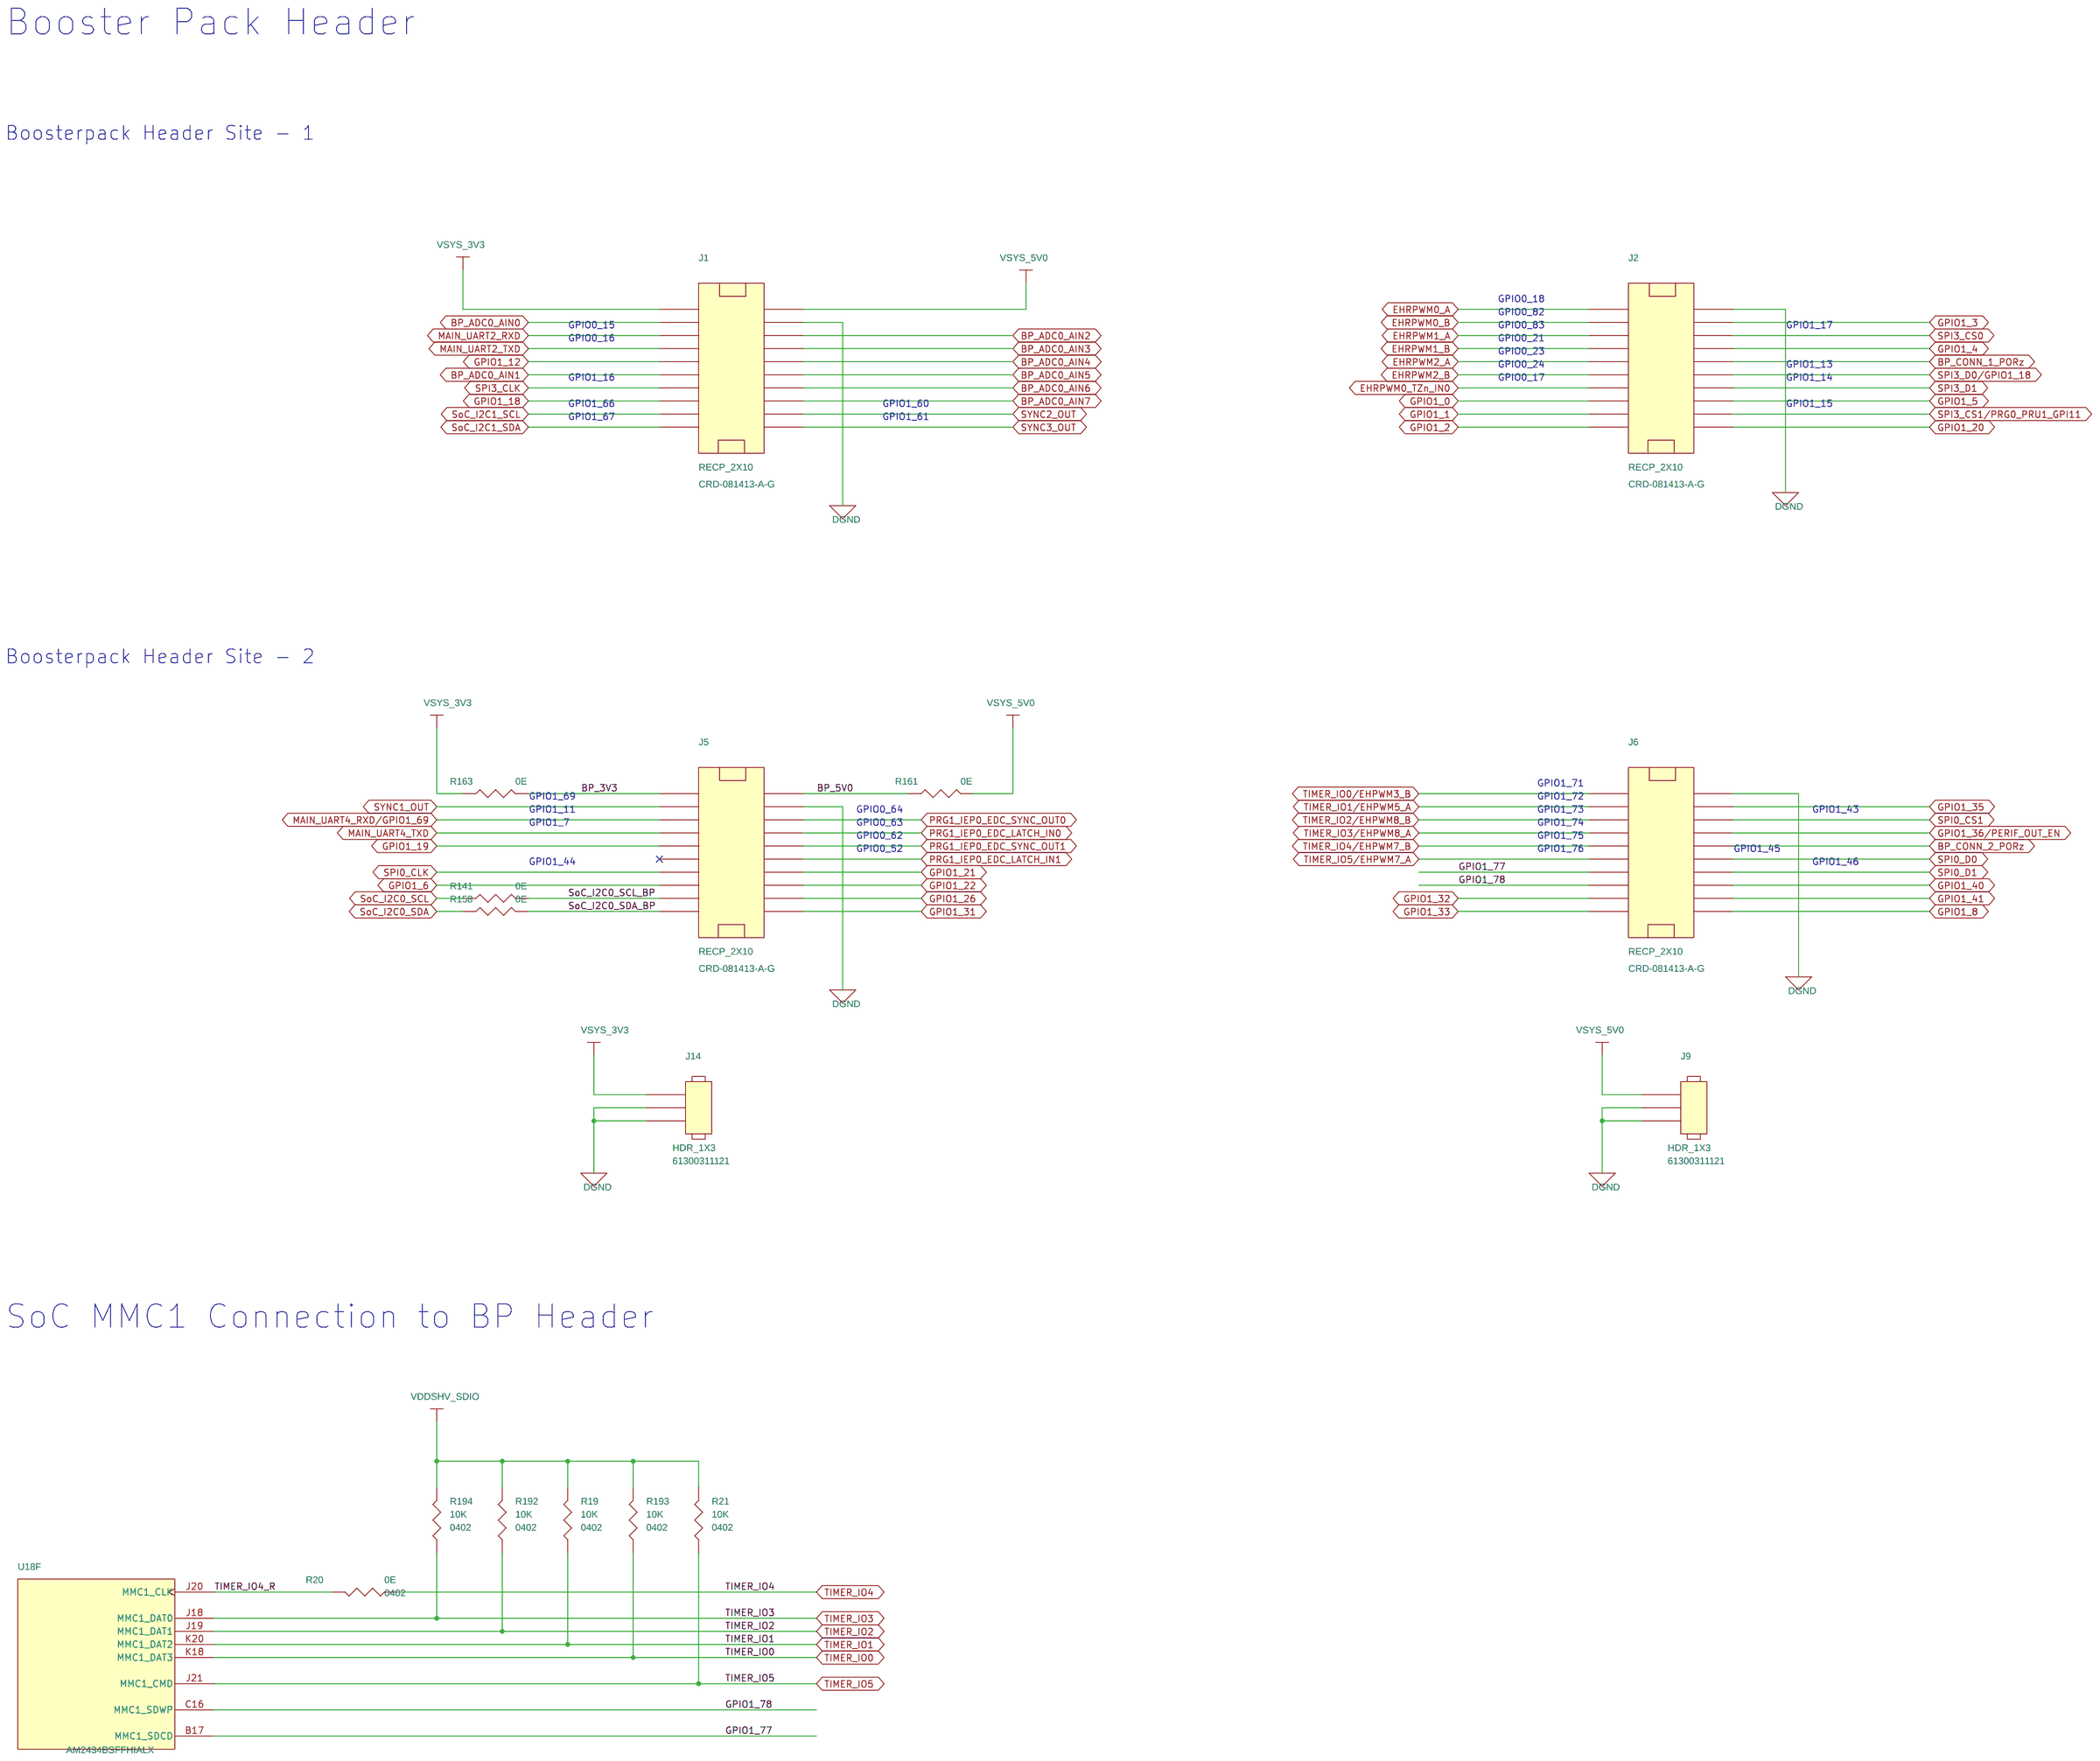
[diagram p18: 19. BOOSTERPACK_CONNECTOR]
20 20. TEST AUTOMATION HDR: size C; title: TEST AUTOMATION HEADER
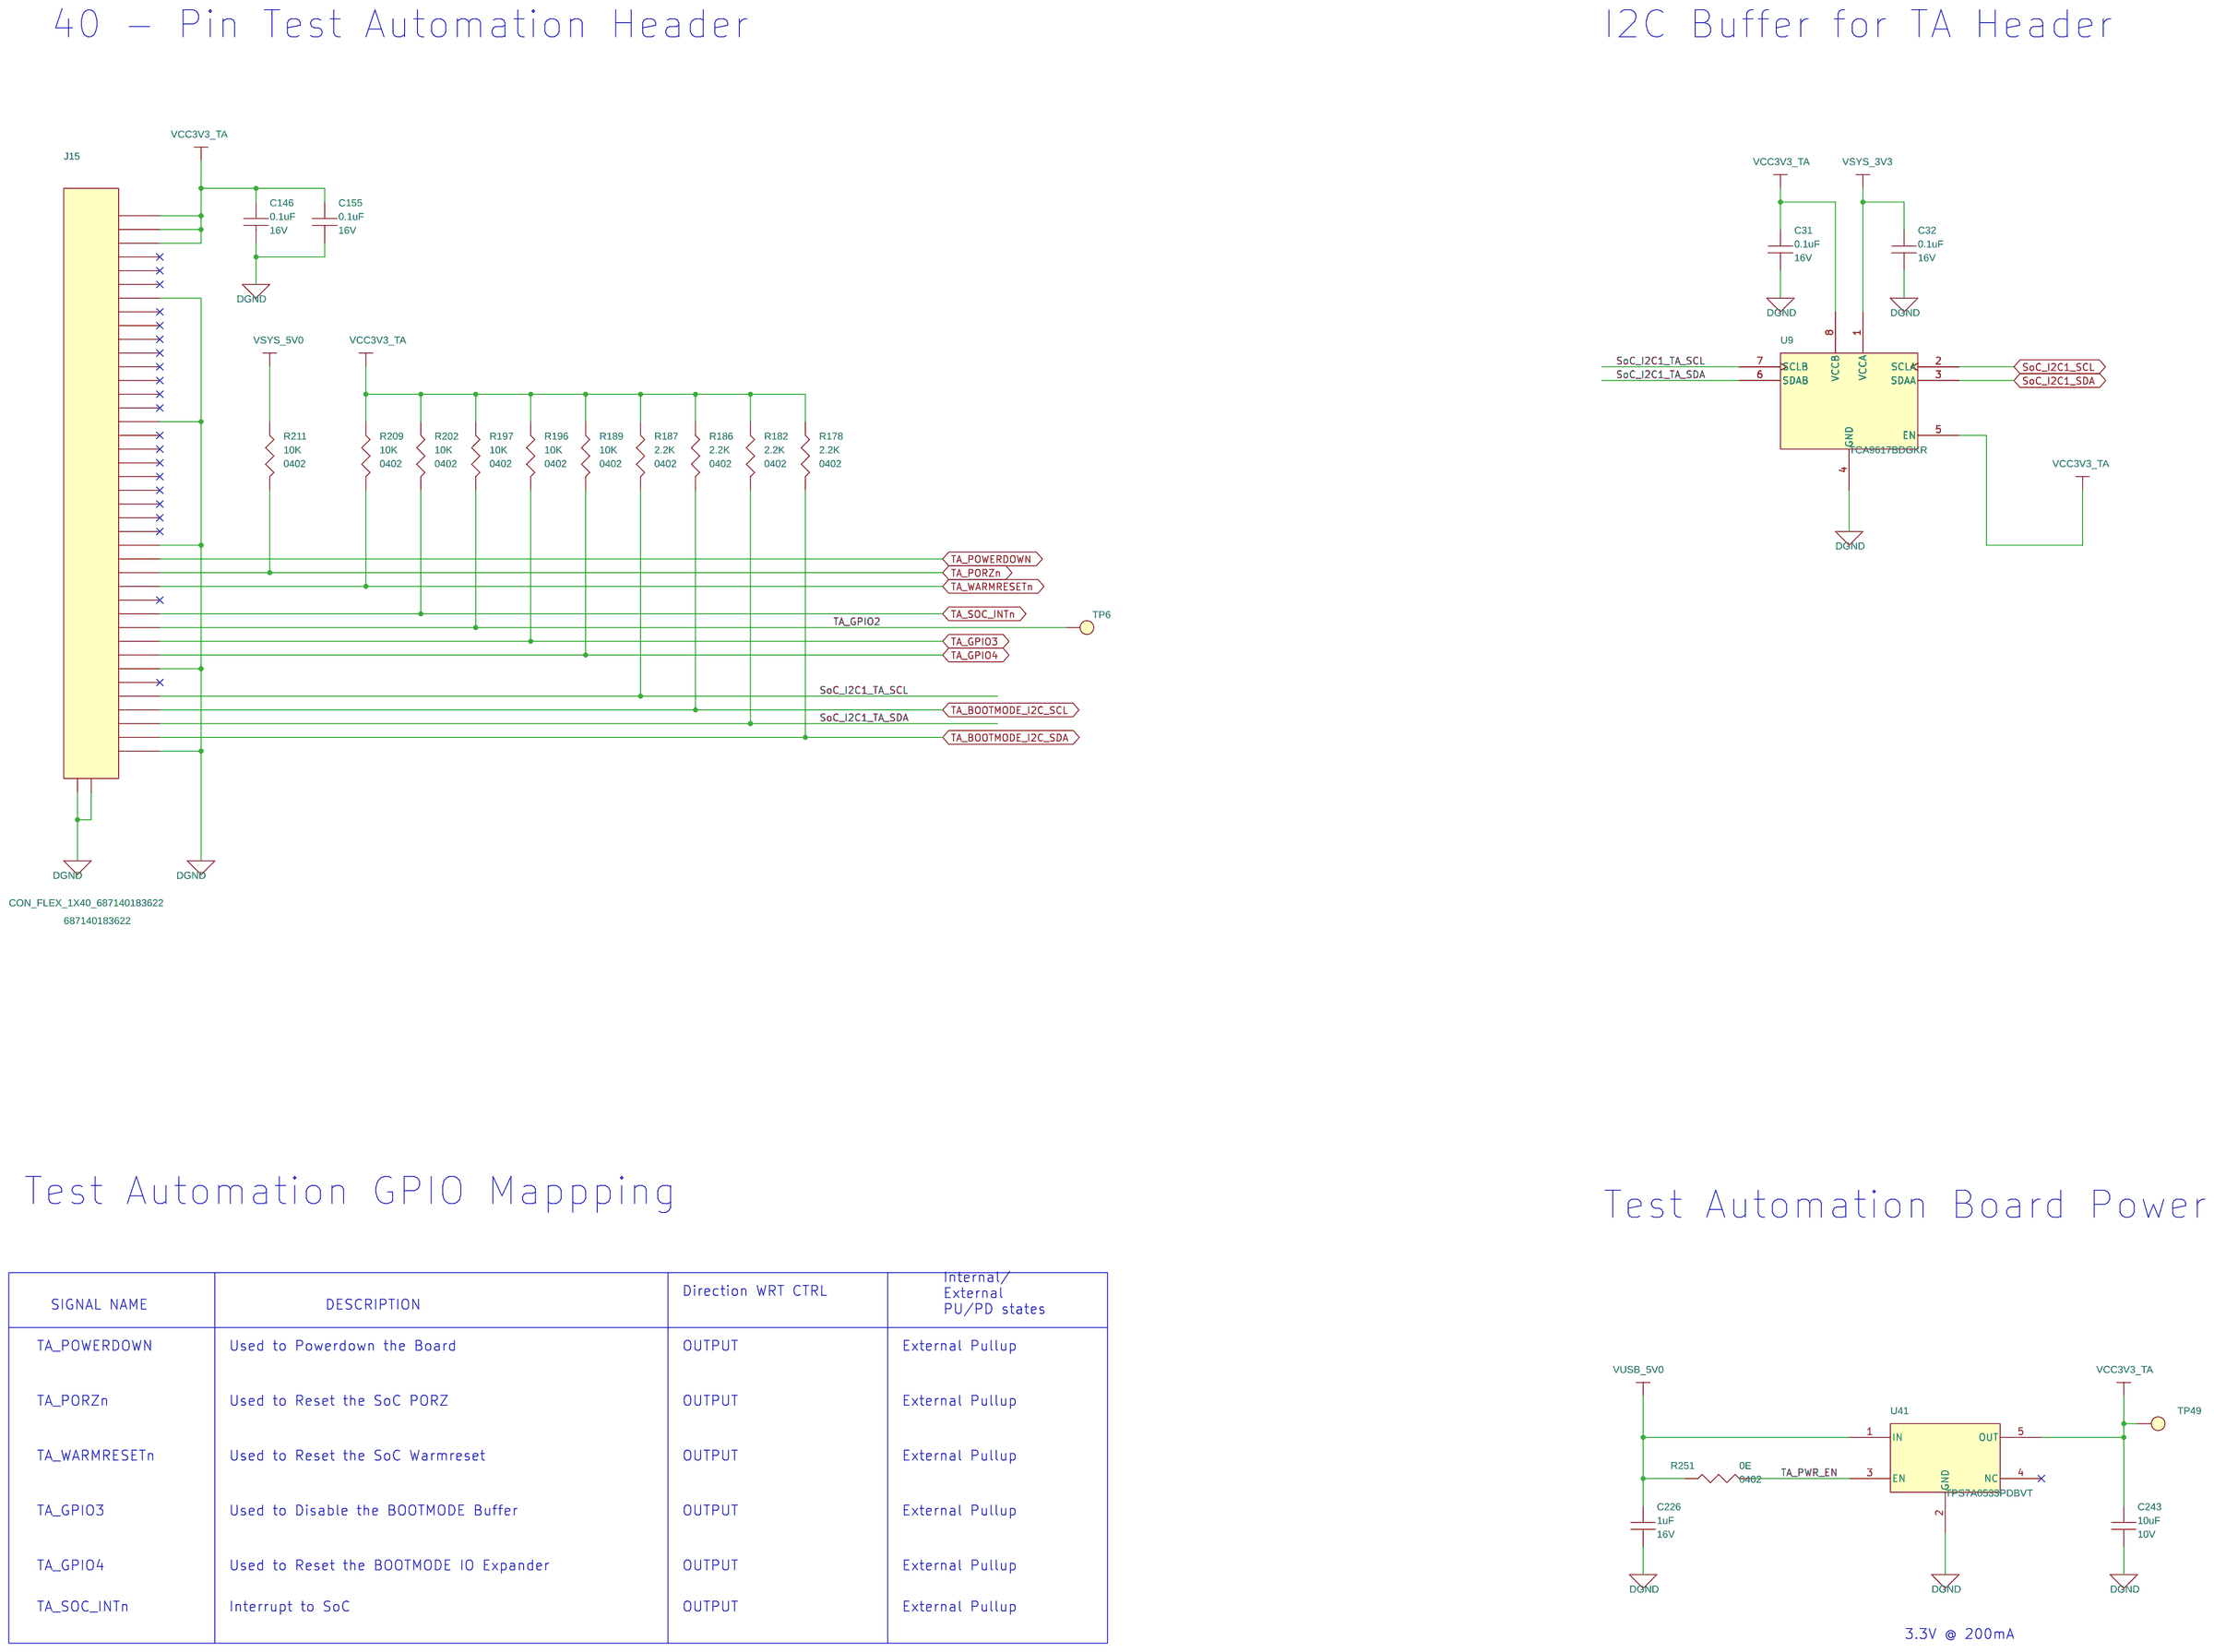
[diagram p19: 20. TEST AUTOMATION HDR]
21 21. BOOT MODE BUFFER & SWITCHES: size C; title: BOOT MODE BUFFER & SWITCHES

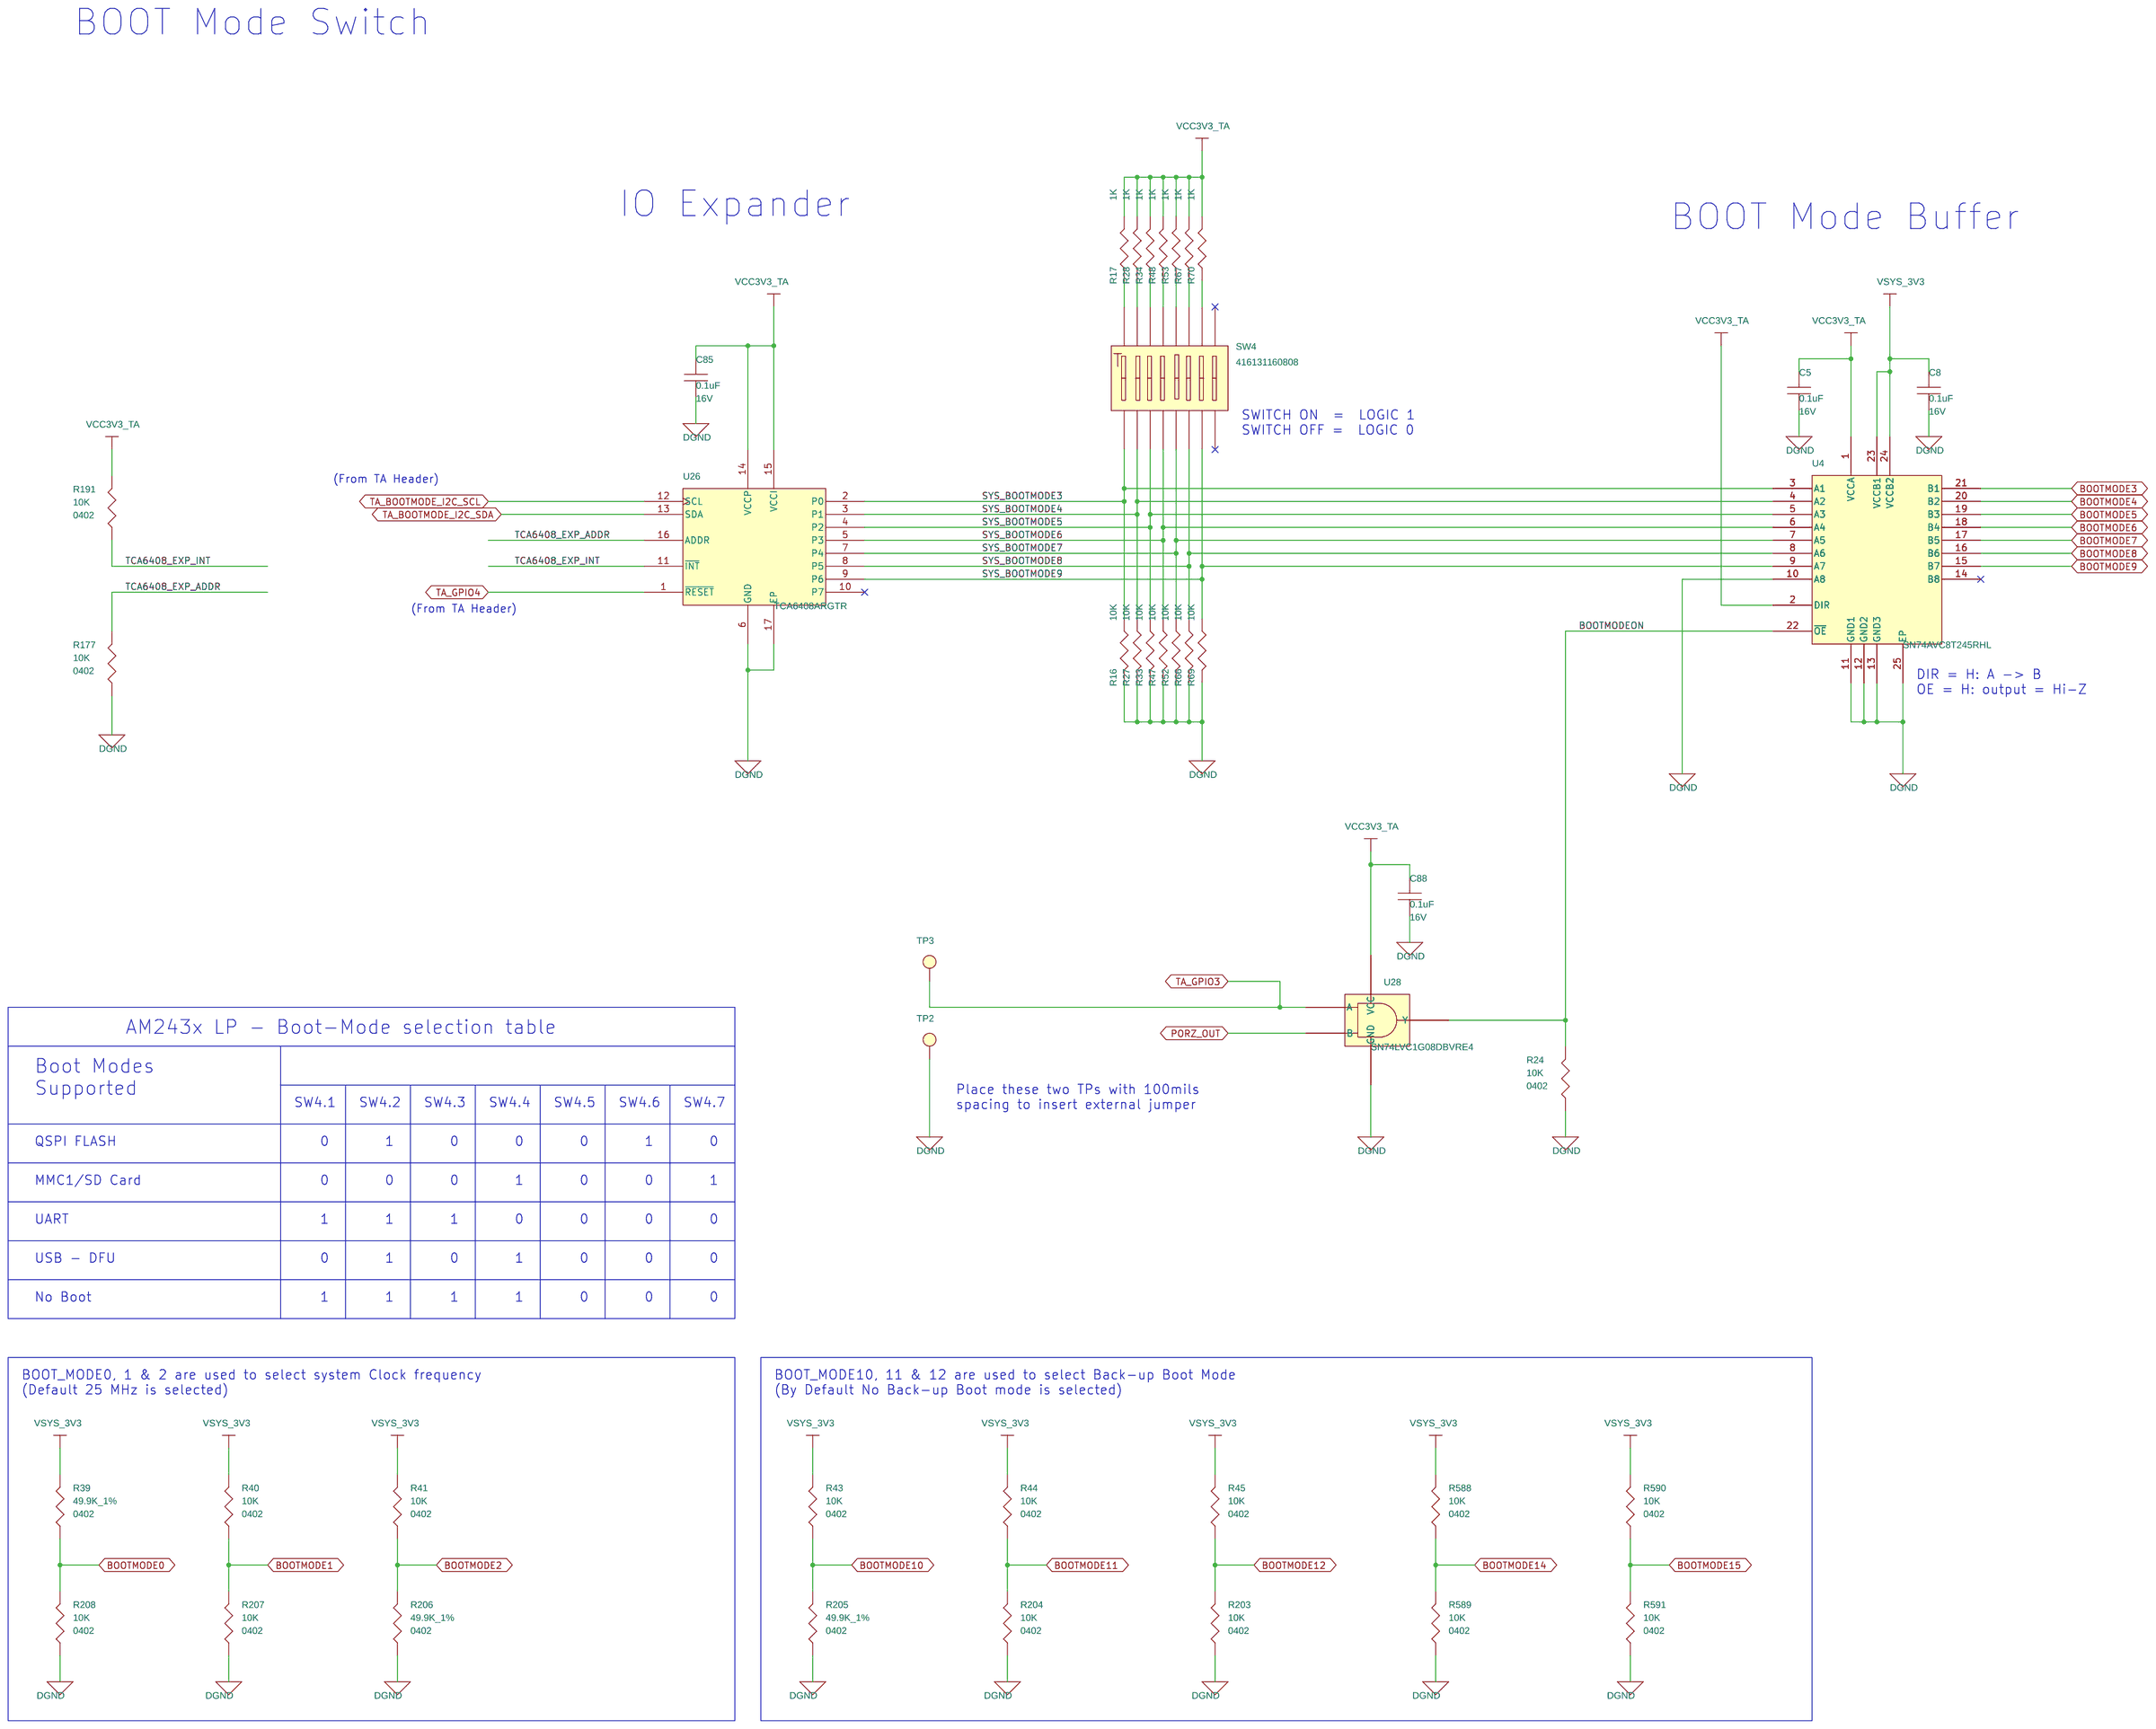
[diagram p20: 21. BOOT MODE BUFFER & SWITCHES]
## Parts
sheet 18. CPSW_PRG_RGMII_2_EPHY
C6  0.1uF  [CAP0201_0-5]
C7  0.1uF  [CAP0201_0-5]
C11  0.1uF  [CAP0201_0-5]
C14  0.01uF  [CAP0201_0-5]
C17  0.01uF  [CAP0201_0-5]
C19  0.1uF  [CAP0201_0-5]
C23  0.01uF  [CAP0201_0-5]
C34  0.1uF  [CAP0201_0-5]
C84  10uF  [CAP0402_0-75]
C86  1uF  [CAP0201_0-5]
C92  0.1uF  [CAP0201_0-5]
C93  1uF  [CAP0201_0-5]
C95  0.1uF  [CAP0201_0-5]
C96  1uF  [CAP0201_0-5]
C97  1uF  [CAP0201_0-5]
C98  10uF  [CAP0402_0-75]
C99  1uF  [CAP0201_0-5]
C100  1uF  [CAP0201_0-5]
C101  1000pF  [CAP1210_1-5]
C107  10uF  [CAP0402_0-75]
C113  1uF  [CAP0201_0-5]
C119  0.1uF  [CAP0201_0-5]
J18  CON_RJ45-14_LPJG16314A4NL  [CON_RJ45-14_LPJG16314A4NL_S_R_T_13-6]
Q10  CSD16301Q2  [WSON6_CSD13202Q2_80X80_0-8]
Q11  CSD16301Q2  [WSON6_CSD13202Q2_80X80_0-8]
Q12  CSD16301Q2  [WSON6_CSD13202Q2_80X80_0-8]
R12  2.49K_1%  [RES0402_0-5]
R13  0E  [RES0402_0-5]
R22  11K_1%  [RES0402_0-5]
R23  0E  [RES0402_0-5]
R51  0E  [RES0402_0-5]
R64  2.49K_1%  [RES0402_0-5]
R68  2.49K_1%  [RES0402_0-5]
R71  2.49K_1%  [RES0402_0-5]
R72  2.49K_1%  [RES0402_0-5]
R73  2.49K_1%  [RES0402_0-5]
R74  2.49K_1%  [RES0402_0-5]
R75  2.49K_1%  [RES0402_0-5]
R76  2.49K_1%  [RES0402_0-5]
R184  2.49K_1%  [RES0402_0-5]
R185  0E  [RES0402_0-5]
R200  1M  [RES0603_0-75]
R210  220E  [RES0402_0-5]
R218  2.49K_1%  [RES0402_0-5]
R220  220E  [RES0402_0-5]
R221  2.49K_1%  [RES0402_0-5]
R223  220E  [RES0402_0-5]
R225  2.49K_1%  [RES0402_0-5]
R226  2.49K_1%  [RES0402_0-5]
R227  2.49K_1%  [RES0402_0-5]
R228  2.49K_1%  [RES0402_0-5]
R229  2.49K_1%  [RES0402_0-5]
R230  2.49K_1%  [RES0402_0-5]
R236  10K  [RES0402_0-5]
TP4  TP20_SMD  [TP20_SMD]
TP11  TP20_SMD  [TP20_SMD]
U7  DP83869HMRGZT  [QFN48_19-68_280X280_1_EP4-2]
U34  SN74LVC1G08DBVRE4  [SOT23-5]
sheet 19. BOOSTERPACK_CONNECTOR
J1  RECP_2X10  [RECPT_2X10_CRD-081413-A_S_T_8-6]
J2  RECP_2X10  [RECPT_2X10_CRD-081413-A_S_T_8-6]
J5  RECP_2X10  [RECPT_2X10_CRD-081413-A_S_T_8-6]
J6  RECP_2X10  [RECPT_2X10_CRD-081413-A_S_T_8-6]
J9  HDR_1X3  [HDR_1X3_100_S_T]
J14  HDR_1X3  [HDR_1X3_100_S_T]
R19  10K  [RES0402_0-5]
R20  0E  [RES0402_0-5]
R21  10K  [RES0402_0-5]
R141  0E  [RES0402_0-5]
R158  0E  [RES0402_0-5]
R161  0E  [RES0402_0-5]
R163  0E  [RES0402_0-5]
R192  10K  [RES0402_0-5]
R193  10K  [RES0402_0-5]
R194  10K  [RES0402_0-5]
sheet 20. TEST AUTOMATION HDR
C31  0.1uF  [CAP0201_0-5]
C32  0.1uF  [CAP0201_0-5]
C146  0.1uF  [CAP0201_0-5]
C155  0.1uF  [CAP0201_0-5]
C226  1uF  [CAP0201_0-5]
C243  10uF  [CAP0402_0-75]
J15  CON_FLEX_1X40_687140183622  [CON_FLEX1X40_687140183622_S_R_S_1-3]
R178  2.2K  [RES0402_0-5]
R182  2.2K  [RES0402_0-5]
R186  2.2K  [RES0402_0-5]
R187  2.2K  [RES0402_0-5]
R189  10K  [RES0402_0-5]
R196  10K  [RES0402_0-5]
R197  10K  [RES0402_0-5]
R202  10K  [RES0402_0-5]
R209  10K  [RES0402_0-5]
R211  10K  [RES0402_0-5]
R251  0E  [RES0402_0-5]
TP6  TP20_SMD  [TP20_SMD]
TP49  TP20_SMD  [TP20_SMD]
U9  TCA9617BDGKR  [VSSOP8_25-59_120X120_1-1]
U41  TPS7A0533PDBVT  [SOT23-5_1-5]
sheet 21. BOOT MODE BUFFER & SWITCHES
C5  0.1uF  [CAP0201_0-5]
C8  0.1uF  [CAP0201_0-5]
C85  0.1uF  [CAP0201_0-5]
C88  0.1uF  [CAP0201_0-5]
R16  10K  [RES0402_0-5]
R17  1K  [RES0402_0-5]
R24  10K  [RES0402_0-5]
R27  10K  [RES0402_0-5]
R28  1K  [RES0402_0-5]
R33  10K  [RES0402_0-5]
R34  1K  [RES0402_0-5]
R39  49.9K_1%  [RES0402_0-5]
R40  10K  [RES0402_0-5]
R41  10K  [RES0402_0-5]
R43  10K  [RES0402_0-5]
R44  10K  [RES0402_0-5]
R45  10K  [RES0402_0-5]
R47  10K  [RES0402_0-5]
R48  1K  [RES0402_0-5]
R52  10K  [RES0402_0-5]
R53  1K  [RES0402_0-5]
R66  10K  [RES0402_0-5]
R67  1K  [RES0402_0-5]
R69  10K  [RES0402_0-5]
R70  1K  [RES0402_0-5]
R177  10K  [RES0402_0-5]
R191  10K  [RES0402_0-5]
R203  10K  [RES0402_0-5]
R204  10K  [RES0402_0-5]
R205  49.9K_1%  [RES0402_0-5]
R206  49.9K_1%  [RES0402_0-5]
R207  10K  [RES0402_0-5]
R208  10K  [RES0402_0-5]
R588  10K  [RES0402_0-5]
R589  10K  [RES0402_0-5]
R590  10K  [RES0402_0-5]
R591  10K  [RES0402_0-5]
SW4  416131160808  [SW16_416131160808_460X230_SMD_2-7]
TP2  THRU HOLE  [TP_40X65]
TP3  THRU HOLE  [TP_40X65]
U4  SN74AVC8T245RHL  [QFN24_19-68_220X140_1]
U26  TCA6408ARGTR  [QFN16_19-68_120X120_1_EP1-6]
U28  SN74LVC1G08DBVRE4  [SOT23-5]
sheet 24. SOC_DIGITAL_POWER_DECAPs
U18  AM2434BSFFHIALX  [BGA293_19-68_440X440_1]  (sections A,B,C,D,E,F,G,H,I,J,K,L,M)

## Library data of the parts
C5-C8 C11 C19 C31 C32 C34 C85 C88 C92 C95 C119 C146 C155 = CAP: CAP CERAMIC 0.1uF 16V 10% X5R 0201; Alt_Mfr_name: YAGEO AMERICA; Alt_Mfr_part_number: CC0402KRX5R8BB104; Chkd/date: MANIRAJA/230118; Crtd /date: MANIRAJA/230118; Custom_Duty: 15%; Customs_HS_Code: 85322990; Distributor_name: DIGIKEY; Distributor_part_number: 490-14305-1-ND; Footprint Path: Y:\MIS_DATABASE\Library\ALTIUM_TOOL\PCB_FOOTPRINTS\Altium_Footprint_Lib.PcbLib; Height: 0.33MM; Library Path: Y:\MIS_DATABASE\Library\ALTIUM_TOOL\SCHEMATICS_PARTS\MS_DISCRETE_Library.schlib; Mfr_name: MURATA; Mfr_part_number: GRM033R61C104KE14D; Mistral Part No: 120009030072-R; Package: 0201; Part_type: CAPACITORS\CERAMIC; Project: TI_MAXIE_CPB; RoHS: RoHS; Temperature: -55°C+85°C; Tolerance: 10%; Voltage: 16V; Wattage: NA; Weight: 0.33mg; Datasheet: Y:\MIS_DATABASE\DATASHEETS\CAPACITORS\GRM033R61C104KE14.PDF
C14 C17 C23 = CAP: CAP CERAMIC 0.01uF 25V 10% X7R 0201; Chkd/date: MANIRAJA/080519; Crtd /date: ALVY/080519; Custom_Duty: 15%; Customs_HS_Code: 85322990; Distributor_name: DIGIKEY; Distributor_part_number: 490-14454-1-ND; Footprint Path: Y:\MIS_DATABASE\Library\ALTIUM_TOOL\PCB_FOOTPRINTS\Altium_Footprint_Lib.PcbLib; Height: 0.33MM; Library Path: Y:\MIS_DATABASE\Library\ALTIUM_TOOL\SCHEMATICS_PARTS\MS_DISCRETE_Library.schlib; Mfr_name: MURATA; Mfr_part_number: GRM033R71E103KE14D; Mistral Part No: 120019050002-R; Package: 0201; Part_type: CAPACITORS\CERAMIC; Project: BRUKER_SD820_COMMONDO; RoHS: RoHS; Temperature: -55°C+125°C; Tolerance: 10%; Voltage: 25V; Wattage: NA; Weight: 0.33mg; Datasheet: Y:\MIS_DATABASE\DATASHEETS\CAPACITORS\GRM033R71E103KE14.PDF
C84 C98 C107 C243 = CAP: CAP CERAMIC 10uF 10V 20% X5R 0402; Chkd/date: MANIRAJA/300520; Crtd /date: ALVY/260520; Custom_Duty: 15%; Customs_HS_Code: 85322990; Distributor_name: DIGIKEY; Distributor_part_number: 490-GRM155R61A106ME11DTR-ND; Footprint Path: Y:\MIS_DATABASE\Library\ALTIUM_TOOL\PCB_FOOTPRINTS\Altium_Footprint_Lib.PcbLib; Height: 0.55MM; Library Path: Y:\MIS_DATABASE\Library\ALTIUM_TOOL\SCHEMATICS_PARTS\MS_DISCRETE_Library.schlib; Mfr_name: MURATA; Mfr_part_number: GRM155R61A106ME11D; Mistral Part No: 120013110019-R; Package: 0402; Part_type: CAPACITORS\CERAMIC; Project: QCS610_NANOSOM; RoHS: RoHS; Temperature: -55°C+85°C; Tolerance: 20%; Voltage: 10V; Wattage: NA; Weight: 3.1mg; Datasheet: Y:\MIS_DATABASE\DATASHEETS\CAPACITORS\MURATA-GXX-SER_NOV17.PDF
C86 C93 C96 C97 C99 C100 C113 C226 = CAP: CAP CERAMIC 1uF 16V 20% X5R 0201; Chkd/date: MANIRAJA/300520; Crtd /date: ALVY/260520; Custom_Duty: 15%; Customs_HS_Code: 85322990; Distributor_name: DIGIKEY; Distributor_part_number: 490-18654-1-ND; Footprint Path: Y:\MIS_DATABASE\Library\ALTIUM_TOOL\PCB_FOOTPRINTS\Altium_Footprint_Lib.PcbLib; Height: 0.39MM; Library Path: Y:\MIS_DATABASE\Library\ALTIUM_TOOL\SCHEMATICS_PARTS\MS_DISCRETE_Library.schlib; Mfr_name: MURATA; Mfr_part_number: GRM033R61C105ME15D; Mistral Part No: 120018090038-R; Package: 0201; Part_type: CAPACITORS\CERAMIC; Project: QCS610_NANOSOM; RoHS: RoHS; Temperature: -55°C+85°C; Tolerance: 20%; Voltage: 16V; Wattage: NA; Weight: 0.33mg; Datasheet: Y:\MIS_DATABASE\DATASHEETS\CAPACITORS\GRM033R61C105ME15.PDF
C101 = CAP: CAP CERAMIC 1000pF 2KV 10% X7R 1210; Chkd/date: ALVY/071220; Crtd /date: MANIRAJA/071220; Custom_Duty: 15%; Customs_HS_Code: 85322990; Distributor_name: DIGIKEY; Distributor_part_number: 732-12130-1-ND; Footprint Path: Y:\MIS_DATABASE\Library\ALTIUM_TOOL\PCB_FOOTPRINTS\Altium_Footprint_Lib.PcbLib; Height: 1.35MM; Library Path: Y:\MIS_DATABASE\Library\ALTIUM_TOOL\SCHEMATICS_PARTS\MS_DISCRETE_Library.schlib; Mfr_name: WURTH ELEKTRONIK; Mfr_part_number: 885342209009; Mistral Part No: 120020120008-R; Package: 1210; Part_type: CAPACITORS\CERAMIC; Project: TI_AM243x LP EVM; RoHS: RoHS; Temperature: -55°C+125°C; Tolerance: 10%; Voltage: 2KV; Wattage: NA; Weight: 19.234mg; Datasheet: Y:\MIS_DATABASE\DATASHEETS\CAPACITORS\885342209009.PDF
J18 = CON_RJ45-14_LPJG16314A4NL: CON RJ-45 FEMALE 14POS RT TH; Chkd/date: VASANTHA/150714; Crtd /date: BALACHANDAR/120614; Custom_Duty: 24%; Customs_HS_Code: 85369090; Distributor_name: NA; Distributor_part_number: NA; Footprint Path: Y:\MIS_DATABASE\Library\ALTIUM_TOOL\PCB_FOOTPRINTS\Altium_Footprint_Lib.PcbLib; Height: 13.60MM; Library Path: Y:\MIS_DATABASE\Library\ALTIUM_TOOL\SCHEMATICS_PARTS\MS_CONNECTOR_Library.schlib; Mfr_name: LINK-PP; Mfr_part_number: LPJG16314A4NL; Mistral Part No: 150014060029-R; Package: THRU-HOLE; Part_type: CONNECTOR\JACK; Project: AEGIS; RoHS: RoHS; Temperature: -0°C+70°C; Tolerance: NA; Voltage: NA; Wattage: NA; Weight: NA; Datasheet: Y:\MIS_DATABASE\DATASHEETS\CONNECTORS\LPJG16314A4NL.PDF
Q10-Q12 = MOSFET_CSD17313Q2: IC MOSFET N-CHANNEL NEXFET 25V WSON6; Chkd/date: ALVY/071220; Crtd /date: MANIRAJA/071220; Custom_Duty: 15%; Customs_HS_Code: 85423100; Distributor_name: DIGIKEY; Distributor_part_number: 296-25260-1-ND; Footprint Path: Y:\MIS_DATABASE\Library\ALTIUM_TOOL\PCB_FOOTPRINTS\Altium_Footprint_Lib.PcbLib; Height: 0.80MM; Library Path: Y:\MIS_DATABASE\Library\ALTIUM_TOOL\SCHEMATICS_PARTS\MS_MOSFET_Library.schlib; Mfr_name: TEXAS INSTRUMENTS; Mistral Part No: 142020120008-R; Package: WSON6; Part_type: ICS\POWER\MOSFET; Project: TI_AM243x LP EVM; RoHS: RoHS; Temperature: -55°C+150°C; Tolerance: NA; Voltage: NA; Wattage: NA; Weight: 8.7mg; Datasheet: Y:\MIS_DATABASE\DATASHEETS\ICS\POWER\CSD16301Q2.PDF
R12 R64 R68 R71-R76 R184 R218 R221 R225-R230 = RESISTOR: RES 2.49K 1/16W 1% 0402; Chkd/date: VASANTHA/270516; Crtd /date: VASANTHA/270516; Custom_Duty: 15%; Customs_HS_Code: 85332119; Distributor_name: DIGIKEY; Distributor_part_number: 311-2.49KLRCT-ND; Footprint Path: Y:\MIS_DATABASE\Library\ALTIUM_TOOL\PCB_FOOTPRINTS\Altium_Footprint_Lib.PcbLib; Height: 0.40MM; Library Path: Y:\MIS_DATABASE\Library\ALTIUM_TOOL\SCHEMATICS_PARTS\MS_DISCRETE_Library.schlib; Mfr_name: YAGEO AMERICA; Mfr_part_number: RC0402FR-072K49L; Mistral Part No: 110016050020-R; Package: 0402; Part_type: RESISTORS\FIXED; Project: TMDXCSKCC; RoHS: RoHS; Temperature: -55°C+155°C; Tolerance: 1%; Voltage: NA; Wattage: 1/16W; Weight: 0.65mg; Datasheet: Y:\MIS_DATABASE\DATASHEETS\RESISTORS\RCXXXXL-SER_MAR18.PDF
R13 R141 R158 R161 R163 R185 R251 = RESISTOR: RES 0E 1/16W 5% 0402; Chkd/date: VASANTHA/291216; Crtd /date: CHAITHANYA/300911; Custom_Duty: 15%; Customs_HS_Code: 85332119; Distributor_name: DIGIKEY; Distributor_part_number: 311-0.0JRCT-ND; Footprint Path: Y:\MIS_DATABASE\Library\ALTIUM_TOOL\PCB_FOOTPRINTS\Altium_Footprint_Lib.PcbLib; Height: 0.40MM; Library Path: Y:\MIS_DATABASE\Library\ALTIUM_TOOL\SCHEMATICS_PARTS\MS_DISCRETE_Library.schlib; Mfr_name: YAGEO AMERICA; Mfr_part_number: RC0402JR-070RL; Mistral Part No: 110011090036-R; Package: 0402; Part_type: RESISTORS\FIXED; Project: VP-4000-PROCESSOR; RoHS: RoHS; Temperature: -55°C+155°C; Tolerance: 5%; Voltage: NA; Wattage: 1/16W; Weight: 0.65mg; Datasheet: Y:\MIS_DATABASE\DATASHEETS\RESISTORS\RCXXXXL-SER_MAR18.PDF
R22 = RESISTOR: RES 11K 1/16W 1% 0402; Chkd/date: VASANTHA/251115; Crtd /date: VASANTHA/251115; Custom_Duty: 15%; Customs_HS_Code: 85332119; Distributor_name: DIGIKEY; Distributor_part_number: 311-11.0KLRCT-ND; Footprint Path: Y:\MIS_DATABASE\Library\ALTIUM_TOOL\PCB_FOOTPRINTS\Altium_Footprint_Lib.PcbLib; Height: 0.40MM; Library Path: Y:\MIS_DATABASE\Library\ALTIUM_TOOL\SCHEMATICS_PARTS\MS_DISCRETE_Library.schlib; Mfr_name: YAGEO AMERICA; Mfr_part_number: RC0402FR-0711KL; Mistral Part No: 110015110012-R; Package: 0402; Part_type: RESISTORS\FIXED; Project: TI_VLAN_SWITCH; RoHS: RoHS; Temperature: -55°C+155°C; Tolerance: 1%; Voltage: NA; Wattage: 1/16W; Weight: 0.65mg; Datasheet: Y:\MIS_DATABASE\DATASHEETS\RESISTORS\RCXXXXL-SER_MAR18.PDF
R20 R23 R51 = RESISTOR: RES 0E 1/16W 5% 0402; Chkd/date: VASANTHA/291216; Crtd /date: CHAITHANYA/300911; Custom_Duty: 15%; Customs_HS_Code: 85332119; Distributor_name: DIGIKEY; Distributor_part_number: 311-0.0JRCT-ND; Footprint Path: Y:\MIS_DATABASE\Library\ALTIUM_TOOL\PCB_FOOTPRINTS\Altium_Footprint_Lib.PcbLib; Height: 0.40MM; Library Path: Y:\MIS_DATABASE\Library\ALTIUM_TOOL\SCHEMATICS_PARTS\MS_DISCRETE_Library.schlib; Mfr_name: YAGEO AMERICA; Mfr_part_number: RC0402JR-070RL; Mistral Part No: 110011090036-R; Package: 0402; Part_type: RESISTORS\FIXED; Project: VP-4000-PROCESSOR; RoHS: RoHS; SIGNAL_MODEL: RESISTOR_RES0402_0-5_0E_0E; Temperature: -55°C+155°C; Tolerance: 5%; Voltage: NA; Wattage: 1/16W; Weight: 0.65mg; Datasheet: Y:\MIS_DATABASE\DATASHEETS\RESISTORS\RCXXXXL-SER_MAR18.PDF
R200 = RESISTOR: RES 1M 1/10W 5% 0603; Chkd/date: ALVY/091220; Crtd /date: MANIRAJA/091220; Custom_Duty: 15%; Customs_HS_Code: 85332119; Distributor_name: DIGIKEY; Distributor_part_number: 311-1.0MGRCT-ND; Footprint Path: Y:\MIS_DATABASE\Library\ALTIUM_TOOL\PCB_FOOTPRINTS\Altium_Footprint_Lib.PcbLib; Height: 0.55MM; Library Path: Y:\MIS_DATABASE\Library\ALTIUM_TOOL\SCHEMATICS_PARTS\MS_DISCRETE_Library.schlib; Mfr_name: YAGEO AMERICA; Mfr_part_number: RC0603JR-071ML; Mistral Part No: 110009030413-R; Package: 0603; Part_type: RESISTORS\FIXED; Project: TI_AM243x LP EVM; RoHS: RoHS; Temperature: -55°C+155°C; Tolerance: 5%; Voltage: NA; Wattage: 1/10W; Weight: 2mg; Datasheet: Y:\MIS_DATABASE\DATASHEETS\RESISTORS\RCXXXXL-SER_MAR18.PDF
R210 R220 R223 = RESISTOR: RES 220E 1/16W 5% 0402; Chkd/date: ALVY/091220; Crtd /date: MANIRAJA/091220; Custom_Duty: 15%; Customs_HS_Code: 85332119; Distributor_name: DIGIKEY; Distributor_part_number: 311-220JRCT-ND; Footprint Path: Y:\MIS_DATABASE\Library\ALTIUM_TOOL\PCB_FOOTPRINTS\Altium_Footprint_Lib.PcbLib; Height: 0.40MM; Library Path: Y:\MIS_DATABASE\Library\ALTIUM_TOOL\SCHEMATICS_PARTS\MS_DISCRETE_Library.schlib; Mfr_name: YAGEO AMERICA; Mfr_part_number: RC0402JR-07220RL; Mistral Part No: 110020120013-R; Package: 0402; Part_type: RESISTORS\FIXED; Project: TI_AM243x LP EVM; RoHS: RoHS; Temperature: -55°C+155°C; Tolerance: 5%; Voltage: NA; Wattage: 1/16W; Weight: 0.65mg; Datasheet: Y:\MIS_DATABASE\DATASHEETS\RESISTORS\RCXXXXL-SER_MAR18.PDF
R16 R19 R21 R24 R27 R33 R40 R41 R43-R45 R47 R52 R66 R69 R177 R189 R191-R194 R196 R197 R202-R204 R207-R209 R211 R236 R588-R591 = RESISTOR: RES 10K 1/16W 5% 0402; Chkd/date: VASANTHA/061216; Crtd /date: MAZHAR/230805; Custom_Duty: 15%; Customs_HS_Code: 85332119; Distributor_name: DIGIKEY; Distributor_part_number: 311-10KJRCT-ND; Footprint Path: Y:\MIS_DATABASE\Library\ALTIUM_TOOL\PCB_FOOTPRINTS\Altium_Footprint_Lib.PcbLib; Height: 0.40MM; Library Path: Y:\MIS_DATABASE\Library\ALTIUM_TOOL\SCHEMATICS_PARTS\MS_DISCRETE_Library.schlib; Mfr_name: YAGEO AMERICA; Mfr_part_number: RC0402JR-0710KL; Mistral Part No: 110011060021-R; Package: 0402; Part_type: RESISTORS\FIXED; Project: HSE; RoHS: RoHS; Temperature: -55°C+155°C; Tolerance: 5%; Voltage: NA; Wattage: 1/16W; Weight: 0.65mg; Datasheet: Y:\MIS_DATABASE\DATASHEETS\RESISTORS\RCXXXXL-SER_MAR18.PDF
TP4 TP6 TP11 TP49 = TESTPOINT: TESTPOINT CIR 20 SMD; Chkd/date: SHREESHAIL/171006; Crtd /date: MAZHAR/171006; Custom_Duty: NA; Customs_HS_Code: NA; Distributor_name: NA; Distributor_part_number: NA; Footprint Path: Y:\MIS_DATABASE\Library\ALTIUM_TOOL\PCB_FOOTPRINTS\Altium_Footprint_Lib.PcbLib; Height: NA; Library Path: Y:\MIS_DATABASE\Library\ALTIUM_TOOL\SCHEMATICS_PARTS\MS_DISCRETE_Library.schlib; MECHANICAL 3D STEP FILE: NA; Mfr_name: LOCAL; Mistral Part No: NA; Package: SMD; Project: BT MODULE_CSRBC04; RoHS: NA; Temperature: NA; Tolerance: NA; Voltage: NA; Wattage: NA; Weight: NA; Datasheet: NA
U7 = DP83869HM_VQFN48: IC ETHERNET TRANSCEIVER 10/100/1000 WITH COPPER AND FIBRE INTERFACE VQFN48; Chkd/date: MANIRAJA/060519; Crtd /date: ALVY/060519; Custom_Duty: 15%; Customs_HS_Code: 85423100; Distributor_name: DIGIKEY; Distributor_part_number: 296-53377-1-ND; Footprint Path: Y:\MIS_DATABASE\Library\ALTIUM_TOOL\PCB_FOOTPRINTS\Altium_Footprint_Lib.PcbLib; Height: 1.00MM; Library Path: Y:\MIS_DATABASE\Library\ALTIUM_TOOL\SCHEMATICS_PARTS\MS_TELECOM_Library.schlib; Mfr_name: TEXAS INSTRUMENTS; Mistral Part No: 143019050002-R; Package: VQFN48; Part_type: ICS\TELECOM\TRANSCEIVER; Project: J7ES_ENET_DP83869HM_EXP; RoHS: RoHS; Temperature: -40°C+125°C; Tolerance: NA; Voltage: NA; Wattage: NA; Weight: NA; Datasheet: Y:\MIS_DATABASE\DATASHEETS\ICS\TELECOM\DP83869HM.PDF
U34 = SN74LVC1G08DBVRE4_SOT23-5: IC SINGLE 2-INPUT POSITIVE AND GATE SOT23-5; Chkd/date: SUHAS/221010; Crtd /date: USMAN/151008; Custom_Duty: 15%; Customs_HS_Code: 85423100; Distributor_name: DIGIKEY; Distributor_part_number: SN74LVC1G08DBVRE4-ND; Height: 1.45MM; Mfr_name: TEXAS INSTRUMENTS; Mistral Part No: 141009060026-R; Part_type: ICS\DIGITAL\GATES; Project: KHAN_MAIN; RoHS: Sb/ Br FREE; Temperature: -40°C+85°C; Datasheet: Y:\MIS_DATABASE\DATASHEETS\ICS\DIGITAL\GATES\SN74LVC1G08.PDF
J1 J2 J5 J6 = RECP_10X2: CON RECP 2X10 2.54MM PITCH ST TH; Chkd/date: MANIRAJA/231120; Crtd /date: ALVY/201120; Custom_Duty: 24%; Customs_HS_Code: 85369090; Distributor_name: NA; Distributor_part_number: NA; Footprint Path: Y:\MIS_DATABASE\Library\ALTIUM_TOOL\PCB_FOOTPRINTS\Altium_Footprint_Lib.PcbLib; Height: 8.51MM; Library Path: Y:\MIS_DATABASE\Library\ALTIUM_TOOL\SCHEMATICS_PARTS\MS_CONNECTOR_Library.schlib; Mfr_name: MAJOR LEAGUE; Mfr_part_number: CRD-081413-A-G; Mistral Part No: 150020110025-R; Package: THRU-HOLE; Part_type: CONNECTOR\RECEPTACLE; Project: TI_AM243x LP EVM; RoHS: RoHS; Temperature: -40°C+105°C; Tolerance: NA; Voltage: NA; Wattage: NA; Weight: NA; Datasheet: Y:\MIS_DATABASE\DATASHEETS\CONNECTORS\CRD-081413-A.PDF
J9 J14 = HEADER_3X1: CON HDR 1X3 2.54MM PITCH ST TH; Chkd/date: VASANTHA/211015; Crtd /date: VASANTHA/211015; Custom_Duty: 24%; Customs_HS_Code: 85369090; Distributor_name: DIGIKEY; Distributor_part_number: 732-5316-ND; Height: 8.54MM; Mfr_name: WURTH ELECTRONICS INC; Mfr_part_number: 61300311121; Mistral Part No: 150015100037-R; Package: THRU-HOLE; Part_type: CONNECTOR\HEADERS; Project: CYPHY_ROADKILL; RoHS: RoHS; Temperature: NA; Tolerance: NA; Voltage: NA; Wattage: NA; Weight: NA; Datasheet: Y:\MIS_DATABASE\DATASHEETS\CONNECTORS\6130XXX.PDF
J15 = CON_FLEX_40X1_20347: CON FPC 1X40 0.50MM PITCH FEMALE RT SMD; Chkd/date: ALVY/101220; Crtd /date: MANIRAJA/101220; Custom_Duty: 24%; Customs_HS_Code: 85369090; Distributor_name: NA; Distributor_part_number: NA; Footprint Path: Y:\MIS_DATABASE\Library\ALTIUM_TOOL\PCB_FOOTPRINTS\Altium_Footprint_Lib.PcbLib; Height: 1.30MM; Library Path: Y:\MIS_DATABASE\Library\ALTIUM_TOOL\SCHEMATICS_PARTS\MS_CONNECTOR_Library.schlib; Mfr_name: WURTH ELEKTRONIK; Mfr_part_number: 687140183622; Mistral Part No: 150020120010-R; Package: SMD; Part_type: CONNECTOR\FPC; Project: TI_AM243x LP EVM; RoHS: RoHS; Temperature: -25°C+85°C; Tolerance: NA; Voltage: NA; Wattage: NA; Weight: NA; Datasheet: Y:\MIS_DATABASE\DATASHEETS\CONNECTORS\687140183622.PDF
R178 R182 R186 R187 = RESISTOR: RES 2.2K 1/16W 5% 0402; Chkd/date: VASANTHA/061216; Crtd /date: BAVISH/021210; Custom_Duty: 15%; Customs_HS_Code: 85332119; Distributor_name: DIGIKEY; Distributor_part_number: 311-2.2KJRCT-ND; Footprint Path: Y:\MIS_DATABASE\Library\ALTIUM_TOOL\PCB_FOOTPRINTS\Altium_Footprint_Lib.PcbLib; Height: 0.40MM; Library Path: Y:\MIS_DATABASE\Library\ALTIUM_TOOL\SCHEMATICS_PARTS\MS_DISCRETE_Library.schlib; Mfr_name: YAGEO AMERICA; Mfr_part_number: RC0402JR-072K2L; Mistral Part No: 110010120018-R; Package: 0402; Part_type: RESISTORS\FIXED; Project: TE4; RoHS: RoHS; Temperature: -55°C+155°C; Tolerance: 5%; Voltage: NA; Wattage: 1/16W; Weight: 0.65mg; Datasheet: Y:\MIS_DATABASE\DATASHEETS\RESISTORS\RCXXXXL-SER_MAR18.PDF
U9 = TCA9617BDGKR_VSSOP8: IC FM+I2C BUS REPEATER LEVEL TRANSLATOR VSSOP8; Chkd/date: MANIRAJA/131017; Crtd /date: MANIRAJA/131017; Custom_Duty: 15%; Customs_HS_Code: 85423100; Distributor_name: DIGIKEY; Distributor_part_number: 296-40579-1-ND; Height: 1.10MM; Mfr_name: TEXAS INSTRUMENTS; Mistral Part No: 141017100010-R; Package: VSSOP8; Part_type: ICS\INTERFACE\LEVEL TRANSLATOR; Project: TI_MAXIE_CPB; RoHS: RoHS; Temperature: -40°C+85°C; Tolerance: NA; Voltage: NA; Wattage: NA; Weight: NA; Datasheet: Y:\MIS_DATABASE\DATASHEETS\ICS\INTERFACE\TCA9617B.PDF
U41 = TLV71318PDBVT_SOT23-5: IC 1uA ULTRA-LOW IQ 200mA LDO REGULATOR SOT23-5; Chkd/date: MANIRAJA/131120; Crtd /date: ALVY/121120; Custom_Duty: 15%; Customs_HS_Code: 85423100; Distributor_name: DIGIKEY; Distributor_part_number: 296-50256-1-ND; Footprint Path: Y:\MIS_DATABASE\Library\ALTIUM_TOOL\PCB_FOOTPRINTS\Altium_Footprint_Lib.PcbLib; Height: 1.45MM; Library Path: Y:\MIS_DATABASE\Library\ALTIUM_TOOL\SCHEMATICS_PARTS\MS_MISCPOWER_Library.schlib; Mfr_name: TEXAS INSTRUMENTS; Mistral Part No: 142020110015-R; Package: SOT23-5; Part_type: ICS\POWER\VOLTAGE REGULATOR; Project: TI_AM243x LP EVM; RoHS: RoHS; Temperature: -40°C+125°C; Tolerance: NA; Voltage: NA; Wattage: NA; Weight: 25.3mg; Datasheet: Y:\MIS_DATABASE\DATASHEETS\MISC\REGULATORS\TPS7A05XX.PDF
R17 R28 R34 R48 R53 R67 R70 = RESISTOR: RES 1K 1/16W 5% 0402; Chkd/date: VASANTHA/120516; Crtd /date: VASANTHA/120516; Custom_Duty: 15%; Customs_HS_Code: 85332119; Distributor_name: DIGIKEY; Distributor_part_number: 311-1.0KJRCT-ND; Footprint Path: Y:\MIS_DATABASE\Library\ALTIUM_TOOL\PCB_FOOTPRINTS\Altium_Footprint_Lib.PcbLib; Height: 0.40MM; Library Path: Y:\MIS_DATABASE\Library\ALTIUM_TOOL\SCHEMATICS_PARTS\MS_DISCRETE_Library.schlib; Mfr_name: YAGEO AMERICA; Mfr_part_number: RC0402JR-071KL; Mistral Part No: 110010070006-R; Package: 0402; Part_type: RESISTORS\FIXED; Project: TMDXCSK368; RoHS: RoHS; Temperature: -55°C+155°C; Tolerance: 5%; Voltage: NA; Wattage: 1/16W; Weight: 0.65mg; Datasheet: Y:\MIS_DATABASE\DATASHEETS\RESISTORS\RCXXXXL-SER_MAR18.PDF
R39 R205 R206 = RESISTOR: RES 49.9K 1/10W 1% 0402; Chkd/date: MANIRAJA/130617; Crtd /date: BAVISH/020611; Custom_Duty: 15%; Customs_HS_Code: 85332119; Distributor_name: DIGIKEY; Distributor_part_number: P49.9KLCT-ND; Footprint Path: Y:\MIS_DATABASE\Library\ALTIUM_TOOL\PCB_FOOTPRINTS\Altium_Footprint_Lib.PcbLib; Height: 0.40MM; Library Path: Y:\MIS_DATABASE\Library\ALTIUM_TOOL\SCHEMATICS_PARTS\MS_DISCRETE_Library.schlib; Mfr_name: PANASONIC-ECG; Mfr_part_number: ERJ-2RKF4992X; Mistral Part No: 110011060018-R; Package: 0402; Part_type: RESISTORS\FIXED; Project: AM4515_EVM_LCD; RoHS: RoHS; Temperature: -55°C+155°C; Tolerance: 1%; Voltage: NA; Wattage: 1/10W; Weight: 0.8mg; Datasheet: Y:\MIS_DATABASE\DATASHEETS\RESISTORS\PAN-ERJSER_NOV17.PDF
SW4 = SW16_CHS-08A: SWITCH SLIDE SPST ST SMD; Chkd/date: MANIRAJA/051020; Crtd /date: ALVY/011020; Custom_Duty: 24%; Customs_HS_Code: 85369090; Distributor_name: DIGIKEY; Distributor_part_number: 732-3857-1-ND; Footprint Path: Y:\MIS_DATABASE\Library\ALTIUM_TOOL\PCB_FOOTPRINTS\Altium_Footprint_Lib.PcbLib; Height: 2.65MM; Library Path: Y:\MIS_DATABASE\Library\ALTIUM_TOOL\SCHEMATICS_PARTS\MS_SWITCH_Library.schlib; Mfr_name: WURTH ELECTRONICS; Mistral Part No: 130020100001-R; Package: SMD; Part_type: ELECTRO-MECHANICAL\SWITCH; Project: AM64X_SKEVM; RoHS: RoHS; Temperature: -40°C+85°C; Tolerance: NA; Voltage: NA; Wattage: NA; Weight: 281.7mg; Datasheet: Y:\MIS_DATABASE\DATASHEETS\MISC\SWITCHES\4161311608XX.PDF
TP2 TP3 = TESTPOINT: TESTPOINT 1.0MM DRILL PTH; Chkd/date: MAZHAR/271211; Crtd /date: SHREESHAIL/041005; Distributor_name: NA; Distributor_part_number: NA; Height: NA; Mfr_name: LOCAL; Mistral Part No: 130009030938; Package: THRU-HOLE; Project: HSE; Datasheet: NA
U4 = SN74AVC8T245RHL_QFN24: IC BUS TRANSCEIVER 8-BIT DUAL-SUPPLY QFN24; Chkd/date: VASANTHA/231216; Crtd /date: BAVISH/290411; Custom_Duty: 15%; Customs_HS_Code: 85423100; Distributor_name: DIGIKEY; Distributor_part_number: 296-17859-1-ND; Height: 1.00MM; Mfr_name: TEXAS INSTRUMENTS; Mfr_part_number: SN74AVC8T245RHLR; Mistral Part No: 143011040001-R; Package: QFN24; Part_type: ICS\TELECOM\TRANSCEIVER; Project: OMAPL1_PEC20; RoHS: RoHS; Temperature: -40°C+85°C; Tolerance: NA; Voltage: NA; Wattage: NA; Weight: NA; Datasheet: Y:\MIS_DATABASE\DATASHEETS\ICS\DIGITAL\BUSTRANSCEIVER\SN74AVC8T245.PDF
U26 = TCA6408ARGTR_VQFN16: IC 8-BIT I2C AND SMBUS I/O EXPANDER WITH INTERRUPT O/P VQFN16; Chkd/date: MANIRAJA/151018; Crtd /date: MANIRAJA/151018; Custom_Duty: 15%; Customs_HS_Code: 85423100; Distributor_name: DIGIKEY; Distributor_part_number: 296-24825-1-ND; Footprint Path: Y:\MIS_DATABASE\Library\ALTIUM_TOOL\PCB_FOOTPRINTS\Altium_Footprint_Lib.PcbLib; Height: 1.00MM; Library Path: Y:\MIS_DATABASE\Library\ALTIUM_TOOL\SCHEMATICS_PARTS\MS_MISCINTERFACE_Library.schlib; Mfr_name: TEXAS INSTRUMENTS; Mistral Part No: 141018100011-R; Package: VQFN16; Part_type: ICS\INTERFACE; Project: TI_60GHz-AOP; RoHS: RoHS; Temperature: -40°C+85°C; Tolerance: NA; Voltage: NA; Wattage: NA; Weight: 24.1mg; Datasheet: Y:\MIS_DATABASE\DATASHEETS\ICS\INTERFACE\TCA6408AXX.PDF
U28 = SN74LVC1G08DBVRE4_SOT23-5: IC SINGLE 2-INPUT POSITIVE AND GATE SOT23-5; Automotive Alternate_mfr_name: TEXAS INSTRUMENTS; Automotive Alternate_mfr_part_number: SN74LVC1G08QDBVRQ1; Chkd/date: SUHAS/221010; Crtd /date: USMAN/151008; Custom_Duty: 15%; Customs_HS_Code: 85423100; Distributor_name: DIGIKEY; Distributor_part_number: SN74LVC1G08DBVRE4-ND; Height: 1.45MM; Mfr_name: TEXAS INSTRUMENTS; Mistral Part No: 141009060026-R; Part_type: ICS\DIGITAL\GATES; Project: KHAN_MAIN; RoHS: Sb/ Br FREE; Temperature: -40°C+85°C; Datasheet: Y:\MIS_DATABASE\DATASHEETS\ICS\DIGITAL\GATES\SN74LVC1G08.PDF
U18 = AM243X_SOC_LP_EVM_BGA293: IC QUAD CORE R5F- MCU, FCCSP-293; Chkd/date: PRADEEP/130923; Crtd /date: PRADEEP/130923; Custom_Duty: 15%; Customs_HS_Code: 85423100; Distributor_name: NA; Distributor_part_number: NA; Footprint Path: Y:\MIS_DATABASE\Library\ALTIUM_TOOL\PCB_FOOTPRINTS\Altium_Footprint_Lib.PcbLib; Height: 1.00MM; Library Path: Y:\MIS_DATABASE\Library\ALTIUM_TOOL\SCHEMATICS_PARTS\MS_MICROPROCESSOR_Library.schlib; Library Ref: AM243x SoC_LP_EVM_BGA293; Mfr_name: TEXAS INSTRUMENTS; Mistral Part No: 141223090001; Package: BGA293; Part_type: ICS\DIGITAL\MICROPROCESSOR; Project: AM243_LP; RoHS: NA; Temperature: NA; Tolerance: NA; Voltage: NA; Wattage: NA; Weight: NA; Datasheet: Y:\MIS_DATABASE\DATASHEETS\ICS\DIGITAL\MICROCONTROLLER\AM2434.PDF

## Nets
DGND: C5.2 C6.2 C7.2 C8.2 C11.2 C14.2 C17.2 C19.2 C23.2 C31.2 C32.2 C34.2 C84.2 C85.2 C86.2 C88.2 C92.2 C93.2 C95.2 C96.2 C97.2 C98.2 C99.2 C100.2 C101.2 C107.2 C113.2 C119.2 C146.2 C155.2 C226.2 C243.2 J1.4 J2.2 J5.4 J6.2 J9.2 J9.3 J14.2 J14.3 J15.7 J15.16 J15.25 J15.34 J15.40 J15.41 J15.42 J18.1(CH-GND) Q10.4(S1) Q10.7(S2) Q11.4(S1) Q11.7(S2) Q12.4(S1) Q12.7(S2) R16.2 R22.2 R24.1 R27.2 R33.2 R47.2 R52.2 R64.2 R66.2 R69.2 R71.2 R72.2 R74.2 R75.2 R76.2 R177.1 R184.2 R200.2 R203.1 R204.1 R205.1 R206.1 R207.1 R208.1 R221.2 R228.2 R589.1 R591.1 TP2.1(TP) U4.10(A8) U4.11(GND1) U4.12(GND2) U4.13(GND3) U4.25(EP) U7.49(GND) U9.4(GND) U26.6(GND) U26.17(EP) U28.3(GND) U34.3(GND) U41.2(GND) ; also on sheet 10 11 12 13 14 15 16 17 22 23 24 25 26 27 28
VCC3V3_TA: C5.1 C31.1 C85.1 C88.1 C146.1 C155.1 C243.1 J15.1 J15.2 J15.3 R17.2 R28.2 R34.2 R48.2 R53.2 R67.2 R70.2 R178.1 R182.1 R186.1 R187.1 R189.2 R191.2 R196.2 R197.2 R202.2 R209.2 TP49.1(TP) U4.1(VCCA) U4.2(DIR) U9.5(EN) U9.8(VCCB) U26.14(VCCP) U26.15(VCCI) U28.5(VCC) U41.5(OUT)
VDD_1V1: C17.1 C19.1 C34.1 C95.1 C96.1 C97.1 C98.1 C113.1 U7.6(VDDA1P1) U7.31(VDD1P1) U7.39(VDD1P1) ; also on sheet 17 28
VDD_2V5: C11.1 C23.1 C92.1 C99.1 C100.1 C107.1 U7.3(VDDA2P5) U7.9(VDDA2P5) ; also on sheet 17 28
VDDSHV_SDIO: R19.2 R21.2 R192.2 R193.2 R194.2 ; also on sheet 24
BOOTMODE0: R39.1 R208.2 ; also on sheet 11
BOOTMODE1: R40.1 R207.2 ; also on sheet 11
BOOTMODE2: R41.1 R206.2 ; also on sheet 11
BOOTMODE3: U4.21(B1) ; also on sheet 11
BOOTMODE4: U4.20(B2) ; also on sheet 11
BOOTMODE5: U4.19(B3) ; also on sheet 11
BOOTMODE6: U4.18(B4) ; also on sheet 11
BOOTMODE7: U4.17(B5) ; also on sheet 11
BOOTMODE8: U4.16(B6) ; also on sheet 11
BOOTMODE9: U4.15(B7) ; also on sheet 11
BOOTMODE10: R43.1 R205.2 ; also on sheet 11
BOOTMODE11: R44.1 R204.2 ; also on sheet 11
BOOTMODE12: R45.1 R203.2 ; also on sheet 11
BOOTMODE14: R588.1 R589.2 ; also on sheet 11
BOOTMODE15: R590.1 R591.2 ; also on sheet 11
BOOTMODEON: R24.2 U4.22(~{OE}) U28.4(Y)
BP_3V3: J5.1 R163.2
BP_5V0: J5.2 R161.1
BP_ADC0_AIN0: J1.3 ; also on sheet 16
BP_ADC0_AIN1: J1.11 ; also on sheet 16
BP_ADC0_AIN2: J1.6 ; also on sheet 16
BP_ADC0_AIN3: J1.8 ; also on sheet 16
BP_ADC0_AIN4: J1.10 ; also on sheet 16
BP_ADC0_AIN5: J1.12 ; also on sheet 16
BP_ADC0_AIN6: J1.14 ; also on sheet 16
BP_ADC0_AIN7: J1.16 ; also on sheet 16
BP_CONN_1_PORz: J2.10 ; also on sheet 10
BP_CONN_2_PORz: J6.10 ; also on sheet 10
EHRPWM0_A: J2.1 ; also on sheet 11
EHRPWM0_B: J2.3 ; also on sheet 11
EHRPWM0_TZn_IN0: J2.13 ; also on sheet 11
EHRPWM1_A: J2.5 ; also on sheet 11
EHRPWM1_B: J2.7 ; also on sheet 11
EHRPWM2_A: J2.9 ; also on sheet 13
EHRPWM2_B: J2.11 ; also on sheet 13
EPHY1_XI: R13.2 R185.2 U7.20(XI)
ETH2_EARTH: C101.1 J18.15(SH1) J18.16(SH2) R200.1
GPIO1_0: J2.15 ; also on sheet 11
GPIO1_1: J2.17 ; also on sheet 11
GPIO1_2: J2.19 ; also on sheet 11
GPIO1_3: J2.4 ; also on sheet 11
GPIO1_4: J2.8 ; also on sheet 11
GPIO1_5: J2.16 ; also on sheet 11
GPIO1_6: J5.15 ; also on sheet 11
GPIO1_8: J6.20 ; also on sheet 11
GPIO1_12: J1.9 ; also on sheet 11
GPIO1_18: J1.15 ; also on sheet 11 13
GPIO1_19: J5.9 ; also on sheet 11
GPIO1_20: J2.20 ; also on sheet 11
GPIO1_21: J5.14 ; also on sheet 11
GPIO1_22: J5.16 ; also on sheet 11
GPIO1_26: J5.18 ; also on sheet 11
GPIO1_31: J5.20 ; also on sheet 11
GPIO1_32: J6.17 ; also on sheet 11
GPIO1_33: J6.19 ; also on sheet 11
GPIO1_35: J6.4 ; also on sheet 11
GPIO1_36/PERIF_OUT_EN: J6.8 ; also on sheet 13
GPIO1_40: J6.16 ; also on sheet 11
GPIO1_41: J6.18 ; also on sheet 11
GPIO1_77: J6.13 U18.B17(MMC1_SDCD)
GPIO1_78: J6.15 U18.C16(MMC1_SDWP)
GPIO_RGMII2_PHY_RSTn: R236.1 U34.1(A) ; also on sheet 12
MAIN_UART2_RXD: J1.5 ; also on sheet 11
MAIN_UART2_TXD: J1.7 ; also on sheet 11
MAIN_UART4_RXD/GPIO1_69: J5.5 ; also on sheet 13
MAIN_UART4_TXD: J5.7 ; also on sheet 11
OBSCLK0: R185.1 ; also on sheet 11
PORZ_OUT: U28.2(B) U34.2(B) ; also on sheet 11 12 15 17
PRG1_CPSW_ETH2_CLK_OUT: TP11.1(TP) U7.40(CLK_OUT)
PRG1_CPSW_ETH2_D0M: J18.10(MX0-) U7.2(TD_M_A)
PRG1_CPSW_ETH2_D0P: J18.9(MX0+) U7.1(TD_P_A)
PRG1_CPSW_ETH2_D1M: J18.8(MX1-) U7.5(TD_M_B)
PRG1_CPSW_ETH2_D1P: J18.7(MX1+) U7.4(TD_P_B)
PRG1_CPSW_ETH2_D2M: J18.6(MX2-) U7.8(TD_M_C)
PRG1_CPSW_ETH2_D2P: J18.5(MX2+) U7.7(TD_P_C)
PRG1_CPSW_ETH2_D3M: J18.4(MX3-) U7.11(TD_M_D)
PRG1_CPSW_ETH2_D3P: J18.3(MX3+) U7.10(TD_P_D)
PRG1_CPSW_ETH2_LED1: J18.12 Q10.1(D1) Q10.2(D2) Q10.5(D3) Q10.6(D4) Q10.8(D5)
PRG1_CPSW_ETH2_LED2: J18.13 Q11.1(D1) Q11.2(D2) Q11.5(D3) Q11.6(D4) Q11.8(D5) R220.1
PRG1_CPSW_ETH2_LED3: J18.14 Q12.1(D1) Q12.2(D2) Q12.5(D3) Q12.6(D4) Q12.8(D5) R223.1
PRG1_CPSW_ETH2_LED_1000/RX_ER: Q11.3(G) R75.1 R226.2 U7.46(LED_1/RX_ER) ; also on sheet 12
PRG1_CPSW_ETH2_LED_ACT: Q10.3(G) R74.1 R227.2 U7.45(LED_2/GPIO_0) ; also on sheet 16
PRG1_CPSW_ETH2_LED_LINK: R76.1 R225.2 U7.47(LED_0) ; also on sheet 12
PRG1_CPSW_ETH2_RBIAS: R22.1 U7.12(RBIAS)
PRG1_CPSW_RGMII2_CLK: R13.1 ; also on sheet 14
PRG1_CPSW_RGMII2_GPIO_1: Q12.3(G) R12.2 R184.1 U7.22(JTAG_TDO/GPIO_1)
PRG1_CPSW_RGMII2_RD0: R64.1 R218.2 U7.33(RX_D0) ; also on sheet 12
PRG1_CPSW_RGMII2_RD1: R68.2 R221.1 U7.34(RX_D1) ; also on sheet 12
PRG1_CPSW_RGMII2_RD2: R71.1 R230.2 U7.35(RX_D2) ; also on sheet 12
PRG1_CPSW_RGMII2_RD3: R72.1 R229.2 U7.36(RX_D3) ; also on sheet 12
PRG1_CPSW_RGMII2_RSTn: U7.43(RESET_N) U34.4(Y)
PRG1_CPSW_RGMII2_RX_CTL: R73.2 R228.1 U7.38(RX_CTRL/RX_DV) ; also on sheet 12
PRG1_CPSW_RGMII2_RXC: R51.1 ; also on sheet 12
PRG1_CPSW_RGMII2_RXC_R: R51.2 U7.32(RX_CLK)
PRG1_CPSW_RGMII2_TD0: U7.28(TX_D0) ; also on sheet 12
PRG1_CPSW_RGMII2_TD1: U7.27(TX_D1) ; also on sheet 12
PRG1_CPSW_RGMII2_TD2: U7.26(TX_D2) ; also on sheet 12
PRG1_CPSW_RGMII2_TD3: U7.25(TX_D3) ; also on sheet 12
PRG1_CPSW_RGMII2_TX_CTL: U7.37(TX_CTRL/TX_EN) ; also on sheet 12
PRG1_CPSW_RGMII2_TXC: R23.1 ; also on sheet 12
PRG1_CPSW_RGMII2_TXC_R: R23.2 U7.29(GTX_CLK/TX_CLK)
PRG1_CPSW_RGMII_INTn: U7.44(INT_N/PWDN_N) ; also on sheet 12 17
PRG1_IEP0_EDC_LATCH_IN0: J5.8 ; also on sheet 12
PRG1_IEP0_EDC_LATCH_IN1: J5.12 ; also on sheet 12
PRG1_IEP0_EDC_SYNC_OUT0: J5.6 ; also on sheet 12
PRG1_IEP0_EDC_SYNC_OUT1: J5.10 ; also on sheet 12
PRG1_MDIO0_MDC: U7.42(MDC) ; also on sheet 12 17
PRG1_MDIO0_MDIO: U7.41(MDIO) ; also on sheet 12 17
SoC_I2C0_SCL: R141.1 ; also on sheet 11 15 23
SoC_I2C0_SCL_BP: J5.17 R141.2
SoC_I2C0_SDA: R158.1 ; also on sheet 11 15 23
SoC_I2C0_SDA_BP: J5.19 R158.2
SoC_I2C1_SCL: J1.17 U9.2(SCLA) ; also on sheet 11
SoC_I2C1_SDA: J1.19 U9.3(SDAA) ; also on sheet 11
SoC_I2C1_TA_SCL: J15.36 R187.2 U9.7(SCLB)
SoC_I2C1_TA_SDA: J15.38 R182.2 U9.6(SDAB)
SPI0_CLK: J5.13 ; also on sheet 11
SPI0_CS1: J6.6 ; also on sheet 11
SPI0_D0: J6.12 ; also on sheet 11
SPI0_D1: J6.14 ; also on sheet 11
SPI3_CLK: J1.13 ; also on sheet 11
SPI3_CS0: J2.6 ; also on sheet 11
SPI3_CS1/PRG0_PRU1_GPI11: J2.18 ; also on sheet 13
SPI3_D0/GPIO1_18: J2.12 ; also on sheet 13
SPI3_D1: J2.14 ; also on sheet 11
SYNC1_OUT: J5.3 ; also on sheet 11 13
SYNC2_OUT: J1.18 ; also on sheet 13
SYNC3_OUT: J1.20 ; also on sheet 13
SYS_BOOTMODE3: R16.1 SW4.1 U4.3(A1) U26.2(P0)
SYS_BOOTMODE4: R27.1 SW4.2 U4.4(A2) U26.3(P1)
SYS_BOOTMODE5: R33.1 SW4.3 U4.5(A3) U26.4(P2)
SYS_BOOTMODE6: R47.1 SW4.4 U4.6(A4) U26.5(P3)
SYS_BOOTMODE7: R52.1 SW4.5 U4.7(A5) U26.7(P4)
SYS_BOOTMODE8: R66.1 SW4.6 U4.8(A6) U26.8(P5)
SYS_BOOTMODE9: R69.1 SW4.7 U4.9(A7) U26.9(P6)
TA_BOOTMODE_I2C_SCL: J15.37 R186.2 U26.12(SCL)
TA_BOOTMODE_I2C_SDA: J15.39 R178.2 U26.13(SDA)
TA_GPIO2: J15.31 R197.1 TP6.1(TP)
TA_GPIO3: J15.32 R196.1 TP3.1(TP) U28.1(A)
TA_GPIO4: J15.33 R189.1 U26.1(~{RESET})
TA_PORZn: J15.27 R211.1 ; also on sheet 10
TA_POWERDOWN: J15.26 ; also on sheet 27
TA_PWR_EN: R251.2 U41.3(EN)
TA_SOC_INTn: J15.30 R202.1 ; also on sheet 10
TA_WARMRESETn: J15.28 R209.1 ; also on sheet 10
TCA6408_EXP_ADDR: R177.2 U26.16(ADDR)
TCA6408_EXP_INT: R191.1 U26.11(~{INT})
TIMER_IO0: R193.1 U18.K18(MMC1_DAT3) ; also on sheet 13
TIMER_IO0/EHPWM3_B: J6.1 ; also on sheet 13
TIMER_IO1: R19.1 U18.K20(MMC1_DAT2) ; also on sheet 13
TIMER_IO1/EHPWM5_A: J6.3 ; also on sheet 13
TIMER_IO2: R192.1 U18.J19(MMC1_DAT1) ; also on sheet 13
TIMER_IO2/EHPWM8_B: J6.5 ; also on sheet 13
TIMER_IO3: R194.1 U18.J18(MMC1_DAT0) ; also on sheet 13
TIMER_IO3/EHPWM8_A: J6.7 ; also on sheet 13
TIMER_IO4: R20.1 ; also on sheet 13
TIMER_IO4/EHPWM7_B: J6.9 ; also on sheet 13
TIMER_IO4_R: R20.2 U18.J20(MMC1_CLK)
TIMER_IO5: R21.1 U18.J21(MMC1_CMD) ; also on sheet 13
TIMER_IO5/EHPWM7_A: J6.11 ; also on sheet 13
VSYS_3V3: C6.1 C7.1 C8.1 C14.1 C32.1 C84.1 C86.1 C93.1 C119.1 J1.1 J14.1 R12.1 R39.2 R40.2 R41.2 R43.2 R44.2 R45.2 R68.1 R73.1 R163.1 R210.1 R218.1 R220.2 R223.2 R225.1 R226.1 R227.1 R229.1 R230.1 R236.2 R588.2 R590.2 U4.23(VCCB1) U4.24(VCCB2) U7.18(VDDIO) U7.30(VDDIO) U9.1(VCCA) U34.5(VCC) ; also on sheet 10 11 12 13 14 15 16 17 22 23 24 25 27 28
VSYS_5V0: J1.2 J9.1 R161.2 R211.2 ; also on sheet 10 13 14 25 26 27 28
VUSB_5V0: C226.1 R251.1 U41.1(IN) ; also on sheet 26
N29126233: R67.1 SW4.11
N29126235: R53.1 SW4.12
N29126237: R48.1 SW4.13
N29126239: R34.1 SW4.14
N29126243: R70.1 SW4.10
N29126245: R28.1 SW4.15
N29126269: R17.1 SW4.16
N30391563: J18.11 R210.2
N30391831: TP4.1(TP) U7.13(VDDA1P8_1) U7.48(VDDA1P8_2)

Not connected (* = marked no-connect by the designer): J5 11*; J15 4* 5* 6* 8* 9* 10* 11* 12* 13* 14* 15* 17* 18* 19* 20* 21* 22* 23* 24* 29* 35*; J18 2(VCC)*; SW4 8* 9*; U4 14(B8)*; U7 14(SON)* 15(SOP)* 16(SIP)* 17(SIN)* 19(XO)* 21(JTAG_CLK/TX_ER)* 23(JTAG_TMS)* 24(JTAG_TDI/SD)*; U26 10(P7)*; U41 4(NC)*

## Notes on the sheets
sheet 18
- RJ45 Connector with Integrated Magnetics
- PRG / CPSW RGMII2 Ethernet PHY
- OBSCLK is used to source the RGMII2 Ethernet PHY
- Mount R240 & R185 and DNI R244 & R13 to source the RGMII2
  Ethernet PHY from OBSCLK
- RGMII2 PHY Strapping Resistors
- RGMII2 PHY Speed & Activity LED Drivers
- PHY ADDRESS = 01111
- Auto-negotiation, 10/100/1000 advertised, Auto-MDI-X
- RGMII to Copper (1000BaseT/100Base-TX/10Base-Te)
- RGMII2 PHY Reset
- (From SoC GPIO)
sheet 19
- Booster Pack Header
- Boosterpack Header Site - 1
- GPIO0_18
- GPIO0_15
- GPIO0_82
- GPIO0_83
- GPIO1_17
- GPIO0_16
- GPIO0_21
- GPIO0_23
- GPIO0_24
- GPIO1_13
- GPIO1_16
- GPIO0_17
- GPIO1_14
- GPIO1_66
- GPIO1_60
- GPIO1_15
- GPIO1_67
- GPIO1_61
- Boosterpack Header Site - 2
- GPIO1_71
- GPIO1_69
- GPIO1_72
- GPIO1_11
- GPIO0_64
- GPIO1_73
- GPIO1_43
- GPIO1_7
- GPIO0_62
- GPIO0_63
- GPIO1_74
- GPIO1_75
- GPIO0_52
- GPIO1_76
- GPIO1_45
- GPIO1_44
- GPIO1_46
- SoC MMC1 Connection to BP Header
sheet 20
- 40 - Pin Test Automation Header
- I2C Buffer for TA Header
- Test Automation GPIO Mappping
- Test Automation Board Power
- Direction WRT CTRL
- Internal/
  External
  PU/PD states
- SIGNAL NAME
- DESCRIPTION
- TA_POWERDOWN
- Used to Powerdown the Board
- OUTPUT
- External Pullup
- TA_PORZn
- Used to Reset the SoC PORZ
- OUTPUT
- External Pullup
- TA_WARMRESETn
- Used to Reset the SoC Warmreset
- OUTPUT
- External Pullup
- TA_GPIO3
- Used to Disable the BOOTMODE Buffer
- OUTPUT
- External Pullup
- TA_GPIO4
- Used to Reset the BOOTMODE IO Expander
- OUTPUT
- External Pullup
- TA_SOC_INTn
- Interrupt to SoC
- OUTPUT
- External Pullup
- 3.3V @ 200mA
sheet 21
- BOOT Mode Switch
- IO Expander
- BOOT Mode Buffer
- SWITCH ON  =  LOGIC 1
  SWITCH OFF =  LOGIC 0
- (From TA Header)
- (From TA Header)
- DIR = H: A -> B
  OE = H: output = Hi-Z
- AM243x LP - Boot-Mode selection table
- Boot Modes
  Supported
- Place these two TPs with 100mils
  spacing to insert external jumper
- SW4.1
- SW4.2
- SW4.3
- SW4.4
- SW4.5
- SW4.6
- SW4.7
- QSPI FLASH
- 0
- 1
- 0
- 0
- 0
- 1
- 0
- MMC1/SD Card
- 0
- 0
- 0
- 1
- 0
- 0
- 1
- UART
- 1
- 1
- 1
- 0
- 0
- 0
- 0
- USB - DFU
- 0
- 1
- 0
- 1
- 0
- 0
- 0
- No Boot
- 1
- 1
- 1
- 1
- 0
- 0
- 0
- BOOT_MODE0, 1 & 2 are used to select system Clock frequency
  (Default 25 MHz is selected)
- BOOT_MODE10, 11 & 12 are used to select Back-up Boot Mode
  (By Default No Back-up Boot mode is selected)
